VERSION 5.8 ;
BUSBITCHARS "[]" ;
DIVIDERCHAR "/" ;
UNITS
    DATABASE MICRONS 1000 ;
END UNITS

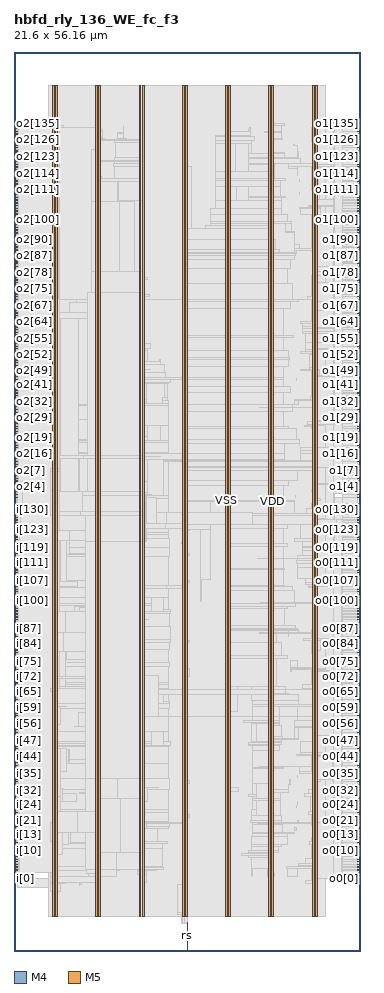
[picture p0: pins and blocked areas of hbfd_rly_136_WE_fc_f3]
MACRO hbfd_rly_136_WE_fc_f3
  FOREIGN hbfd_rly_136_WE_fc_f3 0 0 ;
  CLASS BLOCK ;
  SIZE 21.6 BY 56.16 ;
  PIN clk_in
    DIRECTION INPUT ;
    USE SIGNAL ;
    PORT
      LAYER M4 ;
        RECT  0 16.224 0.192 16.248 ;
    END
  END clk_in
  PIN clk_out0
    DIRECTION OUTPUT ;
    USE SIGNAL ;
    PORT
      LAYER M4 ;
        RECT  21.408 16.224 21.6 16.248 ;
    END
  END clk_out0
  PIN clk_out1
    DIRECTION OUTPUT ;
    USE SIGNAL ;
    PORT
      LAYER M4 ;
        RECT  21.408 39.984 21.6 40.008 ;
    END
  END clk_out1
  PIN clk_out2
    DIRECTION OUTPUT ;
    USE SIGNAL ;
    PORT
      LAYER M4 ;
        RECT  0 39.984 0.192 40.008 ;
    END
  END clk_out2
  PIN i[0]
    DIRECTION INPUT ;
    USE SIGNAL ;
    PORT
      LAYER M4 ;
        RECT  0 4.512 0.192 4.536 ;
    END
  END i[0]
  PIN i[100]
    DIRECTION INPUT ;
    USE SIGNAL ;
    PORT
      LAYER M4 ;
        RECT  0 21.888 0.192 21.912 ;
    END
  END i[100]
  PIN i[101]
    DIRECTION INPUT ;
    USE SIGNAL ;
    PORT
      LAYER M4 ;
        RECT  0 22.032 0.192 22.056 ;
    END
  END i[101]
  PIN i[102]
    DIRECTION INPUT ;
    USE SIGNAL ;
    PORT
      LAYER M4 ;
        RECT  0 22.224 0.192 22.248 ;
    END
  END i[102]
  PIN i[103]
    DIRECTION INPUT ;
    USE SIGNAL ;
    PORT
      LAYER M4 ;
        RECT  0 22.416 0.192 22.44 ;
    END
  END i[103]
  PIN i[104]
    DIRECTION INPUT ;
    USE SIGNAL ;
    PORT
      LAYER M4 ;
        RECT  0 22.56 0.192 22.584 ;
    END
  END i[104]
  PIN i[105]
    DIRECTION INPUT ;
    USE SIGNAL ;
    PORT
      LAYER M4 ;
        RECT  0 22.752 0.192 22.776 ;
    END
  END i[105]
  PIN i[106]
    DIRECTION INPUT ;
    USE SIGNAL ;
    PORT
      LAYER M4 ;
        RECT  0 22.896 0.192 22.92 ;
    END
  END i[106]
  PIN i[107]
    DIRECTION INPUT ;
    USE SIGNAL ;
    PORT
      LAYER M4 ;
        RECT  0 23.088 0.192 23.112 ;
    END
  END i[107]
  PIN i[108]
    DIRECTION INPUT ;
    USE SIGNAL ;
    PORT
      LAYER M4 ;
        RECT  0 23.232 0.192 23.256 ;
    END
  END i[108]
  PIN i[109]
    DIRECTION INPUT ;
    USE SIGNAL ;
    PORT
      LAYER M4 ;
        RECT  0 23.424 0.192 23.448 ;
    END
  END i[109]
  PIN i[10]
    DIRECTION INPUT ;
    USE SIGNAL ;
    PORT
      LAYER M4 ;
        RECT  0 6.24 0.192 6.264 ;
    END
  END i[10]
  PIN i[110]
    DIRECTION INPUT ;
    USE SIGNAL ;
    PORT
      LAYER M4 ;
        RECT  0 23.616 0.192 23.64 ;
    END
  END i[110]
  PIN i[111]
    DIRECTION INPUT ;
    USE SIGNAL ;
    PORT
      LAYER M4 ;
        RECT  0 23.76 0.192 23.784 ;
    END
  END i[111]
  PIN i[112]
    DIRECTION INPUT ;
    USE SIGNAL ;
    PORT
      LAYER M4 ;
        RECT  0 23.952 0.192 23.976 ;
    END
  END i[112]
  PIN i[113]
    DIRECTION INPUT ;
    USE SIGNAL ;
    PORT
      LAYER M4 ;
        RECT  0 24.096 0.192 24.12 ;
    END
  END i[113]
  PIN i[114]
    DIRECTION INPUT ;
    USE SIGNAL ;
    PORT
      LAYER M4 ;
        RECT  0 24.288 0.192 24.312 ;
    END
  END i[114]
  PIN i[115]
    DIRECTION INPUT ;
    USE SIGNAL ;
    PORT
      LAYER M4 ;
        RECT  0 24.48 0.192 24.504 ;
    END
  END i[115]
  PIN i[116]
    DIRECTION INPUT ;
    USE SIGNAL ;
    PORT
      LAYER M4 ;
        RECT  0 24.624 0.192 24.648 ;
    END
  END i[116]
  PIN i[117]
    DIRECTION INPUT ;
    USE SIGNAL ;
    PORT
      LAYER M4 ;
        RECT  0 24.816 0.192 24.84 ;
    END
  END i[117]
  PIN i[118]
    DIRECTION INPUT ;
    USE SIGNAL ;
    PORT
      LAYER M4 ;
        RECT  0 24.96 0.192 24.984 ;
    END
  END i[118]
  PIN i[119]
    DIRECTION INPUT ;
    USE SIGNAL ;
    PORT
      LAYER M4 ;
        RECT  0 25.152 0.192 25.176 ;
    END
  END i[119]
  PIN i[11]
    DIRECTION INPUT ;
    USE SIGNAL ;
    PORT
      LAYER M4 ;
        RECT  0 6.432 0.192 6.456 ;
    END
  END i[11]
  PIN i[120]
    DIRECTION INPUT ;
    USE SIGNAL ;
    PORT
      LAYER M4 ;
        RECT  0 25.296 0.192 25.32 ;
    END
  END i[120]
  PIN i[121]
    DIRECTION INPUT ;
    USE SIGNAL ;
    PORT
      LAYER M4 ;
        RECT  0 25.488 0.192 25.512 ;
    END
  END i[121]
  PIN i[122]
    DIRECTION INPUT ;
    USE SIGNAL ;
    PORT
      LAYER M4 ;
        RECT  0 25.68 0.192 25.704 ;
    END
  END i[122]
  PIN i[123]
    DIRECTION INPUT ;
    USE SIGNAL ;
    PORT
      LAYER M4 ;
        RECT  0 25.824 0.192 25.848 ;
    END
  END i[123]
  PIN i[124]
    DIRECTION INPUT ;
    USE SIGNAL ;
    PORT
      LAYER M4 ;
        RECT  0 26.016 0.192 26.04 ;
    END
  END i[124]
  PIN i[125]
    DIRECTION INPUT ;
    USE SIGNAL ;
    PORT
      LAYER M4 ;
        RECT  0 26.16 0.192 26.184 ;
    END
  END i[125]
  PIN i[126]
    DIRECTION INPUT ;
    USE SIGNAL ;
    PORT
      LAYER M4 ;
        RECT  0 26.352 0.192 26.376 ;
    END
  END i[126]
  PIN i[127]
    DIRECTION INPUT ;
    USE SIGNAL ;
    PORT
      LAYER M4 ;
        RECT  0 26.496 0.192 26.52 ;
    END
  END i[127]
  PIN i[128]
    DIRECTION INPUT ;
    USE SIGNAL ;
    PORT
      LAYER M4 ;
        RECT  0 26.688 0.192 26.712 ;
    END
  END i[128]
  PIN i[129]
    DIRECTION INPUT ;
    USE SIGNAL ;
    PORT
      LAYER M4 ;
        RECT  0 26.88 0.192 26.904 ;
    END
  END i[129]
  PIN i[12]
    DIRECTION INPUT ;
    USE SIGNAL ;
    PORT
      LAYER M4 ;
        RECT  0 6.576 0.192 6.6 ;
    END
  END i[12]
  PIN i[130]
    DIRECTION INPUT ;
    USE SIGNAL ;
    PORT
      LAYER M4 ;
        RECT  0 27.024 0.192 27.048 ;
    END
  END i[130]
  PIN i[131]
    DIRECTION INPUT ;
    USE SIGNAL ;
    PORT
      LAYER M4 ;
        RECT  0 27.216 0.192 27.24 ;
    END
  END i[131]
  PIN i[132]
    DIRECTION INPUT ;
    USE SIGNAL ;
    PORT
      LAYER M4 ;
        RECT  0 27.36 0.192 27.384 ;
    END
  END i[132]
  PIN i[133]
    DIRECTION INPUT ;
    USE SIGNAL ;
    PORT
      LAYER M4 ;
        RECT  0 27.552 0.192 27.576 ;
    END
  END i[133]
  PIN i[134]
    DIRECTION INPUT ;
    USE SIGNAL ;
    PORT
      LAYER M4 ;
        RECT  0 27.744 0.192 27.768 ;
    END
  END i[134]
  PIN i[135]
    DIRECTION INPUT ;
    USE SIGNAL ;
    PORT
      LAYER M4 ;
        RECT  0 27.888 0.192 27.912 ;
    END
  END i[135]
  PIN i[13]
    DIRECTION INPUT ;
    USE SIGNAL ;
    PORT
      LAYER M4 ;
        RECT  0 6.768 0.192 6.792 ;
    END
  END i[13]
  PIN i[14]
    DIRECTION INPUT ;
    USE SIGNAL ;
    PORT
      LAYER M4 ;
        RECT  0 6.96 0.192 6.984 ;
    END
  END i[14]
  PIN i[15]
    DIRECTION INPUT ;
    USE SIGNAL ;
    PORT
      LAYER M4 ;
        RECT  0 7.104 0.192 7.128 ;
    END
  END i[15]
  PIN i[16]
    DIRECTION INPUT ;
    USE SIGNAL ;
    PORT
      LAYER M4 ;
        RECT  0 7.296 0.192 7.32 ;
    END
  END i[16]
  PIN i[17]
    DIRECTION INPUT ;
    USE SIGNAL ;
    PORT
      LAYER M4 ;
        RECT  0 7.44 0.192 7.464 ;
    END
  END i[17]
  PIN i[18]
    DIRECTION INPUT ;
    USE SIGNAL ;
    PORT
      LAYER M4 ;
        RECT  0 7.632 0.192 7.656 ;
    END
  END i[18]
  PIN i[19]
    DIRECTION INPUT ;
    USE SIGNAL ;
    PORT
      LAYER M4 ;
        RECT  0 7.776 0.192 7.8 ;
    END
  END i[19]
  PIN i[1]
    DIRECTION INPUT ;
    USE SIGNAL ;
    PORT
      LAYER M4 ;
        RECT  0 4.704 0.192 4.728 ;
    END
  END i[1]
  PIN i[20]
    DIRECTION INPUT ;
    USE SIGNAL ;
    PORT
      LAYER M4 ;
        RECT  0 7.968 0.192 7.992 ;
    END
  END i[20]
  PIN i[21]
    DIRECTION INPUT ;
    USE SIGNAL ;
    PORT
      LAYER M4 ;
        RECT  0 8.16 0.192 8.184 ;
    END
  END i[21]
  PIN i[22]
    DIRECTION INPUT ;
    USE SIGNAL ;
    PORT
      LAYER M4 ;
        RECT  0 8.304 0.192 8.328 ;
    END
  END i[22]
  PIN i[23]
    DIRECTION INPUT ;
    USE SIGNAL ;
    PORT
      LAYER M4 ;
        RECT  0 8.496 0.192 8.52 ;
    END
  END i[23]
  PIN i[24]
    DIRECTION INPUT ;
    USE SIGNAL ;
    PORT
      LAYER M4 ;
        RECT  0 8.64 0.192 8.664 ;
    END
  END i[24]
  PIN i[25]
    DIRECTION INPUT ;
    USE SIGNAL ;
    PORT
      LAYER M4 ;
        RECT  0 8.832 0.192 8.856 ;
    END
  END i[25]
  PIN i[26]
    DIRECTION INPUT ;
    USE SIGNAL ;
    PORT
      LAYER M4 ;
        RECT  0 8.976 0.192 9 ;
    END
  END i[26]
  PIN i[27]
    DIRECTION INPUT ;
    USE SIGNAL ;
    PORT
      LAYER M4 ;
        RECT  0 9.168 0.192 9.192 ;
    END
  END i[27]
  PIN i[28]
    DIRECTION INPUT ;
    USE SIGNAL ;
    PORT
      LAYER M4 ;
        RECT  0 9.36 0.192 9.384 ;
    END
  END i[28]
  PIN i[29]
    DIRECTION INPUT ;
    USE SIGNAL ;
    PORT
      LAYER M4 ;
        RECT  0 9.504 0.192 9.528 ;
    END
  END i[29]
  PIN i[2]
    DIRECTION INPUT ;
    USE SIGNAL ;
    PORT
      LAYER M4 ;
        RECT  0 4.896 0.192 4.92 ;
    END
  END i[2]
  PIN i[30]
    DIRECTION INPUT ;
    USE SIGNAL ;
    PORT
      LAYER M4 ;
        RECT  0 9.696 0.192 9.72 ;
    END
  END i[30]
  PIN i[31]
    DIRECTION INPUT ;
    USE SIGNAL ;
    PORT
      LAYER M4 ;
        RECT  0 9.84 0.192 9.864 ;
    END
  END i[31]
  PIN i[32]
    DIRECTION INPUT ;
    USE SIGNAL ;
    PORT
      LAYER M4 ;
        RECT  0 10.032 0.192 10.056 ;
    END
  END i[32]
  PIN i[33]
    DIRECTION INPUT ;
    USE SIGNAL ;
    PORT
      LAYER M4 ;
        RECT  0 10.224 0.192 10.248 ;
    END
  END i[33]
  PIN i[34]
    DIRECTION INPUT ;
    USE SIGNAL ;
    PORT
      LAYER M4 ;
        RECT  0 10.368 0.192 10.392 ;
    END
  END i[34]
  PIN i[35]
    DIRECTION INPUT ;
    USE SIGNAL ;
    PORT
      LAYER M4 ;
        RECT  0 10.56 0.192 10.584 ;
    END
  END i[35]
  PIN i[36]
    DIRECTION INPUT ;
    USE SIGNAL ;
    PORT
      LAYER M4 ;
        RECT  0 10.704 0.192 10.728 ;
    END
  END i[36]
  PIN i[37]
    DIRECTION INPUT ;
    USE SIGNAL ;
    PORT
      LAYER M4 ;
        RECT  0 10.896 0.192 10.92 ;
    END
  END i[37]
  PIN i[38]
    DIRECTION INPUT ;
    USE SIGNAL ;
    PORT
      LAYER M4 ;
        RECT  0 11.04 0.192 11.064 ;
    END
  END i[38]
  PIN i[39]
    DIRECTION INPUT ;
    USE SIGNAL ;
    PORT
      LAYER M4 ;
        RECT  0 11.232 0.192 11.256 ;
    END
  END i[39]
  PIN i[3]
    DIRECTION INPUT ;
    USE SIGNAL ;
    PORT
      LAYER M4 ;
        RECT  0 5.04 0.192 5.064 ;
    END
  END i[3]
  PIN i[40]
    DIRECTION INPUT ;
    USE SIGNAL ;
    PORT
      LAYER M4 ;
        RECT  0 11.424 0.192 11.448 ;
    END
  END i[40]
  PIN i[41]
    DIRECTION INPUT ;
    USE SIGNAL ;
    PORT
      LAYER M4 ;
        RECT  0 11.568 0.192 11.592 ;
    END
  END i[41]
  PIN i[42]
    DIRECTION INPUT ;
    USE SIGNAL ;
    PORT
      LAYER M4 ;
        RECT  0 11.76 0.192 11.784 ;
    END
  END i[42]
  PIN i[43]
    DIRECTION INPUT ;
    USE SIGNAL ;
    PORT
      LAYER M4 ;
        RECT  0 11.904 0.192 11.928 ;
    END
  END i[43]
  PIN i[44]
    DIRECTION INPUT ;
    USE SIGNAL ;
    PORT
      LAYER M4 ;
        RECT  0 12.096 0.192 12.12 ;
    END
  END i[44]
  PIN i[45]
    DIRECTION INPUT ;
    USE SIGNAL ;
    PORT
      LAYER M4 ;
        RECT  0 12.24 0.192 12.264 ;
    END
  END i[45]
  PIN i[46]
    DIRECTION INPUT ;
    USE SIGNAL ;
    PORT
      LAYER M4 ;
        RECT  0 12.432 0.192 12.456 ;
    END
  END i[46]
  PIN i[47]
    DIRECTION INPUT ;
    USE SIGNAL ;
    PORT
      LAYER M4 ;
        RECT  0 12.624 0.192 12.648 ;
    END
  END i[47]
  PIN i[48]
    DIRECTION INPUT ;
    USE SIGNAL ;
    PORT
      LAYER M4 ;
        RECT  0 12.768 0.192 12.792 ;
    END
  END i[48]
  PIN i[49]
    DIRECTION INPUT ;
    USE SIGNAL ;
    PORT
      LAYER M4 ;
        RECT  0 12.96 0.192 12.984 ;
    END
  END i[49]
  PIN i[4]
    DIRECTION INPUT ;
    USE SIGNAL ;
    PORT
      LAYER M4 ;
        RECT  0 5.232 0.192 5.256 ;
    END
  END i[4]
  PIN i[50]
    DIRECTION INPUT ;
    USE SIGNAL ;
    PORT
      LAYER M4 ;
        RECT  0 13.104 0.192 13.128 ;
    END
  END i[50]
  PIN i[51]
    DIRECTION INPUT ;
    USE SIGNAL ;
    PORT
      LAYER M4 ;
        RECT  0 13.296 0.192 13.32 ;
    END
  END i[51]
  PIN i[52]
    DIRECTION INPUT ;
    USE SIGNAL ;
    PORT
      LAYER M4 ;
        RECT  0 13.44 0.192 13.464 ;
    END
  END i[52]
  PIN i[53]
    DIRECTION INPUT ;
    USE SIGNAL ;
    PORT
      LAYER M4 ;
        RECT  0 13.632 0.192 13.656 ;
    END
  END i[53]
  PIN i[54]
    DIRECTION INPUT ;
    USE SIGNAL ;
    PORT
      LAYER M4 ;
        RECT  0 13.824 0.192 13.848 ;
    END
  END i[54]
  PIN i[55]
    DIRECTION INPUT ;
    USE SIGNAL ;
    PORT
      LAYER M4 ;
        RECT  0 13.968 0.192 13.992 ;
    END
  END i[55]
  PIN i[56]
    DIRECTION INPUT ;
    USE SIGNAL ;
    PORT
      LAYER M4 ;
        RECT  0 14.16 0.192 14.184 ;
    END
  END i[56]
  PIN i[57]
    DIRECTION INPUT ;
    USE SIGNAL ;
    PORT
      LAYER M4 ;
        RECT  0 14.304 0.192 14.328 ;
    END
  END i[57]
  PIN i[58]
    DIRECTION INPUT ;
    USE SIGNAL ;
    PORT
      LAYER M4 ;
        RECT  0 14.496 0.192 14.52 ;
    END
  END i[58]
  PIN i[59]
    DIRECTION INPUT ;
    USE SIGNAL ;
    PORT
      LAYER M4 ;
        RECT  0 14.688 0.192 14.712 ;
    END
  END i[59]
  PIN i[5]
    DIRECTION INPUT ;
    USE SIGNAL ;
    PORT
      LAYER M4 ;
        RECT  0 5.376 0.192 5.4 ;
    END
  END i[5]
  PIN i[60]
    DIRECTION INPUT ;
    USE SIGNAL ;
    PORT
      LAYER M4 ;
        RECT  0 14.832 0.192 14.856 ;
    END
  END i[60]
  PIN i[61]
    DIRECTION INPUT ;
    USE SIGNAL ;
    PORT
      LAYER M4 ;
        RECT  0 15.024 0.192 15.048 ;
    END
  END i[61]
  PIN i[62]
    DIRECTION INPUT ;
    USE SIGNAL ;
    PORT
      LAYER M4 ;
        RECT  0 15.168 0.192 15.192 ;
    END
  END i[62]
  PIN i[63]
    DIRECTION INPUT ;
    USE SIGNAL ;
    PORT
      LAYER M4 ;
        RECT  0 15.36 0.192 15.384 ;
    END
  END i[63]
  PIN i[64]
    DIRECTION INPUT ;
    USE SIGNAL ;
    PORT
      LAYER M4 ;
        RECT  0 15.504 0.192 15.528 ;
    END
  END i[64]
  PIN i[65]
    DIRECTION INPUT ;
    USE SIGNAL ;
    PORT
      LAYER M4 ;
        RECT  0 15.696 0.192 15.72 ;
    END
  END i[65]
  PIN i[66]
    DIRECTION INPUT ;
    USE SIGNAL ;
    PORT
      LAYER M4 ;
        RECT  0 15.888 0.192 15.912 ;
    END
  END i[66]
  PIN i[67]
    DIRECTION INPUT ;
    USE SIGNAL ;
    PORT
      LAYER M4 ;
        RECT  0 16.032 0.192 16.056 ;
    END
  END i[67]
  PIN i[68]
    DIRECTION INPUT ;
    USE SIGNAL ;
    PORT
      LAYER M4 ;
        RECT  0 16.368 0.192 16.392 ;
    END
  END i[68]
  PIN i[69]
    DIRECTION INPUT ;
    USE SIGNAL ;
    PORT
      LAYER M4 ;
        RECT  0 16.56 0.192 16.584 ;
    END
  END i[69]
  PIN i[6]
    DIRECTION INPUT ;
    USE SIGNAL ;
    PORT
      LAYER M4 ;
        RECT  0 5.568 0.192 5.592 ;
    END
  END i[6]
  PIN i[70]
    DIRECTION INPUT ;
    USE SIGNAL ;
    PORT
      LAYER M4 ;
        RECT  0 16.704 0.192 16.728 ;
    END
  END i[70]
  PIN i[71]
    DIRECTION INPUT ;
    USE SIGNAL ;
    PORT
      LAYER M4 ;
        RECT  0 16.896 0.192 16.92 ;
    END
  END i[71]
  PIN i[72]
    DIRECTION INPUT ;
    USE SIGNAL ;
    PORT
      LAYER M4 ;
        RECT  0 17.088 0.192 17.112 ;
    END
  END i[72]
  PIN i[73]
    DIRECTION INPUT ;
    USE SIGNAL ;
    PORT
      LAYER M4 ;
        RECT  0 17.232 0.192 17.256 ;
    END
  END i[73]
  PIN i[74]
    DIRECTION INPUT ;
    USE SIGNAL ;
    PORT
      LAYER M4 ;
        RECT  0 17.424 0.192 17.448 ;
    END
  END i[74]
  PIN i[75]
    DIRECTION INPUT ;
    USE SIGNAL ;
    PORT
      LAYER M4 ;
        RECT  0 17.568 0.192 17.592 ;
    END
  END i[75]
  PIN i[76]
    DIRECTION INPUT ;
    USE SIGNAL ;
    PORT
      LAYER M4 ;
        RECT  0 17.76 0.192 17.784 ;
    END
  END i[76]
  PIN i[77]
    DIRECTION INPUT ;
    USE SIGNAL ;
    PORT
      LAYER M4 ;
        RECT  0 17.952 0.192 17.976 ;
    END
  END i[77]
  PIN i[78]
    DIRECTION INPUT ;
    USE SIGNAL ;
    PORT
      LAYER M4 ;
        RECT  0 18.096 0.192 18.12 ;
    END
  END i[78]
  PIN i[79]
    DIRECTION INPUT ;
    USE SIGNAL ;
    PORT
      LAYER M4 ;
        RECT  0 18.288 0.192 18.312 ;
    END
  END i[79]
  PIN i[7]
    DIRECTION INPUT ;
    USE SIGNAL ;
    PORT
      LAYER M4 ;
        RECT  0 5.712 0.192 5.736 ;
    END
  END i[7]
  PIN i[80]
    DIRECTION INPUT ;
    USE SIGNAL ;
    PORT
      LAYER M4 ;
        RECT  0 18.432 0.192 18.456 ;
    END
  END i[80]
  PIN i[81]
    DIRECTION INPUT ;
    USE SIGNAL ;
    PORT
      LAYER M4 ;
        RECT  0 18.624 0.192 18.648 ;
    END
  END i[81]
  PIN i[82]
    DIRECTION INPUT ;
    USE SIGNAL ;
    PORT
      LAYER M4 ;
        RECT  0 18.768 0.192 18.792 ;
    END
  END i[82]
  PIN i[83]
    DIRECTION INPUT ;
    USE SIGNAL ;
    PORT
      LAYER M4 ;
        RECT  0 18.96 0.192 18.984 ;
    END
  END i[83]
  PIN i[84]
    DIRECTION INPUT ;
    USE SIGNAL ;
    PORT
      LAYER M4 ;
        RECT  0 19.152 0.192 19.176 ;
    END
  END i[84]
  PIN i[85]
    DIRECTION INPUT ;
    USE SIGNAL ;
    PORT
      LAYER M4 ;
        RECT  0 19.296 0.192 19.32 ;
    END
  END i[85]
  PIN i[86]
    DIRECTION INPUT ;
    USE SIGNAL ;
    PORT
      LAYER M4 ;
        RECT  0 19.488 0.192 19.512 ;
    END
  END i[86]
  PIN i[87]
    DIRECTION INPUT ;
    USE SIGNAL ;
    PORT
      LAYER M4 ;
        RECT  0 19.632 0.192 19.656 ;
    END
  END i[87]
  PIN i[88]
    DIRECTION INPUT ;
    USE SIGNAL ;
    PORT
      LAYER M4 ;
        RECT  0 19.824 0.192 19.848 ;
    END
  END i[88]
  PIN i[89]
    DIRECTION INPUT ;
    USE SIGNAL ;
    PORT
      LAYER M4 ;
        RECT  0 19.968 0.192 19.992 ;
    END
  END i[89]
  PIN i[8]
    DIRECTION INPUT ;
    USE SIGNAL ;
    PORT
      LAYER M4 ;
        RECT  0 5.904 0.192 5.928 ;
    END
  END i[8]
  PIN i[90]
    DIRECTION INPUT ;
    USE SIGNAL ;
    PORT
      LAYER M4 ;
        RECT  0 20.16 0.192 20.184 ;
    END
  END i[90]
  PIN i[91]
    DIRECTION INPUT ;
    USE SIGNAL ;
    PORT
      LAYER M4 ;
        RECT  0 20.352 0.192 20.376 ;
    END
  END i[91]
  PIN i[92]
    DIRECTION INPUT ;
    USE SIGNAL ;
    PORT
      LAYER M4 ;
        RECT  0 20.496 0.192 20.52 ;
    END
  END i[92]
  PIN i[93]
    DIRECTION INPUT ;
    USE SIGNAL ;
    PORT
      LAYER M4 ;
        RECT  0 20.688 0.192 20.712 ;
    END
  END i[93]
  PIN i[94]
    DIRECTION INPUT ;
    USE SIGNAL ;
    PORT
      LAYER M4 ;
        RECT  0 20.832 0.192 20.856 ;
    END
  END i[94]
  PIN i[95]
    DIRECTION INPUT ;
    USE SIGNAL ;
    PORT
      LAYER M4 ;
        RECT  0 21.024 0.192 21.048 ;
    END
  END i[95]
  PIN i[96]
    DIRECTION INPUT ;
    USE SIGNAL ;
    PORT
      LAYER M4 ;
        RECT  0 21.216 0.192 21.24 ;
    END
  END i[96]
  PIN i[97]
    DIRECTION INPUT ;
    USE SIGNAL ;
    PORT
      LAYER M4 ;
        RECT  0 21.36 0.192 21.384 ;
    END
  END i[97]
  PIN i[98]
    DIRECTION INPUT ;
    USE SIGNAL ;
    PORT
      LAYER M4 ;
        RECT  0 21.552 0.192 21.576 ;
    END
  END i[98]
  PIN i[99]
    DIRECTION INPUT ;
    USE SIGNAL ;
    PORT
      LAYER M4 ;
        RECT  0 21.696 0.192 21.72 ;
    END
  END i[99]
  PIN i[9]
    DIRECTION INPUT ;
    USE SIGNAL ;
    PORT
      LAYER M4 ;
        RECT  0 6.096 0.192 6.12 ;
    END
  END i[9]
  PIN o0[0]
    DIRECTION OUTPUT ;
    USE SIGNAL ;
    PORT
      LAYER M4 ;
        RECT  21.408 4.512 21.6 4.536 ;
    END
  END o0[0]
  PIN o0[100]
    DIRECTION OUTPUT ;
    USE SIGNAL ;
    PORT
      LAYER M4 ;
        RECT  21.408 21.888 21.6 21.912 ;
    END
  END o0[100]
  PIN o0[101]
    DIRECTION OUTPUT ;
    USE SIGNAL ;
    PORT
      LAYER M4 ;
        RECT  21.408 22.032 21.6 22.056 ;
    END
  END o0[101]
  PIN o0[102]
    DIRECTION OUTPUT ;
    USE SIGNAL ;
    PORT
      LAYER M4 ;
        RECT  21.408 22.224 21.6 22.248 ;
    END
  END o0[102]
  PIN o0[103]
    DIRECTION OUTPUT ;
    USE SIGNAL ;
    PORT
      LAYER M4 ;
        RECT  21.408 22.416 21.6 22.44 ;
    END
  END o0[103]
  PIN o0[104]
    DIRECTION OUTPUT ;
    USE SIGNAL ;
    PORT
      LAYER M4 ;
        RECT  21.408 22.56 21.6 22.584 ;
    END
  END o0[104]
  PIN o0[105]
    DIRECTION OUTPUT ;
    USE SIGNAL ;
    PORT
      LAYER M4 ;
        RECT  21.408 22.752 21.6 22.776 ;
    END
  END o0[105]
  PIN o0[106]
    DIRECTION OUTPUT ;
    USE SIGNAL ;
    PORT
      LAYER M4 ;
        RECT  21.408 22.896 21.6 22.92 ;
    END
  END o0[106]
  PIN o0[107]
    DIRECTION OUTPUT ;
    USE SIGNAL ;
    PORT
      LAYER M4 ;
        RECT  21.408 23.088 21.6 23.112 ;
    END
  END o0[107]
  PIN o0[108]
    DIRECTION OUTPUT ;
    USE SIGNAL ;
    PORT
      LAYER M4 ;
        RECT  21.408 23.232 21.6 23.256 ;
    END
  END o0[108]
  PIN o0[109]
    DIRECTION OUTPUT ;
    USE SIGNAL ;
    PORT
      LAYER M4 ;
        RECT  21.408 23.424 21.6 23.448 ;
    END
  END o0[109]
  PIN o0[10]
    DIRECTION OUTPUT ;
    USE SIGNAL ;
    PORT
      LAYER M4 ;
        RECT  21.408 6.24 21.6 6.264 ;
    END
  END o0[10]
  PIN o0[110]
    DIRECTION OUTPUT ;
    USE SIGNAL ;
    PORT
      LAYER M4 ;
        RECT  21.408 23.616 21.6 23.64 ;
    END
  END o0[110]
  PIN o0[111]
    DIRECTION OUTPUT ;
    USE SIGNAL ;
    PORT
      LAYER M4 ;
        RECT  21.408 23.76 21.6 23.784 ;
    END
  END o0[111]
  PIN o0[112]
    DIRECTION OUTPUT ;
    USE SIGNAL ;
    PORT
      LAYER M4 ;
        RECT  21.408 23.952 21.6 23.976 ;
    END
  END o0[112]
  PIN o0[113]
    DIRECTION OUTPUT ;
    USE SIGNAL ;
    PORT
      LAYER M4 ;
        RECT  21.408 24.096 21.6 24.12 ;
    END
  END o0[113]
  PIN o0[114]
    DIRECTION OUTPUT ;
    USE SIGNAL ;
    PORT
      LAYER M4 ;
        RECT  21.408 24.288 21.6 24.312 ;
    END
  END o0[114]
  PIN o0[115]
    DIRECTION OUTPUT ;
    USE SIGNAL ;
    PORT
      LAYER M4 ;
        RECT  21.408 24.48 21.6 24.504 ;
    END
  END o0[115]
  PIN o0[116]
    DIRECTION OUTPUT ;
    USE SIGNAL ;
    PORT
      LAYER M4 ;
        RECT  21.408 24.624 21.6 24.648 ;
    END
  END o0[116]
  PIN o0[117]
    DIRECTION OUTPUT ;
    USE SIGNAL ;
    PORT
      LAYER M4 ;
        RECT  21.408 24.816 21.6 24.84 ;
    END
  END o0[117]
  PIN o0[118]
    DIRECTION OUTPUT ;
    USE SIGNAL ;
    PORT
      LAYER M4 ;
        RECT  21.408 24.96 21.6 24.984 ;
    END
  END o0[118]
  PIN o0[119]
    DIRECTION OUTPUT ;
    USE SIGNAL ;
    PORT
      LAYER M4 ;
        RECT  21.408 25.152 21.6 25.176 ;
    END
  END o0[119]
  PIN o0[11]
    DIRECTION OUTPUT ;
    USE SIGNAL ;
    PORT
      LAYER M4 ;
        RECT  21.408 6.432 21.6 6.456 ;
    END
  END o0[11]
  PIN o0[120]
    DIRECTION OUTPUT ;
    USE SIGNAL ;
    PORT
      LAYER M4 ;
        RECT  21.408 25.296 21.6 25.32 ;
    END
  END o0[120]
  PIN o0[121]
    DIRECTION OUTPUT ;
    USE SIGNAL ;
    PORT
      LAYER M4 ;
        RECT  21.408 25.488 21.6 25.512 ;
    END
  END o0[121]
  PIN o0[122]
    DIRECTION OUTPUT ;
    USE SIGNAL ;
    PORT
      LAYER M4 ;
        RECT  21.408 25.68 21.6 25.704 ;
    END
  END o0[122]
  PIN o0[123]
    DIRECTION OUTPUT ;
    USE SIGNAL ;
    PORT
      LAYER M4 ;
        RECT  21.408 25.824 21.6 25.848 ;
    END
  END o0[123]
  PIN o0[124]
    DIRECTION OUTPUT ;
    USE SIGNAL ;
    PORT
      LAYER M4 ;
        RECT  21.408 26.016 21.6 26.04 ;
    END
  END o0[124]
  PIN o0[125]
    DIRECTION OUTPUT ;
    USE SIGNAL ;
    PORT
      LAYER M4 ;
        RECT  21.408 26.16 21.6 26.184 ;
    END
  END o0[125]
  PIN o0[126]
    DIRECTION OUTPUT ;
    USE SIGNAL ;
    PORT
      LAYER M4 ;
        RECT  21.408 26.352 21.6 26.376 ;
    END
  END o0[126]
  PIN o0[127]
    DIRECTION OUTPUT ;
    USE SIGNAL ;
    PORT
      LAYER M4 ;
        RECT  21.408 26.496 21.6 26.52 ;
    END
  END o0[127]
  PIN o0[128]
    DIRECTION OUTPUT ;
    USE SIGNAL ;
    PORT
      LAYER M4 ;
        RECT  21.408 26.688 21.6 26.712 ;
    END
  END o0[128]
  PIN o0[129]
    DIRECTION OUTPUT ;
    USE SIGNAL ;
    PORT
      LAYER M4 ;
        RECT  21.408 26.88 21.6 26.904 ;
    END
  END o0[129]
  PIN o0[12]
    DIRECTION OUTPUT ;
    USE SIGNAL ;
    PORT
      LAYER M4 ;
        RECT  21.408 6.576 21.6 6.6 ;
    END
  END o0[12]
  PIN o0[130]
    DIRECTION OUTPUT ;
    USE SIGNAL ;
    PORT
      LAYER M4 ;
        RECT  21.408 27.024 21.6 27.048 ;
    END
  END o0[130]
  PIN o0[131]
    DIRECTION OUTPUT ;
    USE SIGNAL ;
    PORT
      LAYER M4 ;
        RECT  21.408 27.216 21.6 27.24 ;
    END
  END o0[131]
  PIN o0[132]
    DIRECTION OUTPUT ;
    USE SIGNAL ;
    PORT
      LAYER M4 ;
        RECT  21.408 27.36 21.6 27.384 ;
    END
  END o0[132]
  PIN o0[133]
    DIRECTION OUTPUT ;
    USE SIGNAL ;
    PORT
      LAYER M4 ;
        RECT  21.408 27.552 21.6 27.576 ;
    END
  END o0[133]
  PIN o0[134]
    DIRECTION OUTPUT ;
    USE SIGNAL ;
    PORT
      LAYER M4 ;
        RECT  21.408 27.744 21.6 27.768 ;
    END
  END o0[134]
  PIN o0[135]
    DIRECTION OUTPUT ;
    USE SIGNAL ;
    PORT
      LAYER M4 ;
        RECT  21.408 27.888 21.6 27.912 ;
    END
  END o0[135]
  PIN o0[13]
    DIRECTION OUTPUT ;
    USE SIGNAL ;
    PORT
      LAYER M4 ;
        RECT  21.408 6.768 21.6 6.792 ;
    END
  END o0[13]
  PIN o0[14]
    DIRECTION OUTPUT ;
    USE SIGNAL ;
    PORT
      LAYER M4 ;
        RECT  21.408 6.96 21.6 6.984 ;
    END
  END o0[14]
  PIN o0[15]
    DIRECTION OUTPUT ;
    USE SIGNAL ;
    PORT
      LAYER M4 ;
        RECT  21.408 7.104 21.6 7.128 ;
    END
  END o0[15]
  PIN o0[16]
    DIRECTION OUTPUT ;
    USE SIGNAL ;
    PORT
      LAYER M4 ;
        RECT  21.408 7.296 21.6 7.32 ;
    END
  END o0[16]
  PIN o0[17]
    DIRECTION OUTPUT ;
    USE SIGNAL ;
    PORT
      LAYER M4 ;
        RECT  21.408 7.44 21.6 7.464 ;
    END
  END o0[17]
  PIN o0[18]
    DIRECTION OUTPUT ;
    USE SIGNAL ;
    PORT
      LAYER M4 ;
        RECT  21.408 7.632 21.6 7.656 ;
    END
  END o0[18]
  PIN o0[19]
    DIRECTION OUTPUT ;
    USE SIGNAL ;
    PORT
      LAYER M4 ;
        RECT  21.408 7.776 21.6 7.8 ;
    END
  END o0[19]
  PIN o0[1]
    DIRECTION OUTPUT ;
    USE SIGNAL ;
    PORT
      LAYER M4 ;
        RECT  21.408 4.704 21.6 4.728 ;
    END
  END o0[1]
  PIN o0[20]
    DIRECTION OUTPUT ;
    USE SIGNAL ;
    PORT
      LAYER M4 ;
        RECT  21.408 7.968 21.6 7.992 ;
    END
  END o0[20]
  PIN o0[21]
    DIRECTION OUTPUT ;
    USE SIGNAL ;
    PORT
      LAYER M4 ;
        RECT  21.408 8.16 21.6 8.184 ;
    END
  END o0[21]
  PIN o0[22]
    DIRECTION OUTPUT ;
    USE SIGNAL ;
    PORT
      LAYER M4 ;
        RECT  21.408 8.304 21.6 8.328 ;
    END
  END o0[22]
  PIN o0[23]
    DIRECTION OUTPUT ;
    USE SIGNAL ;
    PORT
      LAYER M4 ;
        RECT  21.408 8.496 21.6 8.52 ;
    END
  END o0[23]
  PIN o0[24]
    DIRECTION OUTPUT ;
    USE SIGNAL ;
    PORT
      LAYER M4 ;
        RECT  21.408 8.64 21.6 8.664 ;
    END
  END o0[24]
  PIN o0[25]
    DIRECTION OUTPUT ;
    USE SIGNAL ;
    PORT
      LAYER M4 ;
        RECT  21.408 8.832 21.6 8.856 ;
    END
  END o0[25]
  PIN o0[26]
    DIRECTION OUTPUT ;
    USE SIGNAL ;
    PORT
      LAYER M4 ;
        RECT  21.408 8.976 21.6 9 ;
    END
  END o0[26]
  PIN o0[27]
    DIRECTION OUTPUT ;
    USE SIGNAL ;
    PORT
      LAYER M4 ;
        RECT  21.408 9.168 21.6 9.192 ;
    END
  END o0[27]
  PIN o0[28]
    DIRECTION OUTPUT ;
    USE SIGNAL ;
    PORT
      LAYER M4 ;
        RECT  21.408 9.36 21.6 9.384 ;
    END
  END o0[28]
  PIN o0[29]
    DIRECTION OUTPUT ;
    USE SIGNAL ;
    PORT
      LAYER M4 ;
        RECT  21.408 9.504 21.6 9.528 ;
    END
  END o0[29]
  PIN o0[2]
    DIRECTION OUTPUT ;
    USE SIGNAL ;
    PORT
      LAYER M4 ;
        RECT  21.408 4.896 21.6 4.92 ;
    END
  END o0[2]
  PIN o0[30]
    DIRECTION OUTPUT ;
    USE SIGNAL ;
    PORT
      LAYER M4 ;
        RECT  21.408 9.696 21.6 9.72 ;
    END
  END o0[30]
  PIN o0[31]
    DIRECTION OUTPUT ;
    USE SIGNAL ;
    PORT
      LAYER M4 ;
        RECT  21.408 9.84 21.6 9.864 ;
    END
  END o0[31]
  PIN o0[32]
    DIRECTION OUTPUT ;
    USE SIGNAL ;
    PORT
      LAYER M4 ;
        RECT  21.408 10.032 21.6 10.056 ;
    END
  END o0[32]
  PIN o0[33]
    DIRECTION OUTPUT ;
    USE SIGNAL ;
    PORT
      LAYER M4 ;
        RECT  21.408 10.224 21.6 10.248 ;
    END
  END o0[33]
  PIN o0[34]
    DIRECTION OUTPUT ;
    USE SIGNAL ;
    PORT
      LAYER M4 ;
        RECT  21.408 10.368 21.6 10.392 ;
    END
  END o0[34]
  PIN o0[35]
    DIRECTION OUTPUT ;
    USE SIGNAL ;
    PORT
      LAYER M4 ;
        RECT  21.408 10.56 21.6 10.584 ;
    END
  END o0[35]
  PIN o0[36]
    DIRECTION OUTPUT ;
    USE SIGNAL ;
    PORT
      LAYER M4 ;
        RECT  21.408 10.704 21.6 10.728 ;
    END
  END o0[36]
  PIN o0[37]
    DIRECTION OUTPUT ;
    USE SIGNAL ;
    PORT
      LAYER M4 ;
        RECT  21.408 10.896 21.6 10.92 ;
    END
  END o0[37]
  PIN o0[38]
    DIRECTION OUTPUT ;
    USE SIGNAL ;
    PORT
      LAYER M4 ;
        RECT  21.408 11.04 21.6 11.064 ;
    END
  END o0[38]
  PIN o0[39]
    DIRECTION OUTPUT ;
    USE SIGNAL ;
    PORT
      LAYER M4 ;
        RECT  21.408 11.232 21.6 11.256 ;
    END
  END o0[39]
  PIN o0[3]
    DIRECTION OUTPUT ;
    USE SIGNAL ;
    PORT
      LAYER M4 ;
        RECT  21.408 5.04 21.6 5.064 ;
    END
  END o0[3]
  PIN o0[40]
    DIRECTION OUTPUT ;
    USE SIGNAL ;
    PORT
      LAYER M4 ;
        RECT  21.408 11.424 21.6 11.448 ;
    END
  END o0[40]
  PIN o0[41]
    DIRECTION OUTPUT ;
    USE SIGNAL ;
    PORT
      LAYER M4 ;
        RECT  21.408 11.568 21.6 11.592 ;
    END
  END o0[41]
  PIN o0[42]
    DIRECTION OUTPUT ;
    USE SIGNAL ;
    PORT
      LAYER M4 ;
        RECT  21.408 11.76 21.6 11.784 ;
    END
  END o0[42]
  PIN o0[43]
    DIRECTION OUTPUT ;
    USE SIGNAL ;
    PORT
      LAYER M4 ;
        RECT  21.408 11.904 21.6 11.928 ;
    END
  END o0[43]
  PIN o0[44]
    DIRECTION OUTPUT ;
    USE SIGNAL ;
    PORT
      LAYER M4 ;
        RECT  21.408 12.096 21.6 12.12 ;
    END
  END o0[44]
  PIN o0[45]
    DIRECTION OUTPUT ;
    USE SIGNAL ;
    PORT
      LAYER M4 ;
        RECT  21.408 12.24 21.6 12.264 ;
    END
  END o0[45]
  PIN o0[46]
    DIRECTION OUTPUT ;
    USE SIGNAL ;
    PORT
      LAYER M4 ;
        RECT  21.408 12.432 21.6 12.456 ;
    END
  END o0[46]
  PIN o0[47]
    DIRECTION OUTPUT ;
    USE SIGNAL ;
    PORT
      LAYER M4 ;
        RECT  21.408 12.624 21.6 12.648 ;
    END
  END o0[47]
  PIN o0[48]
    DIRECTION OUTPUT ;
    USE SIGNAL ;
    PORT
      LAYER M4 ;
        RECT  21.408 12.768 21.6 12.792 ;
    END
  END o0[48]
  PIN o0[49]
    DIRECTION OUTPUT ;
    USE SIGNAL ;
    PORT
      LAYER M4 ;
        RECT  21.408 12.96 21.6 12.984 ;
    END
  END o0[49]
  PIN o0[4]
    DIRECTION OUTPUT ;
    USE SIGNAL ;
    PORT
      LAYER M4 ;
        RECT  21.408 5.232 21.6 5.256 ;
    END
  END o0[4]
  PIN o0[50]
    DIRECTION OUTPUT ;
    USE SIGNAL ;
    PORT
      LAYER M4 ;
        RECT  21.408 13.104 21.6 13.128 ;
    END
  END o0[50]
  PIN o0[51]
    DIRECTION OUTPUT ;
    USE SIGNAL ;
    PORT
      LAYER M4 ;
        RECT  21.408 13.296 21.6 13.32 ;
    END
  END o0[51]
  PIN o0[52]
    DIRECTION OUTPUT ;
    USE SIGNAL ;
    PORT
      LAYER M4 ;
        RECT  21.408 13.44 21.6 13.464 ;
    END
  END o0[52]
  PIN o0[53]
    DIRECTION OUTPUT ;
    USE SIGNAL ;
    PORT
      LAYER M4 ;
        RECT  21.408 13.632 21.6 13.656 ;
    END
  END o0[53]
  PIN o0[54]
    DIRECTION OUTPUT ;
    USE SIGNAL ;
    PORT
      LAYER M4 ;
        RECT  21.408 13.824 21.6 13.848 ;
    END
  END o0[54]
  PIN o0[55]
    DIRECTION OUTPUT ;
    USE SIGNAL ;
    PORT
      LAYER M4 ;
        RECT  21.408 13.968 21.6 13.992 ;
    END
  END o0[55]
  PIN o0[56]
    DIRECTION OUTPUT ;
    USE SIGNAL ;
    PORT
      LAYER M4 ;
        RECT  21.408 14.16 21.6 14.184 ;
    END
  END o0[56]
  PIN o0[57]
    DIRECTION OUTPUT ;
    USE SIGNAL ;
    PORT
      LAYER M4 ;
        RECT  21.408 14.304 21.6 14.328 ;
    END
  END o0[57]
  PIN o0[58]
    DIRECTION OUTPUT ;
    USE SIGNAL ;
    PORT
      LAYER M4 ;
        RECT  21.408 14.496 21.6 14.52 ;
    END
  END o0[58]
  PIN o0[59]
    DIRECTION OUTPUT ;
    USE SIGNAL ;
    PORT
      LAYER M4 ;
        RECT  21.408 14.688 21.6 14.712 ;
    END
  END o0[59]
  PIN o0[5]
    DIRECTION OUTPUT ;
    USE SIGNAL ;
    PORT
      LAYER M4 ;
        RECT  21.408 5.376 21.6 5.4 ;
    END
  END o0[5]
  PIN o0[60]
    DIRECTION OUTPUT ;
    USE SIGNAL ;
    PORT
      LAYER M4 ;
        RECT  21.408 14.832 21.6 14.856 ;
    END
  END o0[60]
  PIN o0[61]
    DIRECTION OUTPUT ;
    USE SIGNAL ;
    PORT
      LAYER M4 ;
        RECT  21.408 15.024 21.6 15.048 ;
    END
  END o0[61]
  PIN o0[62]
    DIRECTION OUTPUT ;
    USE SIGNAL ;
    PORT
      LAYER M4 ;
        RECT  21.408 15.168 21.6 15.192 ;
    END
  END o0[62]
  PIN o0[63]
    DIRECTION OUTPUT ;
    USE SIGNAL ;
    PORT
      LAYER M4 ;
        RECT  21.408 15.36 21.6 15.384 ;
    END
  END o0[63]
  PIN o0[64]
    DIRECTION OUTPUT ;
    USE SIGNAL ;
    PORT
      LAYER M4 ;
        RECT  21.408 15.504 21.6 15.528 ;
    END
  END o0[64]
  PIN o0[65]
    DIRECTION OUTPUT ;
    USE SIGNAL ;
    PORT
      LAYER M4 ;
        RECT  21.408 15.696 21.6 15.72 ;
    END
  END o0[65]
  PIN o0[66]
    DIRECTION OUTPUT ;
    USE SIGNAL ;
    PORT
      LAYER M4 ;
        RECT  21.408 15.888 21.6 15.912 ;
    END
  END o0[66]
  PIN o0[67]
    DIRECTION OUTPUT ;
    USE SIGNAL ;
    PORT
      LAYER M4 ;
        RECT  21.408 16.032 21.6 16.056 ;
    END
  END o0[67]
  PIN o0[68]
    DIRECTION OUTPUT ;
    USE SIGNAL ;
    PORT
      LAYER M4 ;
        RECT  21.408 16.368 21.6 16.392 ;
    END
  END o0[68]
  PIN o0[69]
    DIRECTION OUTPUT ;
    USE SIGNAL ;
    PORT
      LAYER M4 ;
        RECT  21.408 16.56 21.6 16.584 ;
    END
  END o0[69]
  PIN o0[6]
    DIRECTION OUTPUT ;
    USE SIGNAL ;
    PORT
      LAYER M4 ;
        RECT  21.408 5.568 21.6 5.592 ;
    END
  END o0[6]
  PIN o0[70]
    DIRECTION OUTPUT ;
    USE SIGNAL ;
    PORT
      LAYER M4 ;
        RECT  21.408 16.704 21.6 16.728 ;
    END
  END o0[70]
  PIN o0[71]
    DIRECTION OUTPUT ;
    USE SIGNAL ;
    PORT
      LAYER M4 ;
        RECT  21.408 16.896 21.6 16.92 ;
    END
  END o0[71]
  PIN o0[72]
    DIRECTION OUTPUT ;
    USE SIGNAL ;
    PORT
      LAYER M4 ;
        RECT  21.408 17.088 21.6 17.112 ;
    END
  END o0[72]
  PIN o0[73]
    DIRECTION OUTPUT ;
    USE SIGNAL ;
    PORT
      LAYER M4 ;
        RECT  21.408 17.232 21.6 17.256 ;
    END
  END o0[73]
  PIN o0[74]
    DIRECTION OUTPUT ;
    USE SIGNAL ;
    PORT
      LAYER M4 ;
        RECT  21.408 17.424 21.6 17.448 ;
    END
  END o0[74]
  PIN o0[75]
    DIRECTION OUTPUT ;
    USE SIGNAL ;
    PORT
      LAYER M4 ;
        RECT  21.408 17.568 21.6 17.592 ;
    END
  END o0[75]
  PIN o0[76]
    DIRECTION OUTPUT ;
    USE SIGNAL ;
    PORT
      LAYER M4 ;
        RECT  21.408 17.76 21.6 17.784 ;
    END
  END o0[76]
  PIN o0[77]
    DIRECTION OUTPUT ;
    USE SIGNAL ;
    PORT
      LAYER M4 ;
        RECT  21.408 17.952 21.6 17.976 ;
    END
  END o0[77]
  PIN o0[78]
    DIRECTION OUTPUT ;
    USE SIGNAL ;
    PORT
      LAYER M4 ;
        RECT  21.408 18.096 21.6 18.12 ;
    END
  END o0[78]
  PIN o0[79]
    DIRECTION OUTPUT ;
    USE SIGNAL ;
    PORT
      LAYER M4 ;
        RECT  21.408 18.288 21.6 18.312 ;
    END
  END o0[79]
  PIN o0[7]
    DIRECTION OUTPUT ;
    USE SIGNAL ;
    PORT
      LAYER M4 ;
        RECT  21.408 5.712 21.6 5.736 ;
    END
  END o0[7]
  PIN o0[80]
    DIRECTION OUTPUT ;
    USE SIGNAL ;
    PORT
      LAYER M4 ;
        RECT  21.408 18.432 21.6 18.456 ;
    END
  END o0[80]
  PIN o0[81]
    DIRECTION OUTPUT ;
    USE SIGNAL ;
    PORT
      LAYER M4 ;
        RECT  21.408 18.624 21.6 18.648 ;
    END
  END o0[81]
  PIN o0[82]
    DIRECTION OUTPUT ;
    USE SIGNAL ;
    PORT
      LAYER M4 ;
        RECT  21.408 18.768 21.6 18.792 ;
    END
  END o0[82]
  PIN o0[83]
    DIRECTION OUTPUT ;
    USE SIGNAL ;
    PORT
      LAYER M4 ;
        RECT  21.408 18.96 21.6 18.984 ;
    END
  END o0[83]
  PIN o0[84]
    DIRECTION OUTPUT ;
    USE SIGNAL ;
    PORT
      LAYER M4 ;
        RECT  21.408 19.152 21.6 19.176 ;
    END
  END o0[84]
  PIN o0[85]
    DIRECTION OUTPUT ;
    USE SIGNAL ;
    PORT
      LAYER M4 ;
        RECT  21.408 19.296 21.6 19.32 ;
    END
  END o0[85]
  PIN o0[86]
    DIRECTION OUTPUT ;
    USE SIGNAL ;
    PORT
      LAYER M4 ;
        RECT  21.408 19.488 21.6 19.512 ;
    END
  END o0[86]
  PIN o0[87]
    DIRECTION OUTPUT ;
    USE SIGNAL ;
    PORT
      LAYER M4 ;
        RECT  21.408 19.632 21.6 19.656 ;
    END
  END o0[87]
  PIN o0[88]
    DIRECTION OUTPUT ;
    USE SIGNAL ;
    PORT
      LAYER M4 ;
        RECT  21.408 19.824 21.6 19.848 ;
    END
  END o0[88]
  PIN o0[89]
    DIRECTION OUTPUT ;
    USE SIGNAL ;
    PORT
      LAYER M4 ;
        RECT  21.408 19.968 21.6 19.992 ;
    END
  END o0[89]
  PIN o0[8]
    DIRECTION OUTPUT ;
    USE SIGNAL ;
    PORT
      LAYER M4 ;
        RECT  21.408 5.904 21.6 5.928 ;
    END
  END o0[8]
  PIN o0[90]
    DIRECTION OUTPUT ;
    USE SIGNAL ;
    PORT
      LAYER M4 ;
        RECT  21.408 20.16 21.6 20.184 ;
    END
  END o0[90]
  PIN o0[91]
    DIRECTION OUTPUT ;
    USE SIGNAL ;
    PORT
      LAYER M4 ;
        RECT  21.408 20.352 21.6 20.376 ;
    END
  END o0[91]
  PIN o0[92]
    DIRECTION OUTPUT ;
    USE SIGNAL ;
    PORT
      LAYER M4 ;
        RECT  21.408 20.496 21.6 20.52 ;
    END
  END o0[92]
  PIN o0[93]
    DIRECTION OUTPUT ;
    USE SIGNAL ;
    PORT
      LAYER M4 ;
        RECT  21.408 20.688 21.6 20.712 ;
    END
  END o0[93]
  PIN o0[94]
    DIRECTION OUTPUT ;
    USE SIGNAL ;
    PORT
      LAYER M4 ;
        RECT  21.408 20.832 21.6 20.856 ;
    END
  END o0[94]
  PIN o0[95]
    DIRECTION OUTPUT ;
    USE SIGNAL ;
    PORT
      LAYER M4 ;
        RECT  21.408 21.024 21.6 21.048 ;
    END
  END o0[95]
  PIN o0[96]
    DIRECTION OUTPUT ;
    USE SIGNAL ;
    PORT
      LAYER M4 ;
        RECT  21.408 21.216 21.6 21.24 ;
    END
  END o0[96]
  PIN o0[97]
    DIRECTION OUTPUT ;
    USE SIGNAL ;
    PORT
      LAYER M4 ;
        RECT  21.408 21.36 21.6 21.384 ;
    END
  END o0[97]
  PIN o0[98]
    DIRECTION OUTPUT ;
    USE SIGNAL ;
    PORT
      LAYER M4 ;
        RECT  21.408 21.552 21.6 21.576 ;
    END
  END o0[98]
  PIN o0[99]
    DIRECTION OUTPUT ;
    USE SIGNAL ;
    PORT
      LAYER M4 ;
        RECT  21.408 21.696 21.6 21.72 ;
    END
  END o0[99]
  PIN o0[9]
    DIRECTION OUTPUT ;
    USE SIGNAL ;
    PORT
      LAYER M4 ;
        RECT  21.408 6.096 21.6 6.12 ;
    END
  END o0[9]
  PIN o1[0]
    DIRECTION OUTPUT ;
    USE SIGNAL ;
    PORT
      LAYER M4 ;
        RECT  21.408 28.272 21.6 28.296 ;
    END
  END o1[0]
  PIN o1[100]
    DIRECTION OUTPUT ;
    USE SIGNAL ;
    PORT
      LAYER M4 ;
        RECT  21.408 45.648 21.6 45.672 ;
    END
  END o1[100]
  PIN o1[101]
    DIRECTION OUTPUT ;
    USE SIGNAL ;
    PORT
      LAYER M4 ;
        RECT  21.408 45.792 21.6 45.816 ;
    END
  END o1[101]
  PIN o1[102]
    DIRECTION OUTPUT ;
    USE SIGNAL ;
    PORT
      LAYER M4 ;
        RECT  21.408 45.984 21.6 46.008 ;
    END
  END o1[102]
  PIN o1[103]
    DIRECTION OUTPUT ;
    USE SIGNAL ;
    PORT
      LAYER M4 ;
        RECT  21.408 46.176 21.6 46.2 ;
    END
  END o1[103]
  PIN o1[104]
    DIRECTION OUTPUT ;
    USE SIGNAL ;
    PORT
      LAYER M4 ;
        RECT  21.408 46.32 21.6 46.344 ;
    END
  END o1[104]
  PIN o1[105]
    DIRECTION OUTPUT ;
    USE SIGNAL ;
    PORT
      LAYER M4 ;
        RECT  21.408 46.512 21.6 46.536 ;
    END
  END o1[105]
  PIN o1[106]
    DIRECTION OUTPUT ;
    USE SIGNAL ;
    PORT
      LAYER M4 ;
        RECT  21.408 46.656 21.6 46.68 ;
    END
  END o1[106]
  PIN o1[107]
    DIRECTION OUTPUT ;
    USE SIGNAL ;
    PORT
      LAYER M4 ;
        RECT  21.408 46.848 21.6 46.872 ;
    END
  END o1[107]
  PIN o1[108]
    DIRECTION OUTPUT ;
    USE SIGNAL ;
    PORT
      LAYER M4 ;
        RECT  21.408 46.992 21.6 47.016 ;
    END
  END o1[108]
  PIN o1[109]
    DIRECTION OUTPUT ;
    USE SIGNAL ;
    PORT
      LAYER M4 ;
        RECT  21.408 47.184 21.6 47.208 ;
    END
  END o1[109]
  PIN o1[10]
    DIRECTION OUTPUT ;
    USE SIGNAL ;
    PORT
      LAYER M4 ;
        RECT  21.408 30 21.6 30.024 ;
    END
  END o1[10]
  PIN o1[110]
    DIRECTION OUTPUT ;
    USE SIGNAL ;
    PORT
      LAYER M4 ;
        RECT  21.408 47.376 21.6 47.4 ;
    END
  END o1[110]
  PIN o1[111]
    DIRECTION OUTPUT ;
    USE SIGNAL ;
    PORT
      LAYER M4 ;
        RECT  21.408 47.52 21.6 47.544 ;
    END
  END o1[111]
  PIN o1[112]
    DIRECTION OUTPUT ;
    USE SIGNAL ;
    PORT
      LAYER M4 ;
        RECT  21.408 47.712 21.6 47.736 ;
    END
  END o1[112]
  PIN o1[113]
    DIRECTION OUTPUT ;
    USE SIGNAL ;
    PORT
      LAYER M4 ;
        RECT  21.408 47.856 21.6 47.88 ;
    END
  END o1[113]
  PIN o1[114]
    DIRECTION OUTPUT ;
    USE SIGNAL ;
    PORT
      LAYER M4 ;
        RECT  21.408 48.048 21.6 48.072 ;
    END
  END o1[114]
  PIN o1[115]
    DIRECTION OUTPUT ;
    USE SIGNAL ;
    PORT
      LAYER M4 ;
        RECT  21.408 48.24 21.6 48.264 ;
    END
  END o1[115]
  PIN o1[116]
    DIRECTION OUTPUT ;
    USE SIGNAL ;
    PORT
      LAYER M4 ;
        RECT  21.408 48.384 21.6 48.408 ;
    END
  END o1[116]
  PIN o1[117]
    DIRECTION OUTPUT ;
    USE SIGNAL ;
    PORT
      LAYER M4 ;
        RECT  21.408 48.576 21.6 48.6 ;
    END
  END o1[117]
  PIN o1[118]
    DIRECTION OUTPUT ;
    USE SIGNAL ;
    PORT
      LAYER M4 ;
        RECT  21.408 48.72 21.6 48.744 ;
    END
  END o1[118]
  PIN o1[119]
    DIRECTION OUTPUT ;
    USE SIGNAL ;
    PORT
      LAYER M4 ;
        RECT  21.408 48.912 21.6 48.936 ;
    END
  END o1[119]
  PIN o1[11]
    DIRECTION OUTPUT ;
    USE SIGNAL ;
    PORT
      LAYER M4 ;
        RECT  21.408 30.192 21.6 30.216 ;
    END
  END o1[11]
  PIN o1[120]
    DIRECTION OUTPUT ;
    USE SIGNAL ;
    PORT
      LAYER M4 ;
        RECT  21.408 49.056 21.6 49.08 ;
    END
  END o1[120]
  PIN o1[121]
    DIRECTION OUTPUT ;
    USE SIGNAL ;
    PORT
      LAYER M4 ;
        RECT  21.408 49.248 21.6 49.272 ;
    END
  END o1[121]
  PIN o1[122]
    DIRECTION OUTPUT ;
    USE SIGNAL ;
    PORT
      LAYER M4 ;
        RECT  21.408 49.44 21.6 49.464 ;
    END
  END o1[122]
  PIN o1[123]
    DIRECTION OUTPUT ;
    USE SIGNAL ;
    PORT
      LAYER M4 ;
        RECT  21.408 49.584 21.6 49.608 ;
    END
  END o1[123]
  PIN o1[124]
    DIRECTION OUTPUT ;
    USE SIGNAL ;
    PORT
      LAYER M4 ;
        RECT  21.408 49.776 21.6 49.8 ;
    END
  END o1[124]
  PIN o1[125]
    DIRECTION OUTPUT ;
    USE SIGNAL ;
    PORT
      LAYER M4 ;
        RECT  21.408 49.92 21.6 49.944 ;
    END
  END o1[125]
  PIN o1[126]
    DIRECTION OUTPUT ;
    USE SIGNAL ;
    PORT
      LAYER M4 ;
        RECT  21.408 50.112 21.6 50.136 ;
    END
  END o1[126]
  PIN o1[127]
    DIRECTION OUTPUT ;
    USE SIGNAL ;
    PORT
      LAYER M4 ;
        RECT  21.408 50.256 21.6 50.28 ;
    END
  END o1[127]
  PIN o1[128]
    DIRECTION OUTPUT ;
    USE SIGNAL ;
    PORT
      LAYER M4 ;
        RECT  21.408 50.448 21.6 50.472 ;
    END
  END o1[128]
  PIN o1[129]
    DIRECTION OUTPUT ;
    USE SIGNAL ;
    PORT
      LAYER M4 ;
        RECT  21.408 50.64 21.6 50.664 ;
    END
  END o1[129]
  PIN o1[12]
    DIRECTION OUTPUT ;
    USE SIGNAL ;
    PORT
      LAYER M4 ;
        RECT  21.408 30.336 21.6 30.36 ;
    END
  END o1[12]
  PIN o1[130]
    DIRECTION OUTPUT ;
    USE SIGNAL ;
    PORT
      LAYER M4 ;
        RECT  21.408 50.784 21.6 50.808 ;
    END
  END o1[130]
  PIN o1[131]
    DIRECTION OUTPUT ;
    USE SIGNAL ;
    PORT
      LAYER M4 ;
        RECT  21.408 50.976 21.6 51 ;
    END
  END o1[131]
  PIN o1[132]
    DIRECTION OUTPUT ;
    USE SIGNAL ;
    PORT
      LAYER M4 ;
        RECT  21.408 51.12 21.6 51.144 ;
    END
  END o1[132]
  PIN o1[133]
    DIRECTION OUTPUT ;
    USE SIGNAL ;
    PORT
      LAYER M4 ;
        RECT  21.408 51.312 21.6 51.336 ;
    END
  END o1[133]
  PIN o1[134]
    DIRECTION OUTPUT ;
    USE SIGNAL ;
    PORT
      LAYER M4 ;
        RECT  21.408 51.504 21.6 51.528 ;
    END
  END o1[134]
  PIN o1[135]
    DIRECTION OUTPUT ;
    USE SIGNAL ;
    PORT
      LAYER M4 ;
        RECT  21.408 51.648 21.6 51.672 ;
    END
  END o1[135]
  PIN o1[13]
    DIRECTION OUTPUT ;
    USE SIGNAL ;
    PORT
      LAYER M4 ;
        RECT  21.408 30.528 21.6 30.552 ;
    END
  END o1[13]
  PIN o1[14]
    DIRECTION OUTPUT ;
    USE SIGNAL ;
    PORT
      LAYER M4 ;
        RECT  21.408 30.72 21.6 30.744 ;
    END
  END o1[14]
  PIN o1[15]
    DIRECTION OUTPUT ;
    USE SIGNAL ;
    PORT
      LAYER M4 ;
        RECT  21.408 30.864 21.6 30.888 ;
    END
  END o1[15]
  PIN o1[16]
    DIRECTION OUTPUT ;
    USE SIGNAL ;
    PORT
      LAYER M4 ;
        RECT  21.408 31.056 21.6 31.08 ;
    END
  END o1[16]
  PIN o1[17]
    DIRECTION OUTPUT ;
    USE SIGNAL ;
    PORT
      LAYER M4 ;
        RECT  21.408 31.2 21.6 31.224 ;
    END
  END o1[17]
  PIN o1[18]
    DIRECTION OUTPUT ;
    USE SIGNAL ;
    PORT
      LAYER M4 ;
        RECT  21.408 31.392 21.6 31.416 ;
    END
  END o1[18]
  PIN o1[19]
    DIRECTION OUTPUT ;
    USE SIGNAL ;
    PORT
      LAYER M4 ;
        RECT  21.408 31.536 21.6 31.56 ;
    END
  END o1[19]
  PIN o1[1]
    DIRECTION OUTPUT ;
    USE SIGNAL ;
    PORT
      LAYER M4 ;
        RECT  21.408 28.464 21.6 28.488 ;
    END
  END o1[1]
  PIN o1[20]
    DIRECTION OUTPUT ;
    USE SIGNAL ;
    PORT
      LAYER M4 ;
        RECT  21.408 31.728 21.6 31.752 ;
    END
  END o1[20]
  PIN o1[21]
    DIRECTION OUTPUT ;
    USE SIGNAL ;
    PORT
      LAYER M4 ;
        RECT  21.408 31.92 21.6 31.944 ;
    END
  END o1[21]
  PIN o1[22]
    DIRECTION OUTPUT ;
    USE SIGNAL ;
    PORT
      LAYER M4 ;
        RECT  21.408 32.064 21.6 32.088 ;
    END
  END o1[22]
  PIN o1[23]
    DIRECTION OUTPUT ;
    USE SIGNAL ;
    PORT
      LAYER M4 ;
        RECT  21.408 32.256 21.6 32.28 ;
    END
  END o1[23]
  PIN o1[24]
    DIRECTION OUTPUT ;
    USE SIGNAL ;
    PORT
      LAYER M4 ;
        RECT  21.408 32.4 21.6 32.424 ;
    END
  END o1[24]
  PIN o1[25]
    DIRECTION OUTPUT ;
    USE SIGNAL ;
    PORT
      LAYER M4 ;
        RECT  21.408 32.592 21.6 32.616 ;
    END
  END o1[25]
  PIN o1[26]
    DIRECTION OUTPUT ;
    USE SIGNAL ;
    PORT
      LAYER M4 ;
        RECT  21.408 32.736 21.6 32.76 ;
    END
  END o1[26]
  PIN o1[27]
    DIRECTION OUTPUT ;
    USE SIGNAL ;
    PORT
      LAYER M4 ;
        RECT  21.408 32.928 21.6 32.952 ;
    END
  END o1[27]
  PIN o1[28]
    DIRECTION OUTPUT ;
    USE SIGNAL ;
    PORT
      LAYER M4 ;
        RECT  21.408 33.12 21.6 33.144 ;
    END
  END o1[28]
  PIN o1[29]
    DIRECTION OUTPUT ;
    USE SIGNAL ;
    PORT
      LAYER M4 ;
        RECT  21.408 33.264 21.6 33.288 ;
    END
  END o1[29]
  PIN o1[2]
    DIRECTION OUTPUT ;
    USE SIGNAL ;
    PORT
      LAYER M4 ;
        RECT  21.408 28.656 21.6 28.68 ;
    END
  END o1[2]
  PIN o1[30]
    DIRECTION OUTPUT ;
    USE SIGNAL ;
    PORT
      LAYER M4 ;
        RECT  21.408 33.456 21.6 33.48 ;
    END
  END o1[30]
  PIN o1[31]
    DIRECTION OUTPUT ;
    USE SIGNAL ;
    PORT
      LAYER M4 ;
        RECT  21.408 33.6 21.6 33.624 ;
    END
  END o1[31]
  PIN o1[32]
    DIRECTION OUTPUT ;
    USE SIGNAL ;
    PORT
      LAYER M4 ;
        RECT  21.408 33.792 21.6 33.816 ;
    END
  END o1[32]
  PIN o1[33]
    DIRECTION OUTPUT ;
    USE SIGNAL ;
    PORT
      LAYER M4 ;
        RECT  21.408 33.984 21.6 34.008 ;
    END
  END o1[33]
  PIN o1[34]
    DIRECTION OUTPUT ;
    USE SIGNAL ;
    PORT
      LAYER M4 ;
        RECT  21.408 34.128 21.6 34.152 ;
    END
  END o1[34]
  PIN o1[35]
    DIRECTION OUTPUT ;
    USE SIGNAL ;
    PORT
      LAYER M4 ;
        RECT  21.408 34.32 21.6 34.344 ;
    END
  END o1[35]
  PIN o1[36]
    DIRECTION OUTPUT ;
    USE SIGNAL ;
    PORT
      LAYER M4 ;
        RECT  21.408 34.464 21.6 34.488 ;
    END
  END o1[36]
  PIN o1[37]
    DIRECTION OUTPUT ;
    USE SIGNAL ;
    PORT
      LAYER M4 ;
        RECT  21.408 34.656 21.6 34.68 ;
    END
  END o1[37]
  PIN o1[38]
    DIRECTION OUTPUT ;
    USE SIGNAL ;
    PORT
      LAYER M4 ;
        RECT  21.408 34.8 21.6 34.824 ;
    END
  END o1[38]
  PIN o1[39]
    DIRECTION OUTPUT ;
    USE SIGNAL ;
    PORT
      LAYER M4 ;
        RECT  21.408 34.992 21.6 35.016 ;
    END
  END o1[39]
  PIN o1[3]
    DIRECTION OUTPUT ;
    USE SIGNAL ;
    PORT
      LAYER M4 ;
        RECT  21.408 28.8 21.6 28.824 ;
    END
  END o1[3]
  PIN o1[40]
    DIRECTION OUTPUT ;
    USE SIGNAL ;
    PORT
      LAYER M4 ;
        RECT  21.408 35.184 21.6 35.208 ;
    END
  END o1[40]
  PIN o1[41]
    DIRECTION OUTPUT ;
    USE SIGNAL ;
    PORT
      LAYER M4 ;
        RECT  21.408 35.328 21.6 35.352 ;
    END
  END o1[41]
  PIN o1[42]
    DIRECTION OUTPUT ;
    USE SIGNAL ;
    PORT
      LAYER M4 ;
        RECT  21.408 35.52 21.6 35.544 ;
    END
  END o1[42]
  PIN o1[43]
    DIRECTION OUTPUT ;
    USE SIGNAL ;
    PORT
      LAYER M4 ;
        RECT  21.408 35.664 21.6 35.688 ;
    END
  END o1[43]
  PIN o1[44]
    DIRECTION OUTPUT ;
    USE SIGNAL ;
    PORT
      LAYER M4 ;
        RECT  21.408 35.856 21.6 35.88 ;
    END
  END o1[44]
  PIN o1[45]
    DIRECTION OUTPUT ;
    USE SIGNAL ;
    PORT
      LAYER M4 ;
        RECT  21.408 36 21.6 36.024 ;
    END
  END o1[45]
  PIN o1[46]
    DIRECTION OUTPUT ;
    USE SIGNAL ;
    PORT
      LAYER M4 ;
        RECT  21.408 36.192 21.6 36.216 ;
    END
  END o1[46]
  PIN o1[47]
    DIRECTION OUTPUT ;
    USE SIGNAL ;
    PORT
      LAYER M4 ;
        RECT  21.408 36.384 21.6 36.408 ;
    END
  END o1[47]
  PIN o1[48]
    DIRECTION OUTPUT ;
    USE SIGNAL ;
    PORT
      LAYER M4 ;
        RECT  21.408 36.528 21.6 36.552 ;
    END
  END o1[48]
  PIN o1[49]
    DIRECTION OUTPUT ;
    USE SIGNAL ;
    PORT
      LAYER M4 ;
        RECT  21.408 36.72 21.6 36.744 ;
    END
  END o1[49]
  PIN o1[4]
    DIRECTION OUTPUT ;
    USE SIGNAL ;
    PORT
      LAYER M4 ;
        RECT  21.408 28.992 21.6 29.016 ;
    END
  END o1[4]
  PIN o1[50]
    DIRECTION OUTPUT ;
    USE SIGNAL ;
    PORT
      LAYER M4 ;
        RECT  21.408 36.864 21.6 36.888 ;
    END
  END o1[50]
  PIN o1[51]
    DIRECTION OUTPUT ;
    USE SIGNAL ;
    PORT
      LAYER M4 ;
        RECT  21.408 37.056 21.6 37.08 ;
    END
  END o1[51]
  PIN o1[52]
    DIRECTION OUTPUT ;
    USE SIGNAL ;
    PORT
      LAYER M4 ;
        RECT  21.408 37.2 21.6 37.224 ;
    END
  END o1[52]
  PIN o1[53]
    DIRECTION OUTPUT ;
    USE SIGNAL ;
    PORT
      LAYER M4 ;
        RECT  21.408 37.392 21.6 37.416 ;
    END
  END o1[53]
  PIN o1[54]
    DIRECTION OUTPUT ;
    USE SIGNAL ;
    PORT
      LAYER M4 ;
        RECT  21.408 37.584 21.6 37.608 ;
    END
  END o1[54]
  PIN o1[55]
    DIRECTION OUTPUT ;
    USE SIGNAL ;
    PORT
      LAYER M4 ;
        RECT  21.408 37.728 21.6 37.752 ;
    END
  END o1[55]
  PIN o1[56]
    DIRECTION OUTPUT ;
    USE SIGNAL ;
    PORT
      LAYER M4 ;
        RECT  21.408 37.92 21.6 37.944 ;
    END
  END o1[56]
  PIN o1[57]
    DIRECTION OUTPUT ;
    USE SIGNAL ;
    PORT
      LAYER M4 ;
        RECT  21.408 38.064 21.6 38.088 ;
    END
  END o1[57]
  PIN o1[58]
    DIRECTION OUTPUT ;
    USE SIGNAL ;
    PORT
      LAYER M4 ;
        RECT  21.408 38.256 21.6 38.28 ;
    END
  END o1[58]
  PIN o1[59]
    DIRECTION OUTPUT ;
    USE SIGNAL ;
    PORT
      LAYER M4 ;
        RECT  21.408 38.448 21.6 38.472 ;
    END
  END o1[59]
  PIN o1[5]
    DIRECTION OUTPUT ;
    USE SIGNAL ;
    PORT
      LAYER M4 ;
        RECT  21.408 29.136 21.6 29.16 ;
    END
  END o1[5]
  PIN o1[60]
    DIRECTION OUTPUT ;
    USE SIGNAL ;
    PORT
      LAYER M4 ;
        RECT  21.408 38.592 21.6 38.616 ;
    END
  END o1[60]
  PIN o1[61]
    DIRECTION OUTPUT ;
    USE SIGNAL ;
    PORT
      LAYER M4 ;
        RECT  21.408 38.784 21.6 38.808 ;
    END
  END o1[61]
  PIN o1[62]
    DIRECTION OUTPUT ;
    USE SIGNAL ;
    PORT
      LAYER M4 ;
        RECT  21.408 38.928 21.6 38.952 ;
    END
  END o1[62]
  PIN o1[63]
    DIRECTION OUTPUT ;
    USE SIGNAL ;
    PORT
      LAYER M4 ;
        RECT  21.408 39.12 21.6 39.144 ;
    END
  END o1[63]
  PIN o1[64]
    DIRECTION OUTPUT ;
    USE SIGNAL ;
    PORT
      LAYER M4 ;
        RECT  21.408 39.264 21.6 39.288 ;
    END
  END o1[64]
  PIN o1[65]
    DIRECTION OUTPUT ;
    USE SIGNAL ;
    PORT
      LAYER M4 ;
        RECT  21.408 39.456 21.6 39.48 ;
    END
  END o1[65]
  PIN o1[66]
    DIRECTION OUTPUT ;
    USE SIGNAL ;
    PORT
      LAYER M4 ;
        RECT  21.408 39.648 21.6 39.672 ;
    END
  END o1[66]
  PIN o1[67]
    DIRECTION OUTPUT ;
    USE SIGNAL ;
    PORT
      LAYER M4 ;
        RECT  21.408 39.792 21.6 39.816 ;
    END
  END o1[67]
  PIN o1[68]
    DIRECTION OUTPUT ;
    USE SIGNAL ;
    PORT
      LAYER M4 ;
        RECT  21.408 40.128 21.6 40.152 ;
    END
  END o1[68]
  PIN o1[69]
    DIRECTION OUTPUT ;
    USE SIGNAL ;
    PORT
      LAYER M4 ;
        RECT  21.408 40.32 21.6 40.344 ;
    END
  END o1[69]
  PIN o1[6]
    DIRECTION OUTPUT ;
    USE SIGNAL ;
    PORT
      LAYER M4 ;
        RECT  21.408 29.328 21.6 29.352 ;
    END
  END o1[6]
  PIN o1[70]
    DIRECTION OUTPUT ;
    USE SIGNAL ;
    PORT
      LAYER M4 ;
        RECT  21.408 40.464 21.6 40.488 ;
    END
  END o1[70]
  PIN o1[71]
    DIRECTION OUTPUT ;
    USE SIGNAL ;
    PORT
      LAYER M4 ;
        RECT  21.408 40.656 21.6 40.68 ;
    END
  END o1[71]
  PIN o1[72]
    DIRECTION OUTPUT ;
    USE SIGNAL ;
    PORT
      LAYER M4 ;
        RECT  21.408 40.848 21.6 40.872 ;
    END
  END o1[72]
  PIN o1[73]
    DIRECTION OUTPUT ;
    USE SIGNAL ;
    PORT
      LAYER M4 ;
        RECT  21.408 40.992 21.6 41.016 ;
    END
  END o1[73]
  PIN o1[74]
    DIRECTION OUTPUT ;
    USE SIGNAL ;
    PORT
      LAYER M4 ;
        RECT  21.408 41.184 21.6 41.208 ;
    END
  END o1[74]
  PIN o1[75]
    DIRECTION OUTPUT ;
    USE SIGNAL ;
    PORT
      LAYER M4 ;
        RECT  21.408 41.328 21.6 41.352 ;
    END
  END o1[75]
  PIN o1[76]
    DIRECTION OUTPUT ;
    USE SIGNAL ;
    PORT
      LAYER M4 ;
        RECT  21.408 41.52 21.6 41.544 ;
    END
  END o1[76]
  PIN o1[77]
    DIRECTION OUTPUT ;
    USE SIGNAL ;
    PORT
      LAYER M4 ;
        RECT  21.408 41.712 21.6 41.736 ;
    END
  END o1[77]
  PIN o1[78]
    DIRECTION OUTPUT ;
    USE SIGNAL ;
    PORT
      LAYER M4 ;
        RECT  21.408 41.856 21.6 41.88 ;
    END
  END o1[78]
  PIN o1[79]
    DIRECTION OUTPUT ;
    USE SIGNAL ;
    PORT
      LAYER M4 ;
        RECT  21.408 42.048 21.6 42.072 ;
    END
  END o1[79]
  PIN o1[7]
    DIRECTION OUTPUT ;
    USE SIGNAL ;
    PORT
      LAYER M4 ;
        RECT  21.408 29.472 21.6 29.496 ;
    END
  END o1[7]
  PIN o1[80]
    DIRECTION OUTPUT ;
    USE SIGNAL ;
    PORT
      LAYER M4 ;
        RECT  21.408 42.192 21.6 42.216 ;
    END
  END o1[80]
  PIN o1[81]
    DIRECTION OUTPUT ;
    USE SIGNAL ;
    PORT
      LAYER M4 ;
        RECT  21.408 42.384 21.6 42.408 ;
    END
  END o1[81]
  PIN o1[82]
    DIRECTION OUTPUT ;
    USE SIGNAL ;
    PORT
      LAYER M4 ;
        RECT  21.408 42.528 21.6 42.552 ;
    END
  END o1[82]
  PIN o1[83]
    DIRECTION OUTPUT ;
    USE SIGNAL ;
    PORT
      LAYER M4 ;
        RECT  21.408 42.72 21.6 42.744 ;
    END
  END o1[83]
  PIN o1[84]
    DIRECTION OUTPUT ;
    USE SIGNAL ;
    PORT
      LAYER M4 ;
        RECT  21.408 42.912 21.6 42.936 ;
    END
  END o1[84]
  PIN o1[85]
    DIRECTION OUTPUT ;
    USE SIGNAL ;
    PORT
      LAYER M4 ;
        RECT  21.408 43.056 21.6 43.08 ;
    END
  END o1[85]
  PIN o1[86]
    DIRECTION OUTPUT ;
    USE SIGNAL ;
    PORT
      LAYER M4 ;
        RECT  21.408 43.248 21.6 43.272 ;
    END
  END o1[86]
  PIN o1[87]
    DIRECTION OUTPUT ;
    USE SIGNAL ;
    PORT
      LAYER M4 ;
        RECT  21.408 43.392 21.6 43.416 ;
    END
  END o1[87]
  PIN o1[88]
    DIRECTION OUTPUT ;
    USE SIGNAL ;
    PORT
      LAYER M4 ;
        RECT  21.408 43.584 21.6 43.608 ;
    END
  END o1[88]
  PIN o1[89]
    DIRECTION OUTPUT ;
    USE SIGNAL ;
    PORT
      LAYER M4 ;
        RECT  21.408 43.728 21.6 43.752 ;
    END
  END o1[89]
  PIN o1[8]
    DIRECTION OUTPUT ;
    USE SIGNAL ;
    PORT
      LAYER M4 ;
        RECT  21.408 29.664 21.6 29.688 ;
    END
  END o1[8]
  PIN o1[90]
    DIRECTION OUTPUT ;
    USE SIGNAL ;
    PORT
      LAYER M4 ;
        RECT  21.408 43.92 21.6 43.944 ;
    END
  END o1[90]
  PIN o1[91]
    DIRECTION OUTPUT ;
    USE SIGNAL ;
    PORT
      LAYER M4 ;
        RECT  21.408 44.112 21.6 44.136 ;
    END
  END o1[91]
  PIN o1[92]
    DIRECTION OUTPUT ;
    USE SIGNAL ;
    PORT
      LAYER M4 ;
        RECT  21.408 44.256 21.6 44.28 ;
    END
  END o1[92]
  PIN o1[93]
    DIRECTION OUTPUT ;
    USE SIGNAL ;
    PORT
      LAYER M4 ;
        RECT  21.408 44.448 21.6 44.472 ;
    END
  END o1[93]
  PIN o1[94]
    DIRECTION OUTPUT ;
    USE SIGNAL ;
    PORT
      LAYER M4 ;
        RECT  21.408 44.592 21.6 44.616 ;
    END
  END o1[94]
  PIN o1[95]
    DIRECTION OUTPUT ;
    USE SIGNAL ;
    PORT
      LAYER M4 ;
        RECT  21.408 44.784 21.6 44.808 ;
    END
  END o1[95]
  PIN o1[96]
    DIRECTION OUTPUT ;
    USE SIGNAL ;
    PORT
      LAYER M4 ;
        RECT  21.408 44.976 21.6 45 ;
    END
  END o1[96]
  PIN o1[97]
    DIRECTION OUTPUT ;
    USE SIGNAL ;
    PORT
      LAYER M4 ;
        RECT  21.408 45.12 21.6 45.144 ;
    END
  END o1[97]
  PIN o1[98]
    DIRECTION OUTPUT ;
    USE SIGNAL ;
    PORT
      LAYER M4 ;
        RECT  21.408 45.312 21.6 45.336 ;
    END
  END o1[98]
  PIN o1[99]
    DIRECTION OUTPUT ;
    USE SIGNAL ;
    PORT
      LAYER M4 ;
        RECT  21.408 45.456 21.6 45.48 ;
    END
  END o1[99]
  PIN o1[9]
    DIRECTION OUTPUT ;
    USE SIGNAL ;
    PORT
      LAYER M4 ;
        RECT  21.408 29.856 21.6 29.88 ;
    END
  END o1[9]
  PIN o2[0]
    DIRECTION OUTPUT ;
    USE SIGNAL ;
    PORT
      LAYER M4 ;
        RECT  0 28.272 0.192 28.296 ;
    END
  END o2[0]
  PIN o2[100]
    DIRECTION OUTPUT ;
    USE SIGNAL ;
    PORT
      LAYER M4 ;
        RECT  0 45.648 0.192 45.672 ;
    END
  END o2[100]
  PIN o2[101]
    DIRECTION OUTPUT ;
    USE SIGNAL ;
    PORT
      LAYER M4 ;
        RECT  0 45.792 0.192 45.816 ;
    END
  END o2[101]
  PIN o2[102]
    DIRECTION OUTPUT ;
    USE SIGNAL ;
    PORT
      LAYER M4 ;
        RECT  0 45.984 0.192 46.008 ;
    END
  END o2[102]
  PIN o2[103]
    DIRECTION OUTPUT ;
    USE SIGNAL ;
    PORT
      LAYER M4 ;
        RECT  0 46.176 0.192 46.2 ;
    END
  END o2[103]
  PIN o2[104]
    DIRECTION OUTPUT ;
    USE SIGNAL ;
    PORT
      LAYER M4 ;
        RECT  0 46.32 0.192 46.344 ;
    END
  END o2[104]
  PIN o2[105]
    DIRECTION OUTPUT ;
    USE SIGNAL ;
    PORT
      LAYER M4 ;
        RECT  0 46.512 0.192 46.536 ;
    END
  END o2[105]
  PIN o2[106]
    DIRECTION OUTPUT ;
    USE SIGNAL ;
    PORT
      LAYER M4 ;
        RECT  0 46.656 0.192 46.68 ;
    END
  END o2[106]
  PIN o2[107]
    DIRECTION OUTPUT ;
    USE SIGNAL ;
    PORT
      LAYER M4 ;
        RECT  0 46.848 0.192 46.872 ;
    END
  END o2[107]
  PIN o2[108]
    DIRECTION OUTPUT ;
    USE SIGNAL ;
    PORT
      LAYER M4 ;
        RECT  0 46.992 0.192 47.016 ;
    END
  END o2[108]
  PIN o2[109]
    DIRECTION OUTPUT ;
    USE SIGNAL ;
    PORT
      LAYER M4 ;
        RECT  0 47.184 0.192 47.208 ;
    END
  END o2[109]
  PIN o2[10]
    DIRECTION OUTPUT ;
    USE SIGNAL ;
    PORT
      LAYER M4 ;
        RECT  0 30 0.192 30.024 ;
    END
  END o2[10]
  PIN o2[110]
    DIRECTION OUTPUT ;
    USE SIGNAL ;
    PORT
      LAYER M4 ;
        RECT  0 47.376 0.192 47.4 ;
    END
  END o2[110]
  PIN o2[111]
    DIRECTION OUTPUT ;
    USE SIGNAL ;
    PORT
      LAYER M4 ;
        RECT  0 47.52 0.192 47.544 ;
    END
  END o2[111]
  PIN o2[112]
    DIRECTION OUTPUT ;
    USE SIGNAL ;
    PORT
      LAYER M4 ;
        RECT  0 47.712 0.192 47.736 ;
    END
  END o2[112]
  PIN o2[113]
    DIRECTION OUTPUT ;
    USE SIGNAL ;
    PORT
      LAYER M4 ;
        RECT  0 47.856 0.192 47.88 ;
    END
  END o2[113]
  PIN o2[114]
    DIRECTION OUTPUT ;
    USE SIGNAL ;
    PORT
      LAYER M4 ;
        RECT  0 48.048 0.192 48.072 ;
    END
  END o2[114]
  PIN o2[115]
    DIRECTION OUTPUT ;
    USE SIGNAL ;
    PORT
      LAYER M4 ;
        RECT  0 48.24 0.192 48.264 ;
    END
  END o2[115]
  PIN o2[116]
    DIRECTION OUTPUT ;
    USE SIGNAL ;
    PORT
      LAYER M4 ;
        RECT  0 48.384 0.192 48.408 ;
    END
  END o2[116]
  PIN o2[117]
    DIRECTION OUTPUT ;
    USE SIGNAL ;
    PORT
      LAYER M4 ;
        RECT  0 48.576 0.192 48.6 ;
    END
  END o2[117]
  PIN o2[118]
    DIRECTION OUTPUT ;
    USE SIGNAL ;
    PORT
      LAYER M4 ;
        RECT  0 48.72 0.192 48.744 ;
    END
  END o2[118]
  PIN o2[119]
    DIRECTION OUTPUT ;
    USE SIGNAL ;
    PORT
      LAYER M4 ;
        RECT  0 48.912 0.192 48.936 ;
    END
  END o2[119]
  PIN o2[11]
    DIRECTION OUTPUT ;
    USE SIGNAL ;
    PORT
      LAYER M4 ;
        RECT  0 30.192 0.192 30.216 ;
    END
  END o2[11]
  PIN o2[120]
    DIRECTION OUTPUT ;
    USE SIGNAL ;
    PORT
      LAYER M4 ;
        RECT  0 49.056 0.192 49.08 ;
    END
  END o2[120]
  PIN o2[121]
    DIRECTION OUTPUT ;
    USE SIGNAL ;
    PORT
      LAYER M4 ;
        RECT  0 49.248 0.192 49.272 ;
    END
  END o2[121]
  PIN o2[122]
    DIRECTION OUTPUT ;
    USE SIGNAL ;
    PORT
      LAYER M4 ;
        RECT  0 49.44 0.192 49.464 ;
    END
  END o2[122]
  PIN o2[123]
    DIRECTION OUTPUT ;
    USE SIGNAL ;
    PORT
      LAYER M4 ;
        RECT  0 49.584 0.192 49.608 ;
    END
  END o2[123]
  PIN o2[124]
    DIRECTION OUTPUT ;
    USE SIGNAL ;
    PORT
      LAYER M4 ;
        RECT  0 49.776 0.192 49.8 ;
    END
  END o2[124]
  PIN o2[125]
    DIRECTION OUTPUT ;
    USE SIGNAL ;
    PORT
      LAYER M4 ;
        RECT  0 49.92 0.192 49.944 ;
    END
  END o2[125]
  PIN o2[126]
    DIRECTION OUTPUT ;
    USE SIGNAL ;
    PORT
      LAYER M4 ;
        RECT  0 50.112 0.192 50.136 ;
    END
  END o2[126]
  PIN o2[127]
    DIRECTION OUTPUT ;
    USE SIGNAL ;
    PORT
      LAYER M4 ;
        RECT  0 50.256 0.192 50.28 ;
    END
  END o2[127]
  PIN o2[128]
    DIRECTION OUTPUT ;
    USE SIGNAL ;
    PORT
      LAYER M4 ;
        RECT  0 50.448 0.192 50.472 ;
    END
  END o2[128]
  PIN o2[129]
    DIRECTION OUTPUT ;
    USE SIGNAL ;
    PORT
      LAYER M4 ;
        RECT  0 50.64 0.192 50.664 ;
    END
  END o2[129]
  PIN o2[12]
    DIRECTION OUTPUT ;
    USE SIGNAL ;
    PORT
      LAYER M4 ;
        RECT  0 30.336 0.192 30.36 ;
    END
  END o2[12]
  PIN o2[130]
    DIRECTION OUTPUT ;
    USE SIGNAL ;
    PORT
      LAYER M4 ;
        RECT  0 50.784 0.192 50.808 ;
    END
  END o2[130]
  PIN o2[131]
    DIRECTION OUTPUT ;
    USE SIGNAL ;
    PORT
      LAYER M4 ;
        RECT  0 50.976 0.192 51 ;
    END
  END o2[131]
  PIN o2[132]
    DIRECTION OUTPUT ;
    USE SIGNAL ;
    PORT
      LAYER M4 ;
        RECT  0 51.12 0.192 51.144 ;
    END
  END o2[132]
  PIN o2[133]
    DIRECTION OUTPUT ;
    USE SIGNAL ;
    PORT
      LAYER M4 ;
        RECT  0 51.312 0.192 51.336 ;
    END
  END o2[133]
  PIN o2[134]
    DIRECTION OUTPUT ;
    USE SIGNAL ;
    PORT
      LAYER M4 ;
        RECT  0 51.504 0.192 51.528 ;
    END
  END o2[134]
  PIN o2[135]
    DIRECTION OUTPUT ;
    USE SIGNAL ;
    PORT
      LAYER M4 ;
        RECT  0 51.648 0.192 51.672 ;
    END
  END o2[135]
  PIN o2[13]
    DIRECTION OUTPUT ;
    USE SIGNAL ;
    PORT
      LAYER M4 ;
        RECT  0 30.528 0.192 30.552 ;
    END
  END o2[13]
  PIN o2[14]
    DIRECTION OUTPUT ;
    USE SIGNAL ;
    PORT
      LAYER M4 ;
        RECT  0 30.72 0.192 30.744 ;
    END
  END o2[14]
  PIN o2[15]
    DIRECTION OUTPUT ;
    USE SIGNAL ;
    PORT
      LAYER M4 ;
        RECT  0 30.864 0.192 30.888 ;
    END
  END o2[15]
  PIN o2[16]
    DIRECTION OUTPUT ;
    USE SIGNAL ;
    PORT
      LAYER M4 ;
        RECT  0 31.056 0.192 31.08 ;
    END
  END o2[16]
  PIN o2[17]
    DIRECTION OUTPUT ;
    USE SIGNAL ;
    PORT
      LAYER M4 ;
        RECT  0 31.2 0.192 31.224 ;
    END
  END o2[17]
  PIN o2[18]
    DIRECTION OUTPUT ;
    USE SIGNAL ;
    PORT
      LAYER M4 ;
        RECT  0 31.392 0.192 31.416 ;
    END
  END o2[18]
  PIN o2[19]
    DIRECTION OUTPUT ;
    USE SIGNAL ;
    PORT
      LAYER M4 ;
        RECT  0 31.536 0.192 31.56 ;
    END
  END o2[19]
  PIN o2[1]
    DIRECTION OUTPUT ;
    USE SIGNAL ;
    PORT
      LAYER M4 ;
        RECT  0 28.464 0.192 28.488 ;
    END
  END o2[1]
  PIN o2[20]
    DIRECTION OUTPUT ;
    USE SIGNAL ;
    PORT
      LAYER M4 ;
        RECT  0 31.728 0.192 31.752 ;
    END
  END o2[20]
  PIN o2[21]
    DIRECTION OUTPUT ;
    USE SIGNAL ;
    PORT
      LAYER M4 ;
        RECT  0 31.92 0.192 31.944 ;
    END
  END o2[21]
  PIN o2[22]
    DIRECTION OUTPUT ;
    USE SIGNAL ;
    PORT
      LAYER M4 ;
        RECT  0 32.064 0.192 32.088 ;
    END
  END o2[22]
  PIN o2[23]
    DIRECTION OUTPUT ;
    USE SIGNAL ;
    PORT
      LAYER M4 ;
        RECT  0 32.256 0.192 32.28 ;
    END
  END o2[23]
  PIN o2[24]
    DIRECTION OUTPUT ;
    USE SIGNAL ;
    PORT
      LAYER M4 ;
        RECT  0 32.4 0.192 32.424 ;
    END
  END o2[24]
  PIN o2[25]
    DIRECTION OUTPUT ;
    USE SIGNAL ;
    PORT
      LAYER M4 ;
        RECT  0 32.592 0.192 32.616 ;
    END
  END o2[25]
  PIN o2[26]
    DIRECTION OUTPUT ;
    USE SIGNAL ;
    PORT
      LAYER M4 ;
        RECT  0 32.736 0.192 32.76 ;
    END
  END o2[26]
  PIN o2[27]
    DIRECTION OUTPUT ;
    USE SIGNAL ;
    PORT
      LAYER M4 ;
        RECT  0 32.928 0.192 32.952 ;
    END
  END o2[27]
  PIN o2[28]
    DIRECTION OUTPUT ;
    USE SIGNAL ;
    PORT
      LAYER M4 ;
        RECT  0 33.12 0.192 33.144 ;
    END
  END o2[28]
  PIN o2[29]
    DIRECTION OUTPUT ;
    USE SIGNAL ;
    PORT
      LAYER M4 ;
        RECT  0 33.264 0.192 33.288 ;
    END
  END o2[29]
  PIN o2[2]
    DIRECTION OUTPUT ;
    USE SIGNAL ;
    PORT
      LAYER M4 ;
        RECT  0 28.656 0.192 28.68 ;
    END
  END o2[2]
  PIN o2[30]
    DIRECTION OUTPUT ;
    USE SIGNAL ;
    PORT
      LAYER M4 ;
        RECT  0 33.456 0.192 33.48 ;
    END
  END o2[30]
  PIN o2[31]
    DIRECTION OUTPUT ;
    USE SIGNAL ;
    PORT
      LAYER M4 ;
        RECT  0 33.6 0.192 33.624 ;
    END
  END o2[31]
  PIN o2[32]
    DIRECTION OUTPUT ;
    USE SIGNAL ;
    PORT
      LAYER M4 ;
        RECT  0 33.792 0.192 33.816 ;
    END
  END o2[32]
  PIN o2[33]
    DIRECTION OUTPUT ;
    USE SIGNAL ;
    PORT
      LAYER M4 ;
        RECT  0 33.984 0.192 34.008 ;
    END
  END o2[33]
  PIN o2[34]
    DIRECTION OUTPUT ;
    USE SIGNAL ;
    PORT
      LAYER M4 ;
        RECT  0 34.128 0.192 34.152 ;
    END
  END o2[34]
  PIN o2[35]
    DIRECTION OUTPUT ;
    USE SIGNAL ;
    PORT
      LAYER M4 ;
        RECT  0 34.32 0.192 34.344 ;
    END
  END o2[35]
  PIN o2[36]
    DIRECTION OUTPUT ;
    USE SIGNAL ;
    PORT
      LAYER M4 ;
        RECT  0 34.464 0.192 34.488 ;
    END
  END o2[36]
  PIN o2[37]
    DIRECTION OUTPUT ;
    USE SIGNAL ;
    PORT
      LAYER M4 ;
        RECT  0 34.656 0.192 34.68 ;
    END
  END o2[37]
  PIN o2[38]
    DIRECTION OUTPUT ;
    USE SIGNAL ;
    PORT
      LAYER M4 ;
        RECT  0 34.8 0.192 34.824 ;
    END
  END o2[38]
  PIN o2[39]
    DIRECTION OUTPUT ;
    USE SIGNAL ;
    PORT
      LAYER M4 ;
        RECT  0 34.992 0.192 35.016 ;
    END
  END o2[39]
  PIN o2[3]
    DIRECTION OUTPUT ;
    USE SIGNAL ;
    PORT
      LAYER M4 ;
        RECT  0 28.8 0.192 28.824 ;
    END
  END o2[3]
  PIN o2[40]
    DIRECTION OUTPUT ;
    USE SIGNAL ;
    PORT
      LAYER M4 ;
        RECT  0 35.184 0.192 35.208 ;
    END
  END o2[40]
  PIN o2[41]
    DIRECTION OUTPUT ;
    USE SIGNAL ;
    PORT
      LAYER M4 ;
        RECT  0 35.328 0.192 35.352 ;
    END
  END o2[41]
  PIN o2[42]
    DIRECTION OUTPUT ;
    USE SIGNAL ;
    PORT
      LAYER M4 ;
        RECT  0 35.52 0.192 35.544 ;
    END
  END o2[42]
  PIN o2[43]
    DIRECTION OUTPUT ;
    USE SIGNAL ;
    PORT
      LAYER M4 ;
        RECT  0 35.664 0.192 35.688 ;
    END
  END o2[43]
  PIN o2[44]
    DIRECTION OUTPUT ;
    USE SIGNAL ;
    PORT
      LAYER M4 ;
        RECT  0 35.856 0.192 35.88 ;
    END
  END o2[44]
  PIN o2[45]
    DIRECTION OUTPUT ;
    USE SIGNAL ;
    PORT
      LAYER M4 ;
        RECT  0 36 0.192 36.024 ;
    END
  END o2[45]
  PIN o2[46]
    DIRECTION OUTPUT ;
    USE SIGNAL ;
    PORT
      LAYER M4 ;
        RECT  0 36.192 0.192 36.216 ;
    END
  END o2[46]
  PIN o2[47]
    DIRECTION OUTPUT ;
    USE SIGNAL ;
    PORT
      LAYER M4 ;
        RECT  0 36.384 0.192 36.408 ;
    END
  END o2[47]
  PIN o2[48]
    DIRECTION OUTPUT ;
    USE SIGNAL ;
    PORT
      LAYER M4 ;
        RECT  0 36.528 0.192 36.552 ;
    END
  END o2[48]
  PIN o2[49]
    DIRECTION OUTPUT ;
    USE SIGNAL ;
    PORT
      LAYER M4 ;
        RECT  0 36.72 0.192 36.744 ;
    END
  END o2[49]
  PIN o2[4]
    DIRECTION OUTPUT ;
    USE SIGNAL ;
    PORT
      LAYER M4 ;
        RECT  0 28.992 0.192 29.016 ;
    END
  END o2[4]
  PIN o2[50]
    DIRECTION OUTPUT ;
    USE SIGNAL ;
    PORT
      LAYER M4 ;
        RECT  0 36.864 0.192 36.888 ;
    END
  END o2[50]
  PIN o2[51]
    DIRECTION OUTPUT ;
    USE SIGNAL ;
    PORT
      LAYER M4 ;
        RECT  0 37.056 0.192 37.08 ;
    END
  END o2[51]
  PIN o2[52]
    DIRECTION OUTPUT ;
    USE SIGNAL ;
    PORT
      LAYER M4 ;
        RECT  0 37.2 0.192 37.224 ;
    END
  END o2[52]
  PIN o2[53]
    DIRECTION OUTPUT ;
    USE SIGNAL ;
    PORT
      LAYER M4 ;
        RECT  0 37.392 0.192 37.416 ;
    END
  END o2[53]
  PIN o2[54]
    DIRECTION OUTPUT ;
    USE SIGNAL ;
    PORT
      LAYER M4 ;
        RECT  0 37.584 0.192 37.608 ;
    END
  END o2[54]
  PIN o2[55]
    DIRECTION OUTPUT ;
    USE SIGNAL ;
    PORT
      LAYER M4 ;
        RECT  0 37.728 0.192 37.752 ;
    END
  END o2[55]
  PIN o2[56]
    DIRECTION OUTPUT ;
    USE SIGNAL ;
    PORT
      LAYER M4 ;
        RECT  0 37.92 0.192 37.944 ;
    END
  END o2[56]
  PIN o2[57]
    DIRECTION OUTPUT ;
    USE SIGNAL ;
    PORT
      LAYER M4 ;
        RECT  0 38.064 0.192 38.088 ;
    END
  END o2[57]
  PIN o2[58]
    DIRECTION OUTPUT ;
    USE SIGNAL ;
    PORT
      LAYER M4 ;
        RECT  0 38.256 0.192 38.28 ;
    END
  END o2[58]
  PIN o2[59]
    DIRECTION OUTPUT ;
    USE SIGNAL ;
    PORT
      LAYER M4 ;
        RECT  0 38.448 0.192 38.472 ;
    END
  END o2[59]
  PIN o2[5]
    DIRECTION OUTPUT ;
    USE SIGNAL ;
    PORT
      LAYER M4 ;
        RECT  0 29.136 0.192 29.16 ;
    END
  END o2[5]
  PIN o2[60]
    DIRECTION OUTPUT ;
    USE SIGNAL ;
    PORT
      LAYER M4 ;
        RECT  0 38.592 0.192 38.616 ;
    END
  END o2[60]
  PIN o2[61]
    DIRECTION OUTPUT ;
    USE SIGNAL ;
    PORT
      LAYER M4 ;
        RECT  0 38.784 0.192 38.808 ;
    END
  END o2[61]
  PIN o2[62]
    DIRECTION OUTPUT ;
    USE SIGNAL ;
    PORT
      LAYER M4 ;
        RECT  0 38.928 0.192 38.952 ;
    END
  END o2[62]
  PIN o2[63]
    DIRECTION OUTPUT ;
    USE SIGNAL ;
    PORT
      LAYER M4 ;
        RECT  0 39.12 0.192 39.144 ;
    END
  END o2[63]
  PIN o2[64]
    DIRECTION OUTPUT ;
    USE SIGNAL ;
    PORT
      LAYER M4 ;
        RECT  0 39.264 0.192 39.288 ;
    END
  END o2[64]
  PIN o2[65]
    DIRECTION OUTPUT ;
    USE SIGNAL ;
    PORT
      LAYER M4 ;
        RECT  0 39.456 0.192 39.48 ;
    END
  END o2[65]
  PIN o2[66]
    DIRECTION OUTPUT ;
    USE SIGNAL ;
    PORT
      LAYER M4 ;
        RECT  0 39.648 0.192 39.672 ;
    END
  END o2[66]
  PIN o2[67]
    DIRECTION OUTPUT ;
    USE SIGNAL ;
    PORT
      LAYER M4 ;
        RECT  0 39.792 0.192 39.816 ;
    END
  END o2[67]
  PIN o2[68]
    DIRECTION OUTPUT ;
    USE SIGNAL ;
    PORT
      LAYER M4 ;
        RECT  0 40.128 0.192 40.152 ;
    END
  END o2[68]
  PIN o2[69]
    DIRECTION OUTPUT ;
    USE SIGNAL ;
    PORT
      LAYER M4 ;
        RECT  0 40.32 0.192 40.344 ;
    END
  END o2[69]
  PIN o2[6]
    DIRECTION OUTPUT ;
    USE SIGNAL ;
    PORT
      LAYER M4 ;
        RECT  0 29.328 0.192 29.352 ;
    END
  END o2[6]
  PIN o2[70]
    DIRECTION OUTPUT ;
    USE SIGNAL ;
    PORT
      LAYER M4 ;
        RECT  0 40.464 0.192 40.488 ;
    END
  END o2[70]
  PIN o2[71]
    DIRECTION OUTPUT ;
    USE SIGNAL ;
    PORT
      LAYER M4 ;
        RECT  0 40.656 0.192 40.68 ;
    END
  END o2[71]
  PIN o2[72]
    DIRECTION OUTPUT ;
    USE SIGNAL ;
    PORT
      LAYER M4 ;
        RECT  0 40.848 0.192 40.872 ;
    END
  END o2[72]
  PIN o2[73]
    DIRECTION OUTPUT ;
    USE SIGNAL ;
    PORT
      LAYER M4 ;
        RECT  0 40.992 0.192 41.016 ;
    END
  END o2[73]
  PIN o2[74]
    DIRECTION OUTPUT ;
    USE SIGNAL ;
    PORT
      LAYER M4 ;
        RECT  0 41.184 0.192 41.208 ;
    END
  END o2[74]
  PIN o2[75]
    DIRECTION OUTPUT ;
    USE SIGNAL ;
    PORT
      LAYER M4 ;
        RECT  0 41.328 0.192 41.352 ;
    END
  END o2[75]
  PIN o2[76]
    DIRECTION OUTPUT ;
    USE SIGNAL ;
    PORT
      LAYER M4 ;
        RECT  0 41.52 0.192 41.544 ;
    END
  END o2[76]
  PIN o2[77]
    DIRECTION OUTPUT ;
    USE SIGNAL ;
    PORT
      LAYER M4 ;
        RECT  0 41.712 0.192 41.736 ;
    END
  END o2[77]
  PIN o2[78]
    DIRECTION OUTPUT ;
    USE SIGNAL ;
    PORT
      LAYER M4 ;
        RECT  0 41.856 0.192 41.88 ;
    END
  END o2[78]
  PIN o2[79]
    DIRECTION OUTPUT ;
    USE SIGNAL ;
    PORT
      LAYER M4 ;
        RECT  0 42.048 0.192 42.072 ;
    END
  END o2[79]
  PIN o2[7]
    DIRECTION OUTPUT ;
    USE SIGNAL ;
    PORT
      LAYER M4 ;
        RECT  0 29.472 0.192 29.496 ;
    END
  END o2[7]
  PIN o2[80]
    DIRECTION OUTPUT ;
    USE SIGNAL ;
    PORT
      LAYER M4 ;
        RECT  0 42.192 0.192 42.216 ;
    END
  END o2[80]
  PIN o2[81]
    DIRECTION OUTPUT ;
    USE SIGNAL ;
    PORT
      LAYER M4 ;
        RECT  0 42.384 0.192 42.408 ;
    END
  END o2[81]
  PIN o2[82]
    DIRECTION OUTPUT ;
    USE SIGNAL ;
    PORT
      LAYER M4 ;
        RECT  0 42.528 0.192 42.552 ;
    END
  END o2[82]
  PIN o2[83]
    DIRECTION OUTPUT ;
    USE SIGNAL ;
    PORT
      LAYER M4 ;
        RECT  0 42.72 0.192 42.744 ;
    END
  END o2[83]
  PIN o2[84]
    DIRECTION OUTPUT ;
    USE SIGNAL ;
    PORT
      LAYER M4 ;
        RECT  0 42.912 0.192 42.936 ;
    END
  END o2[84]
  PIN o2[85]
    DIRECTION OUTPUT ;
    USE SIGNAL ;
    PORT
      LAYER M4 ;
        RECT  0 43.056 0.192 43.08 ;
    END
  END o2[85]
  PIN o2[86]
    DIRECTION OUTPUT ;
    USE SIGNAL ;
    PORT
      LAYER M4 ;
        RECT  0 43.248 0.192 43.272 ;
    END
  END o2[86]
  PIN o2[87]
    DIRECTION OUTPUT ;
    USE SIGNAL ;
    PORT
      LAYER M4 ;
        RECT  0 43.392 0.192 43.416 ;
    END
  END o2[87]
  PIN o2[88]
    DIRECTION OUTPUT ;
    USE SIGNAL ;
    PORT
      LAYER M4 ;
        RECT  0 43.584 0.192 43.608 ;
    END
  END o2[88]
  PIN o2[89]
    DIRECTION OUTPUT ;
    USE SIGNAL ;
    PORT
      LAYER M4 ;
        RECT  0 43.728 0.192 43.752 ;
    END
  END o2[89]
  PIN o2[8]
    DIRECTION OUTPUT ;
    USE SIGNAL ;
    PORT
      LAYER M4 ;
        RECT  0 29.664 0.192 29.688 ;
    END
  END o2[8]
  PIN o2[90]
    DIRECTION OUTPUT ;
    USE SIGNAL ;
    PORT
      LAYER M4 ;
        RECT  0 43.92 0.192 43.944 ;
    END
  END o2[90]
  PIN o2[91]
    DIRECTION OUTPUT ;
    USE SIGNAL ;
    PORT
      LAYER M4 ;
        RECT  0 44.112 0.192 44.136 ;
    END
  END o2[91]
  PIN o2[92]
    DIRECTION OUTPUT ;
    USE SIGNAL ;
    PORT
      LAYER M4 ;
        RECT  0 44.256 0.192 44.28 ;
    END
  END o2[92]
  PIN o2[93]
    DIRECTION OUTPUT ;
    USE SIGNAL ;
    PORT
      LAYER M4 ;
        RECT  0 44.448 0.192 44.472 ;
    END
  END o2[93]
  PIN o2[94]
    DIRECTION OUTPUT ;
    USE SIGNAL ;
    PORT
      LAYER M4 ;
        RECT  0 44.592 0.192 44.616 ;
    END
  END o2[94]
  PIN o2[95]
    DIRECTION OUTPUT ;
    USE SIGNAL ;
    PORT
      LAYER M4 ;
        RECT  0 44.784 0.192 44.808 ;
    END
  END o2[95]
  PIN o2[96]
    DIRECTION OUTPUT ;
    USE SIGNAL ;
    PORT
      LAYER M4 ;
        RECT  0 44.976 0.192 45 ;
    END
  END o2[96]
  PIN o2[97]
    DIRECTION OUTPUT ;
    USE SIGNAL ;
    PORT
      LAYER M4 ;
        RECT  0 45.12 0.192 45.144 ;
    END
  END o2[97]
  PIN o2[98]
    DIRECTION OUTPUT ;
    USE SIGNAL ;
    PORT
      LAYER M4 ;
        RECT  0 45.312 0.192 45.336 ;
    END
  END o2[98]
  PIN o2[99]
    DIRECTION OUTPUT ;
    USE SIGNAL ;
    PORT
      LAYER M4 ;
        RECT  0 45.456 0.192 45.48 ;
    END
  END o2[99]
  PIN o2[9]
    DIRECTION OUTPUT ;
    USE SIGNAL ;
    PORT
      LAYER M4 ;
        RECT  0 29.856 0.192 29.88 ;
    END
  END o2[9]
  PIN rs
    DIRECTION INPUT ;
    USE SIGNAL ;
    PORT
      LAYER M5 ;
        RECT  10.8 0 10.824 0.192 ;
    END
    PORT
      LAYER M5 ;
        RECT  10.8 0.144 10.824 1.763 ;
    END
  END rs
  PIN VDD
    DIRECTION INOUT ;
    USE POWER ;
    PORT
      LAYER M5 ;
        RECT  18.792 2.151 18.912 54.009 ;
        RECT  16.092 2.151 16.212 54.009 ;
        RECT  13.392 2.151 13.512 54.009 ;
        RECT  10.692 2.151 10.812 54.009 ;
        RECT  7.992 2.151 8.112 54.009 ;
        RECT  5.292 2.151 5.412 54.009 ;
        RECT  2.592 2.151 2.712 54.009 ;
    END
  END VDD
  PIN VSS
    DIRECTION INOUT ;
    USE GROUND ;
    PORT
      LAYER M5 ;
        RECT  18.6 2.137 18.72 54.023 ;
        RECT  15.9 2.137 16.02 54.023 ;
        RECT  13.2 2.137 13.32 54.023 ;
        RECT  10.5 2.137 10.62 54.023 ;
        RECT  7.8 2.137 7.92 54.023 ;
        RECT  5.1 2.137 5.22 54.023 ;
        RECT  2.4 2.137 2.52 54.023 ;
    END
  END VSS
  # OT_OBS_CLOSED layer=M5 d_um=1.536 added=66
  OBS
    LAYER RVTN ;
     RECT  2.16 2.16 19.44 2.295 ;
     RECT  2.16 2.565 19.44 2.835 ;
     RECT  2.16 3.105 19.44 3.375 ;
     RECT  2.16 3.645 19.44 3.915 ;
     RECT  2.16 4.185 19.44 4.455 ;
     RECT  2.16 4.725 19.44 4.995 ;
     RECT  2.16 5.265 19.44 5.535 ;
     RECT  2.16 5.805 19.44 6.075 ;
     RECT  2.16 6.345 19.44 6.615 ;
     RECT  2.16 6.885 19.44 7.155 ;
     RECT  2.16 7.425 19.44 7.695 ;
     RECT  2.16 7.965 19.44 8.235 ;
     RECT  2.16 8.505 19.44 8.775 ;
     RECT  2.16 9.045 19.44 9.315 ;
     RECT  2.16 9.585 19.44 9.855 ;
     RECT  2.16 10.125 19.44 10.395 ;
     RECT  2.16 10.665 19.44 10.935 ;
     RECT  2.16 11.205 19.44 11.475 ;
     RECT  2.16 11.745 19.44 12.015 ;
     RECT  2.16 12.285 19.44 12.555 ;
     RECT  2.16 12.825 19.44 13.095 ;
     RECT  2.16 13.365 19.44 13.635 ;
     RECT  2.16 13.905 19.44 14.175 ;
     RECT  2.16 14.445 19.44 14.715 ;
     RECT  2.16 14.985 19.44 15.255 ;
     RECT  2.16 15.525 19.44 15.795 ;
     RECT  2.16 16.065 19.44 16.335 ;
     RECT  2.16 16.605 19.44 16.875 ;
     RECT  2.16 17.145 19.44 17.415 ;
     RECT  2.16 17.685 19.44 17.955 ;
     RECT  2.16 18.225 19.44 18.495 ;
     RECT  2.16 18.765 19.44 19.035 ;
     RECT  2.16 19.305 19.44 19.575 ;
     RECT  2.16 19.845 19.44 20.115 ;
     RECT  2.16 20.385 19.44 20.655 ;
     RECT  2.16 20.925 19.44 21.195 ;
     RECT  2.16 21.465 19.44 21.735 ;
     RECT  2.16 22.005 19.44 22.275 ;
     RECT  2.16 22.545 19.44 22.815 ;
     RECT  2.16 23.085 19.44 23.355 ;
     RECT  2.16 23.625 19.44 23.895 ;
     RECT  2.16 24.165 19.44 24.435 ;
     RECT  2.16 24.705 19.44 24.975 ;
     RECT  2.16 25.245 19.44 25.515 ;
     RECT  2.16 25.785 19.44 26.055 ;
     RECT  2.16 26.325 19.44 26.595 ;
     RECT  2.16 26.865 19.44 27.135 ;
     RECT  2.16 27.405 19.44 27.675 ;
     RECT  2.16 27.945 19.44 28.215 ;
     RECT  2.16 28.485 19.44 28.755 ;
     RECT  2.16 29.025 19.44 29.295 ;
     RECT  2.16 29.565 19.44 29.835 ;
     RECT  2.16 30.105 19.44 30.375 ;
     RECT  2.16 30.645 19.44 30.915 ;
     RECT  2.16 31.185 19.44 31.455 ;
     RECT  2.16 31.725 19.44 31.995 ;
     RECT  2.16 32.265 19.44 32.535 ;
     RECT  2.16 32.805 19.44 33.075 ;
     RECT  2.16 33.345 19.44 33.615 ;
     RECT  2.16 33.885 19.44 34.155 ;
     RECT  2.16 34.425 19.44 34.695 ;
     RECT  2.16 34.965 19.44 35.235 ;
     RECT  2.16 35.505 19.44 35.775 ;
     RECT  2.16 36.045 19.44 36.315 ;
     RECT  2.16 36.585 19.44 36.855 ;
     RECT  2.16 37.125 19.44 37.395 ;
     RECT  2.16 37.665 19.44 37.935 ;
     RECT  2.16 38.205 19.44 38.475 ;
     RECT  2.16 38.745 19.44 39.015 ;
     RECT  2.16 39.285 19.44 39.555 ;
     RECT  2.16 39.825 19.44 40.095 ;
     RECT  2.16 40.365 19.44 40.635 ;
     RECT  2.16 40.905 19.44 41.175 ;
     RECT  2.16 41.445 19.44 41.715 ;
     RECT  2.16 41.985 19.44 42.255 ;
     RECT  2.16 42.525 19.44 42.795 ;
     RECT  2.16 43.065 19.44 43.335 ;
     RECT  2.16 43.605 19.44 43.875 ;
     RECT  2.16 44.145 19.44 44.415 ;
     RECT  2.16 44.685 19.44 44.955 ;
     RECT  2.16 45.225 19.44 45.495 ;
     RECT  2.16 45.765 19.44 46.035 ;
     RECT  2.16 46.305 19.44 46.575 ;
     RECT  2.16 46.845 19.44 47.115 ;
     RECT  2.16 47.385 19.44 47.655 ;
     RECT  2.16 47.925 19.44 48.195 ;
     RECT  2.16 48.465 19.44 48.735 ;
     RECT  2.16 49.005 19.44 49.275 ;
     RECT  2.16 49.545 19.44 49.815 ;
     RECT  2.16 50.085 19.44 50.355 ;
     RECT  2.16 50.625 19.44 50.895 ;
     RECT  2.16 51.165 19.44 51.435 ;
     RECT  2.16 51.705 19.44 51.975 ;
     RECT  2.16 52.245 19.44 52.515 ;
     RECT  2.16 52.785 19.44 53.055 ;
     RECT  2.16 53.325 19.44 53.595 ;
     RECT  2.16 53.865 19.44 54 ;
    LAYER RVTP ;
     RECT  2.16 2.295 19.44 2.565 ;
     RECT  2.16 2.835 19.44 3.105 ;
     RECT  2.16 3.375 19.44 3.645 ;
     RECT  2.16 3.915 19.44 4.185 ;
     RECT  2.16 4.455 19.44 4.725 ;
     RECT  2.16 4.995 19.44 5.265 ;
     RECT  2.16 5.535 19.44 5.805 ;
     RECT  2.16 6.075 19.44 6.345 ;
     RECT  2.16 6.615 19.44 6.885 ;
     RECT  2.16 7.155 19.44 7.425 ;
     RECT  2.16 7.695 19.44 7.965 ;
     RECT  2.16 8.235 19.44 8.505 ;
     RECT  2.16 8.775 19.44 9.045 ;
     RECT  2.16 9.315 19.44 9.585 ;
     RECT  2.16 9.855 19.44 10.125 ;
     RECT  2.16 10.395 19.44 10.665 ;
     RECT  2.16 10.935 19.44 11.205 ;
     RECT  2.16 11.475 19.44 11.745 ;
     RECT  2.16 12.015 19.44 12.285 ;
     RECT  2.16 12.555 19.44 12.825 ;
     RECT  2.16 13.095 19.44 13.365 ;
     RECT  2.16 13.635 19.44 13.905 ;
     RECT  2.16 14.175 19.44 14.445 ;
     RECT  2.16 14.715 19.44 14.985 ;
     RECT  2.16 15.255 19.44 15.525 ;
     RECT  2.16 15.795 19.44 16.065 ;
     RECT  2.16 16.335 19.44 16.605 ;
     RECT  2.16 16.875 19.44 17.145 ;
     RECT  2.16 17.415 19.44 17.685 ;
     RECT  2.16 17.955 19.44 18.225 ;
     RECT  2.16 18.495 19.44 18.765 ;
     RECT  2.16 19.035 19.44 19.305 ;
     RECT  2.16 19.575 19.44 19.845 ;
     RECT  2.16 20.115 19.44 20.385 ;
     RECT  2.16 20.655 19.44 20.925 ;
     RECT  2.16 21.195 19.44 21.465 ;
     RECT  2.16 21.735 19.44 22.005 ;
     RECT  2.16 22.275 19.44 22.545 ;
     RECT  2.16 22.815 19.44 23.085 ;
     RECT  2.16 23.355 19.44 23.625 ;
     RECT  2.16 23.895 19.44 24.165 ;
     RECT  2.16 24.435 19.44 24.705 ;
     RECT  2.16 24.975 19.44 25.245 ;
     RECT  2.16 25.515 19.44 25.785 ;
     RECT  2.16 26.055 19.44 26.325 ;
     RECT  2.16 26.595 19.44 26.865 ;
     RECT  2.16 27.135 19.44 27.405 ;
     RECT  2.16 27.675 19.44 27.945 ;
     RECT  2.16 28.215 19.44 28.485 ;
     RECT  2.16 28.755 19.44 29.025 ;
     RECT  2.16 29.295 19.44 29.565 ;
     RECT  2.16 29.835 19.44 30.105 ;
     RECT  2.16 30.375 19.44 30.645 ;
     RECT  2.16 30.915 19.44 31.185 ;
     RECT  2.16 31.455 19.44 31.725 ;
     RECT  2.16 31.995 19.44 32.265 ;
     RECT  2.16 32.535 19.44 32.805 ;
     RECT  2.16 33.075 19.44 33.345 ;
     RECT  2.16 33.615 19.44 33.885 ;
     RECT  2.16 34.155 19.44 34.425 ;
     RECT  2.16 34.695 19.44 34.965 ;
     RECT  2.16 35.235 19.44 35.505 ;
     RECT  2.16 35.775 19.44 36.045 ;
     RECT  2.16 36.315 19.44 36.585 ;
     RECT  2.16 36.855 19.44 37.125 ;
     RECT  2.16 37.395 19.44 37.665 ;
     RECT  2.16 37.935 19.44 38.205 ;
     RECT  2.16 38.475 19.44 38.745 ;
     RECT  2.16 39.015 19.44 39.285 ;
     RECT  2.16 39.555 19.44 39.825 ;
     RECT  2.16 40.095 19.44 40.365 ;
     RECT  2.16 40.635 19.44 40.905 ;
     RECT  2.16 41.175 19.44 41.445 ;
     RECT  2.16 41.715 19.44 41.985 ;
     RECT  2.16 42.255 19.44 42.525 ;
     RECT  2.16 42.795 19.44 43.065 ;
     RECT  2.16 43.335 19.44 43.605 ;
     RECT  2.16 43.875 19.44 44.145 ;
     RECT  2.16 44.415 19.44 44.685 ;
     RECT  2.16 44.955 19.44 45.225 ;
     RECT  2.16 45.495 19.44 45.765 ;
     RECT  2.16 46.035 19.44 46.305 ;
     RECT  2.16 46.575 19.44 46.845 ;
     RECT  2.16 47.115 19.44 47.385 ;
     RECT  2.16 47.655 19.44 47.925 ;
     RECT  2.16 48.195 19.44 48.465 ;
     RECT  2.16 48.735 19.44 49.005 ;
     RECT  2.16 49.275 19.44 49.545 ;
     RECT  2.16 49.815 19.44 50.085 ;
     RECT  2.16 50.355 19.44 50.625 ;
     RECT  2.16 50.895 19.44 51.165 ;
     RECT  2.16 51.435 19.44 51.705 ;
     RECT  2.16 51.975 19.44 52.245 ;
     RECT  2.16 52.515 19.44 52.785 ;
     RECT  2.16 53.055 19.44 53.325 ;
     RECT  2.16 53.595 19.44 53.865 ;
    LAYER M1 ;
     RECT  2.16 2.151 19.44 54.009 ;
    LAYER M2 ;
     RECT  0.211 3.96 0.247 3.978 ;
     RECT  0.247 40.986 0.463 41.004 ;
     RECT  0.211 32.976 0.499 32.994 ;
     RECT  0.211 33.966 0.499 33.984 ;
     RECT  0.211 30.348 0.535 31.014 ;
     RECT  0.499 31.896 0.535 31.914 ;
     RECT  0.499 32.976 0.535 34.344 ;
     RECT  0.499 37.566 0.535 37.584 ;
     RECT  0.463 40.266 0.535 41.004 ;
     RECT  0.499 43.848 0.535 43.866 ;
     RECT  0.247 44.856 0.535 44.874 ;
     RECT  0.499 45.774 0.535 45.792 ;
     RECT  0.499 47.286 0.535 47.304 ;
     RECT  0.499 48.366 0.535 48.384 ;
     RECT  0.499 49.986 0.535 50.004 ;
     RECT  0.247 3.96 2.16 4.518 ;
     RECT  0.247 5.58 2.16 5.598 ;
     RECT  0.211 7.398 2.16 7.416 ;
     RECT  0.211 13.41 2.16 13.428 ;
     RECT  0.211 16.38 2.16 16.398 ;
     RECT  0.535 18.702 2.16 18.72 ;
     RECT  0.247 20.97 2.16 20.988 ;
     RECT  0.535 22.05 2.16 22.806 ;
     RECT  0.535 29.736 2.16 31.914 ;
     RECT  0.535 32.976 2.16 34.614 ;
     RECT  0.535 36.216 2.16 36.234 ;
     RECT  0.535 37.296 2.16 41.004 ;
     RECT  0.535 42.066 2.16 46.134 ;
     RECT  0.535 47.088 2.16 48.384 ;
     RECT  0.535 49.554 2.16 51.264 ;
     RECT  2.16 2.151 19.44 54.009 ;
     RECT  19.44 4.896 19.967 15.174 ;
     RECT  19.44 15.966 19.967 51.624 ;
     RECT  19.967 24.876 20.003 30.096 ;
     RECT  19.967 34.704 20.003 38.664 ;
     RECT  19.967 39.564 20.003 39.582 ;
     RECT  19.967 4.896 20.507 8.064 ;
     RECT  19.967 8.856 20.507 11.772 ;
     RECT  19.967 12.528 20.507 15.174 ;
     RECT  19.967 15.966 20.507 15.984 ;
     RECT  19.967 17.046 20.507 18.144 ;
     RECT  19.967 19.116 20.507 22.374 ;
     RECT  19.967 23.166 20.507 24.084 ;
     RECT  20.003 34.866 20.507 36.648 ;
     RECT  20.507 5.31 20.543 8.064 ;
     RECT  20.507 8.856 20.543 10.764 ;
     RECT  20.507 11.754 20.543 11.772 ;
     RECT  20.507 12.528 20.543 14.544 ;
     RECT  20.507 17.046 20.543 18.054 ;
     RECT  20.507 19.116 20.543 19.332 ;
     RECT  20.507 20.088 20.543 20.682 ;
     RECT  20.507 21.546 20.543 22.374 ;
     RECT  20.507 23.166 20.543 23.814 ;
     RECT  20.003 25.29 20.543 28.314 ;
     RECT  20.003 29.106 20.543 30.096 ;
     RECT  19.967 31.266 20.543 33.714 ;
     RECT  20.507 35.136 20.543 36.648 ;
     RECT  20.003 37.98 20.543 38.664 ;
     RECT  19.967 40.878 20.543 46.134 ;
     RECT  19.967 47.124 20.543 49.77 ;
     RECT  19.967 50.796 20.543 51.426 ;
     RECT  20.543 9.054 20.579 9.072 ;
     RECT  20.543 19.314 20.579 19.332 ;
     RECT  20.543 26.226 20.579 26.244 ;
     RECT  20.543 27.216 20.579 28.242 ;
     RECT  20.543 29.466 20.579 29.484 ;
     RECT  20.543 31.662 20.579 33.066 ;
     RECT  20.543 36.216 20.579 36.234 ;
     RECT  20.543 38.646 20.579 38.664 ;
     RECT  20.543 41.886 20.579 41.904 ;
     RECT  20.543 42.966 20.579 42.984 ;
     RECT  20.543 43.776 20.579 44.208 ;
     RECT  20.543 48.204 20.579 48.564 ;
     RECT  20.543 25.326 20.615 25.344 ;
     RECT  20.579 28.224 20.615 28.242 ;
     RECT  20.579 31.662 20.615 31.68 ;
     RECT  20.579 32.436 20.615 32.454 ;
     RECT  20.579 48.204 20.615 48.222 ;
    LAYER M3 ;
     RECT  10.44 1.723 10.458 2.143 ;
     RECT  10.44 2.143 10.605 2.263 ;
     RECT  2.415 2.143 2.505 2.413 ;
     RECT  5.115 2.143 5.205 2.413 ;
     RECT  7.815 2.143 7.905 2.413 ;
     RECT  10.224 2.263 10.605 2.413 ;
     RECT  13.215 2.143 13.305 2.413 ;
     RECT  15.915 2.143 16.005 2.413 ;
     RECT  18.615 2.143 18.705 2.413 ;
     RECT  2.415 2.413 2.697 3.685 ;
     RECT  2.304 3.685 2.697 3.721 ;
     RECT  10.224 2.413 10.797 4.145 ;
     RECT  4.068 4.117 4.086 4.153 ;
     RECT  2.304 3.721 2.898 4.189 ;
     RECT  0.216 3.955 0.234 4.225 ;
     RECT  18.615 2.413 18.897 4.225 ;
     RECT  2.304 4.189 3.222 4.261 ;
     RECT  4.068 4.153 4.194 4.261 ;
     RECT  5.115 2.413 5.397 4.261 ;
     RECT  7.815 2.413 8.097 4.261 ;
     RECT  18.216 4.225 18.897 4.379 ;
     RECT  18.54 4.379 18.897 4.415 ;
     RECT  0.216 4.225 0.306 4.423 ;
     RECT  18.576 4.415 18.897 4.507 ;
     RECT  0.216 4.423 0.342 4.541 ;
     RECT  18.576 4.507 19.422 4.559 ;
     RECT  15.915 2.413 16.197 4.621 ;
     RECT  2.304 4.261 5.397 4.657 ;
     RECT  6.372 4.651 6.39 4.657 ;
     RECT  14.868 4.657 14.886 4.729 ;
     RECT  15.804 4.621 16.197 4.729 ;
     RECT  0.252 4.541 0.342 4.733 ;
     RECT  7.815 4.261 8.298 4.801 ;
     RECT  15.804 4.729 16.254 4.829 ;
     RECT  7.704 4.801 8.298 4.999 ;
     RECT  2.304 4.657 6.39 5.035 ;
     RECT  7.704 4.999 8.586 5.035 ;
     RECT  20.484 4.891 20.502 5.035 ;
     RECT  7.704 5.035 8.874 5.071 ;
     RECT  14.832 4.729 14.886 5.161 ;
     RECT  15.804 4.829 16.197 5.161 ;
     RECT  17.064 4.621 17.694 5.161 ;
     RECT  18.576 4.559 19.098 5.161 ;
     RECT  20.484 5.035 20.538 5.161 ;
     RECT  7.344 5.071 9.342 5.189 ;
     RECT  17.028 5.161 19.098 5.261 ;
     RECT  2.304 5.035 6.606 5.269 ;
     RECT  7.344 5.189 9.27 5.269 ;
     RECT  17.748 5.261 19.098 5.341 ;
     RECT  19.944 5.161 20.538 5.341 ;
     RECT  0.288 4.733 0.342 5.405 ;
     RECT  17.748 5.341 20.538 5.459 ;
     RECT  13.215 2.413 13.497 5.701 ;
     RECT  18.216 5.459 20.538 5.801 ;
     RECT  14.832 5.161 16.197 5.845 ;
     RECT  0.252 5.575 0.27 5.899 ;
     RECT  14.652 5.845 16.197 5.971 ;
     RECT  0.216 5.899 0.27 6.029 ;
     RECT  14.22 5.971 16.197 6.071 ;
     RECT  0.252 6.029 0.27 6.125 ;
     RECT  14.652 6.071 16.197 6.151 ;
     RECT  14.652 6.151 16.506 6.269 ;
     RECT  2.304 5.269 9.27 6.412 ;
     RECT  14.832 6.269 16.506 6.511 ;
     RECT  18.576 5.801 20.538 6.611 ;
     RECT  14.832 6.511 16.722 6.619 ;
     RECT  18.576 6.611 19.062 6.655 ;
     RECT  2.268 6.412 9.27 6.691 ;
     RECT  2.268 6.691 9.558 6.809 ;
     RECT  18.468 6.655 19.062 6.809 ;
     RECT  2.268 6.809 8.946 6.845 ;
     RECT  18.576 6.809 19.062 7.079 ;
     RECT  14.832 6.619 17.046 7.115 ;
     RECT  19.944 6.611 20.538 7.133 ;
     RECT  10.515 4.145 10.797 7.231 ;
     RECT  14.868 7.115 17.046 7.321 ;
     RECT  18.615 7.079 19.062 7.349 ;
     RECT  14.868 7.321 17.478 7.421 ;
     RECT  18.615 7.349 18.99 7.421 ;
     RECT  2.304 6.845 8.946 7.627 ;
     RECT  17.496 7.501 17.622 7.727 ;
     RECT  2.304 7.627 9.63 7.771 ;
     RECT  18.615 7.421 18.897 7.861 ;
     RECT  14.868 7.421 16.758 7.889 ;
     RECT  2.304 7.771 9.702 7.933 ;
     RECT  0.216 7.393 0.234 7.997 ;
     RECT  2.304 7.933 9.774 7.997 ;
     RECT  14.868 7.889 16.722 8.005 ;
     RECT  2.304 7.997 9.666 8.069 ;
     RECT  19.98 7.133 20.538 8.155 ;
     RECT  14.76 8.005 16.722 8.159 ;
     RECT  17.712 8.041 17.73 8.159 ;
     RECT  10.515 7.231 10.854 8.311 ;
     RECT  14.832 8.159 16.722 8.429 ;
     RECT  10.515 8.311 10.926 8.501 ;
     RECT  19.944 8.155 20.538 8.525 ;
     RECT  18.576 7.861 18.897 8.545 ;
     RECT  2.304 8.069 9.63 8.635 ;
     RECT  18.396 8.545 18.897 8.699 ;
     RECT  2.232 8.635 9.63 8.807 ;
     RECT  14.832 8.429 15.138 8.807 ;
     RECT  20.448 8.525 20.538 8.827 ;
     RECT  17.604 8.941 17.622 9.077 ;
     RECT  20.448 8.827 20.574 9.077 ;
     RECT  17.676 9.121 17.694 9.347 ;
     RECT  14.868 8.807 15.138 9.391 ;
     RECT  15.876 8.429 16.65 9.391 ;
     RECT  14.868 9.391 16.65 9.509 ;
     RECT  20.448 9.077 20.538 9.589 ;
     RECT  14.868 9.509 15.138 9.625 ;
     RECT  18.504 8.699 18.897 9.625 ;
     RECT  19.944 9.589 20.538 9.725 ;
     RECT  14.652 9.625 15.138 9.779 ;
     RECT  18.108 9.625 18.897 9.851 ;
     RECT  15.876 9.509 16.65 9.895 ;
     RECT  13.176 5.701 13.497 9.931 ;
     RECT  15.876 9.895 17.154 10.049 ;
     RECT  18.396 9.851 18.897 10.049 ;
     RECT  2.304 8.807 9.63 10.093 ;
     RECT  0.216 10.027 0.234 10.157 ;
     RECT  13.176 9.931 14.022 10.229 ;
     RECT  17.136 10.049 17.154 10.391 ;
     RECT  10.515 8.501 10.797 10.471 ;
     RECT  14.868 9.779 15.138 10.471 ;
     RECT  15.876 10.049 16.197 10.471 ;
     RECT  20.484 9.725 20.538 10.555 ;
     RECT  18.615 10.049 18.897 10.561 ;
     RECT  10.515 10.471 10.926 10.661 ;
     RECT  17.208 10.399 17.226 10.697 ;
     RECT  18.615 10.561 19.098 10.699 ;
     RECT  19.908 10.555 20.538 10.699 ;
     RECT  2.304 10.093 9.702 10.769 ;
     RECT  18.615 10.699 20.538 10.925 ;
     RECT  17.676 10.831 17.694 10.931 ;
     RECT  18.615 10.925 20.502 11.101 ;
     RECT  0.216 11.035 0.234 11.165 ;
     RECT  17.82 11.101 20.502 11.201 ;
     RECT  14.868 10.471 16.197 11.371 ;
     RECT  10.515 10.661 10.854 11.399 ;
     RECT  18.576 11.201 20.502 11.399 ;
     RECT  17.82 11.201 17.838 11.435 ;
     RECT  14.868 11.371 16.83 11.471 ;
     RECT  2.304 10.769 9.63 11.677 ;
     RECT  0.252 11.707 0.27 12.091 ;
     RECT  18.576 11.399 19.422 12.181 ;
     RECT  20.52 11.749 20.538 12.181 ;
     RECT  0.252 12.091 0.414 12.235 ;
     RECT  0.216 12.235 0.414 12.269 ;
     RECT  17.604 12.181 20.538 12.281 ;
     RECT  0.216 12.269 0.234 12.365 ;
     RECT  17.892 12.281 20.538 12.389 ;
     RECT  14.868 11.471 16.197 12.523 ;
     RECT  2.304 11.677 9.666 12.757 ;
     RECT  2.304 12.757 9.702 12.821 ;
     RECT  9.324 12.821 9.702 12.829 ;
     RECT  14.868 12.523 16.542 12.829 ;
     RECT  19.944 12.389 20.538 12.857 ;
     RECT  14.652 12.829 16.542 12.865 ;
     RECT  2.304 12.821 8.586 12.955 ;
     RECT  14.652 12.865 16.722 13.019 ;
     RECT  2.268 12.955 8.586 13.055 ;
     RECT  9.324 12.829 9.738 13.091 ;
     RECT  14.832 13.019 16.722 13.091 ;
     RECT  17.892 12.389 18.897 13.091 ;
     RECT  15.876 13.091 16.722 13.171 ;
     RECT  15.876 13.171 17.73 13.289 ;
     RECT  15.876 13.289 16.758 13.361 ;
     RECT  18.615 13.091 18.897 13.435 ;
     RECT  2.304 13.055 8.586 13.711 ;
     RECT  9.324 13.091 9.666 13.711 ;
     RECT  10.515 11.399 10.797 13.801 ;
     RECT  0.216 13.405 0.234 13.853 ;
     RECT  17.532 13.289 17.73 13.945 ;
     RECT  18.615 13.435 19.422 13.945 ;
     RECT  17.532 13.945 19.422 14.009 ;
     RECT  15.876 13.361 16.722 14.099 ;
     RECT  0.252 13.963 0.27 14.141 ;
     RECT  14.832 13.091 15.138 14.179 ;
     RECT  15.876 14.099 16.578 14.179 ;
     RECT  14.832 14.179 16.578 14.251 ;
     RECT  14.328 14.251 16.578 14.369 ;
     RECT  17.532 14.009 19.062 14.369 ;
     RECT  17.676 14.369 19.062 14.639 ;
     RECT  20.484 12.857 20.538 14.717 ;
     RECT  20.484 14.717 20.502 14.827 ;
     RECT  19.944 14.827 20.502 14.909 ;
     RECT  13.176 10.229 13.497 14.917 ;
     RECT  10.515 13.801 10.854 15.089 ;
     RECT  2.304 13.711 9.666 15.151 ;
     RECT  14.868 14.369 16.578 15.259 ;
     RECT  17.676 14.639 18.99 15.259 ;
     RECT  14.868 15.259 18.99 15.359 ;
     RECT  0.216 15.259 0.234 15.389 ;
     RECT  2.304 15.151 9.702 15.449 ;
     RECT  9.324 15.449 9.702 15.593 ;
     RECT  14.868 15.359 17.73 15.601 ;
     RECT  10.515 15.089 10.818 15.629 ;
     RECT  18.615 15.359 18.99 15.691 ;
     RECT  14.832 15.601 17.73 15.989 ;
     RECT  20.484 14.909 20.502 15.989 ;
     RECT  14.832 15.989 17.154 16.061 ;
     RECT  18.615 15.691 19.422 16.303 ;
     RECT  2.304 15.449 8.586 16.411 ;
     RECT  9.324 15.593 9.666 16.411 ;
     RECT  18 16.303 19.422 16.411 ;
     RECT  13.176 14.917 13.95 16.501 ;
     RECT  14.832 16.061 16.938 16.501 ;
     RECT  13.176 16.501 16.938 16.529 ;
     RECT  0.216 16.375 0.234 16.589 ;
     RECT  18 16.411 19.962 16.601 ;
     RECT  2.304 16.411 9.666 16.645 ;
     RECT  2.268 16.645 9.666 16.733 ;
     RECT  18.54 16.601 19.962 17.041 ;
     RECT  10.515 15.629 10.797 17.149 ;
     RECT  18.54 17.041 20.538 17.519 ;
     RECT  17.28 17.455 17.298 17.581 ;
     RECT  18.54 17.519 19.422 17.581 ;
     RECT  0.252 17.467 0.27 17.597 ;
     RECT  10.515 17.149 10.926 17.609 ;
     RECT  17.28 17.581 19.422 17.609 ;
     RECT  17.28 17.609 18.897 17.681 ;
     RECT  2.304 16.733 9.666 17.761 ;
     RECT  2.304 17.761 9.702 17.987 ;
     RECT  17.28 17.681 17.694 18.149 ;
     RECT  13.176 16.529 16.362 18.265 ;
     RECT  20.484 17.519 20.538 18.283 ;
     RECT  13.176 18.265 17.082 18.419 ;
     RECT  18.615 17.681 18.897 18.535 ;
     RECT  10.515 17.609 10.797 18.571 ;
     RECT  18.576 18.535 18.897 18.733 ;
     RECT  19.944 18.283 20.538 18.761 ;
     RECT  2.304 17.987 9.666 18.841 ;
     RECT  20.484 18.761 20.538 18.955 ;
     RECT  13.176 18.419 16.722 19.229 ;
     RECT  2.304 18.841 9.702 19.237 ;
     RECT  10.515 18.571 10.854 19.273 ;
     RECT  20.484 18.955 20.574 19.337 ;
     RECT  18.576 18.733 19.134 19.345 ;
     RECT  10.515 19.273 10.926 19.373 ;
     RECT  2.304 19.237 9.774 19.409 ;
     RECT  18.036 19.345 19.134 19.483 ;
     RECT  18.036 19.483 19.422 19.499 ;
     RECT  0.54 18.697 0.558 19.517 ;
     RECT  18.54 19.499 19.422 19.679 ;
     RECT  17.136 19.615 17.154 19.885 ;
     RECT  13.176 19.229 16.362 20.011 ;
     RECT  17.136 19.885 17.766 20.011 ;
     RECT  13.176 20.011 17.766 20.039 ;
     RECT  18.54 19.679 19.098 20.039 ;
     RECT  13.176 20.039 17.694 20.111 ;
     RECT  10.515 19.373 10.854 20.147 ;
     RECT  2.304 19.409 9.738 20.219 ;
     RECT  13.176 20.111 17.586 20.309 ;
     RECT  18.615 20.039 19.098 20.827 ;
     RECT  18.615 20.827 19.422 20.957 ;
     RECT  0.216 20.923 0.234 20.965 ;
     RECT  20.484 19.337 20.538 21.019 ;
     RECT  0.216 20.965 0.27 21.053 ;
     RECT  2.304 20.219 9.702 21.091 ;
     RECT  2.304 21.091 9.774 21.191 ;
     RECT  9.324 21.191 9.774 21.299 ;
     RECT  13.176 20.309 16.866 21.361 ;
     RECT  0.252 21.053 0.27 21.389 ;
     RECT  13.176 21.361 17.082 21.469 ;
     RECT  13.176 21.469 17.406 21.505 ;
     RECT  2.304 21.191 8.586 21.547 ;
     RECT  19.944 21.019 20.538 21.581 ;
     RECT  13.176 21.505 17.586 21.659 ;
     RECT  2.268 21.547 8.586 21.695 ;
     RECT  18.615 20.957 18.897 21.901 ;
     RECT  2.304 21.695 8.586 22.045 ;
     RECT  9.324 21.299 9.666 22.045 ;
     RECT  18.615 21.901 18.954 22.411 ;
     RECT  13.176 21.659 17.514 22.469 ;
     RECT  20.484 21.581 20.538 22.555 ;
     RECT  18.615 22.411 18.99 22.585 ;
     RECT  2.304 22.045 9.666 22.699 ;
     RECT  18.615 22.585 19.062 22.711 ;
     RECT  2.304 22.699 9.702 22.739 ;
     RECT  18.36 22.711 19.062 22.739 ;
     RECT  13.176 22.469 17.406 22.775 ;
     RECT  13.176 22.775 16.866 22.811 ;
     RECT  18.36 22.739 18.954 22.855 ;
     RECT  18.18 22.855 18.954 23.009 ;
     RECT  10.515 20.147 10.797 23.017 ;
     RECT  10.515 23.017 10.926 23.117 ;
     RECT  11.664 21.811 11.682 23.161 ;
     RECT  18.18 23.009 18.897 23.251 ;
     RECT  0.54 22.045 0.558 23.261 ;
     RECT  13.176 22.811 16.794 23.791 ;
     RECT  19.944 22.555 20.538 23.819 ;
     RECT  0.216 23.755 0.234 23.885 ;
     RECT  13.176 23.791 16.866 23.891 ;
     RECT  17.676 23.251 18.897 23.947 ;
     RECT  19.944 23.819 20.502 24.125 ;
     RECT  17.676 23.947 18.954 24.197 ;
     RECT  17.676 24.197 18.897 24.205 ;
     RECT  17.64 24.205 18.897 24.359 ;
     RECT  2.304 22.739 9.666 24.637 ;
     RECT  10.515 23.117 10.854 24.673 ;
     RECT  17.676 24.359 18.897 24.701 ;
     RECT  10.515 24.673 10.926 24.773 ;
     RECT  19.944 24.125 19.962 24.845 ;
     RECT  19.98 24.871 19.998 24.989 ;
     RECT  18 24.701 18.897 25.015 ;
     RECT  18 25.015 19.134 25.169 ;
     RECT  2.304 24.637 9.702 25.205 ;
     RECT  13.176 23.891 16.794 25.213 ;
     RECT  18 25.169 18.99 25.241 ;
     RECT  20.484 25.147 20.538 25.321 ;
     RECT  10.515 24.773 10.797 25.411 ;
     RECT  13.176 25.213 17.046 25.439 ;
     RECT  10.476 25.411 10.797 25.469 ;
     RECT  20.484 25.321 20.61 25.517 ;
     RECT  18 25.241 18.897 25.555 ;
     RECT  2.376 25.205 9.702 25.709 ;
     RECT  17.532 25.555 18.897 25.709 ;
     RECT  2.376 25.709 9.666 26.011 ;
     RECT  2.34 26.011 9.666 26.095 ;
     RECT  20.484 25.517 20.574 26.249 ;
     RECT  10.515 25.469 10.797 26.257 ;
     RECT  10.515 26.257 10.926 26.329 ;
     RECT  11.664 23.161 12.258 26.329 ;
     RECT  20.484 26.249 20.538 26.347 ;
     RECT  13.176 25.439 16.794 26.365 ;
     RECT  13.176 26.365 17.046 26.635 ;
     RECT  17.892 25.709 18.897 26.635 ;
     RECT  20.124 26.347 20.538 26.671 ;
     RECT  19.944 26.671 20.538 26.717 ;
     RECT  13.176 26.635 19.026 26.875 ;
     RECT  13.176 26.875 19.422 26.969 ;
     RECT  20.52 26.717 20.538 27.211 ;
     RECT  13.176 26.969 18.897 27.329 ;
     RECT  20.52 27.211 20.574 27.547 ;
     RECT  18.252 27.329 18.897 27.599 ;
     RECT  20.484 27.547 20.574 27.599 ;
     RECT  18.324 27.599 18.897 27.635 ;
     RECT  18.54 27.635 18.897 27.905 ;
     RECT  10.515 26.329 12.258 28.021 ;
     RECT  13.176 27.329 17.478 28.021 ;
     RECT  18.615 27.905 18.897 28.111 ;
     RECT  10.515 28.021 17.478 28.139 ;
     RECT  18.615 28.111 19.098 28.211 ;
     RECT  20.52 27.599 20.574 28.219 ;
     RECT  2.304 26.095 9.666 28.255 ;
     RECT  17.568 28.291 17.586 28.409 ;
     RECT  2.268 28.255 9.666 28.445 ;
     RECT  2.268 28.445 8.586 28.481 ;
     RECT  20.52 28.219 20.61 28.561 ;
     RECT  2.268 28.481 8.334 28.589 ;
     RECT  18.615 28.211 18.897 28.651 ;
     RECT  19.944 28.561 20.61 28.685 ;
     RECT  18.576 28.651 18.897 28.751 ;
     RECT  10.515 28.139 16.794 29.029 ;
     RECT  18.615 28.751 18.897 29.131 ;
     RECT  2.304 28.589 8.334 29.291 ;
     RECT  10.515 29.029 17.118 29.371 ;
     RECT  2.304 29.291 2.97 29.399 ;
     RECT  18.615 29.131 18.954 29.399 ;
     RECT  19.944 28.685 20.538 29.399 ;
     RECT  20.484 29.399 20.538 29.461 ;
     RECT  0.252 28.651 0.27 29.659 ;
     RECT  20.484 29.461 20.574 29.693 ;
     RECT  0.216 29.659 0.27 29.731 ;
     RECT  20.484 29.693 20.538 29.885 ;
     RECT  10.515 29.371 17.694 30.001 ;
     RECT  18.615 29.399 18.897 30.001 ;
     RECT  2.304 29.399 2.862 30.028 ;
     RECT  10.515 30.001 18.897 30.181 ;
     RECT  2.268 30.028 2.862 30.221 ;
     RECT  10.515 30.181 19.422 30.221 ;
     RECT  20.52 29.885 20.538 30.365 ;
     RECT  9.324 28.445 9.666 30.541 ;
     RECT  10.515 30.221 18.99 30.541 ;
     RECT  9.324 30.541 18.99 30.605 ;
     RECT  3.744 29.291 8.334 30.649 ;
     RECT  9.324 30.605 16.866 30.649 ;
     RECT  2.304 30.221 2.862 30.749 ;
     RECT  3.744 30.649 16.866 31.019 ;
     RECT  17.892 30.605 18.99 31.051 ;
     RECT  19.944 30.649 19.962 31.051 ;
     RECT  2.415 30.749 2.862 31.081 ;
     RECT  3.744 31.019 9.666 31.081 ;
     RECT  0.216 29.731 0.558 31.085 ;
     RECT  17.892 31.051 19.962 31.229 ;
     RECT  17.892 31.229 19.422 31.415 ;
     RECT  18.615 31.415 19.422 31.421 ;
     RECT  10.515 31.019 16.866 31.657 ;
     RECT  17.784 31.531 17.802 31.657 ;
     RECT  20.52 31.261 20.538 31.657 ;
     RECT  2.415 31.081 9.666 31.757 ;
     RECT  3.42 31.757 9.666 31.829 ;
     RECT  0.54 31.085 0.558 31.891 ;
     RECT  10.515 31.657 17.802 31.919 ;
     RECT  0.504 31.891 0.558 32.093 ;
     RECT  3.42 31.829 8.334 32.099 ;
     RECT  0.504 32.093 0.522 32.285 ;
     RECT  2.415 31.757 2.697 32.395 ;
     RECT  10.515 31.919 17.622 32.603 ;
     RECT  18.615 31.421 18.897 32.611 ;
     RECT  18.54 32.611 18.897 32.701 ;
     RECT  10.515 32.603 17.154 32.729 ;
     RECT  20.52 31.657 20.61 32.765 ;
     RECT  3.744 32.099 8.334 32.773 ;
     RECT  9.144 31.829 9.666 32.773 ;
     RECT  18.108 32.701 18.897 32.801 ;
     RECT  18.324 32.801 18.897 32.809 ;
     RECT  2.304 32.395 2.697 32.845 ;
     RECT  18.324 32.809 19.422 32.881 ;
     RECT  20.52 32.765 20.574 32.881 ;
     RECT  2.304 32.845 2.862 32.957 ;
     RECT  18.324 32.881 20.574 33.035 ;
     RECT  0.216 32.971 0.234 33.043 ;
     RECT  2.415 32.957 2.862 33.071 ;
     RECT  18.615 33.035 20.574 33.149 ;
     RECT  19.944 33.149 20.574 33.485 ;
     RECT  10.515 32.729 16.794 33.691 ;
     RECT  0.216 33.043 0.558 34.013 ;
     RECT  3.744 32.773 9.666 34.051 ;
     RECT  10.515 33.691 17.37 34.087 ;
     RECT  10.515 34.087 17.766 34.115 ;
     RECT  3.708 34.051 9.666 34.151 ;
     RECT  19.944 33.485 20.538 34.157 ;
     RECT  18.615 33.149 18.99 34.159 ;
     RECT  19.944 34.157 20.502 34.159 ;
     RECT  3.708 34.151 8.298 34.231 ;
     RECT  17.532 34.115 17.766 34.321 ;
     RECT  18.615 34.159 20.502 34.321 ;
     RECT  9.288 34.151 9.666 34.349 ;
     RECT  17.532 34.321 20.502 34.349 ;
     RECT  3.6 34.231 8.298 34.385 ;
     RECT  17.532 34.349 18.954 34.385 ;
     RECT  18 34.385 18.954 34.421 ;
     RECT  2.415 33.071 2.697 34.459 ;
     RECT  2.304 34.459 2.697 34.529 ;
     RECT  9.288 34.349 9.594 34.529 ;
     RECT  18.504 34.421 18.954 34.619 ;
     RECT  0.504 34.013 0.558 34.829 ;
     RECT  10.515 34.115 16.794 34.861 ;
     RECT  0.504 34.829 0.522 35.021 ;
     RECT  2.415 34.529 2.697 35.041 ;
     RECT  19.944 34.349 20.502 35.131 ;
     RECT  10.515 34.861 17.262 35.195 ;
     RECT  2.415 35.041 2.826 35.213 ;
     RECT  18.576 34.619 18.954 35.275 ;
     RECT  19.944 35.131 20.538 35.275 ;
     RECT  3.744 34.385 8.298 35.401 ;
     RECT  9.36 34.529 9.594 35.401 ;
     RECT  3.744 35.401 9.666 35.473 ;
     RECT  2.415 35.213 2.697 35.581 ;
     RECT  3.744 35.473 9.738 35.671 ;
     RECT  10.515 35.195 16.83 35.671 ;
     RECT  2.304 35.581 2.697 35.693 ;
     RECT  17.604 35.581 17.622 35.735 ;
     RECT  3.744 35.671 16.83 35.771 ;
     RECT  18.576 35.275 20.538 35.885 ;
     RECT  3.744 35.771 9.45 36.077 ;
     RECT  0.216 35.323 0.234 36.211 ;
     RECT  18.576 35.885 19.062 36.211 ;
     RECT  19.944 35.885 20.538 36.211 ;
     RECT  0.216 36.211 0.558 36.221 ;
     RECT  17.892 36.211 19.062 36.275 ;
     RECT  17.892 36.275 18.954 36.311 ;
     RECT  18.468 36.311 18.954 36.419 ;
     RECT  10.515 35.771 16.83 36.481 ;
     RECT  0.54 36.221 0.558 36.557 ;
     RECT  3.744 36.077 9.378 36.581 ;
     RECT  2.415 35.693 2.697 36.715 ;
     RECT  19.944 36.211 20.574 36.749 ;
     RECT  3.744 36.581 9.126 36.815 ;
     RECT  9.108 36.815 9.126 36.887 ;
     RECT  10.515 36.481 17.154 36.931 ;
     RECT  10.515 36.931 17.19 37.049 ;
     RECT  19.944 36.749 20.538 37.085 ;
     RECT  2.304 36.715 2.697 37.201 ;
     RECT  18.468 36.419 18.897 37.201 ;
     RECT  2.304 37.201 2.862 37.229 ;
     RECT  18.468 37.201 18.954 37.291 ;
     RECT  2.415 37.229 2.862 37.355 ;
     RECT  17.892 37.291 18.954 37.391 ;
     RECT  10.515 37.049 17.118 37.463 ;
     RECT  3.744 36.815 8.334 37.471 ;
     RECT  0.54 37.291 0.558 37.561 ;
     RECT  18.216 37.391 18.954 37.561 ;
     RECT  19.944 37.085 19.998 37.561 ;
     RECT  3.42 37.471 8.334 37.597 ;
     RECT  3.42 37.597 8.514 37.625 ;
     RECT  3.744 37.625 8.514 37.895 ;
     RECT  0.504 37.561 0.558 37.949 ;
     RECT  18.216 37.561 19.998 37.975 ;
     RECT  2.415 37.355 2.697 38.101 ;
     RECT  10.515 37.463 16.794 38.281 ;
     RECT  10.515 38.281 17.442 38.399 ;
     RECT  2.415 38.101 2.862 38.479 ;
     RECT  18.216 37.975 20.538 38.551 ;
     RECT  18 38.551 20.538 38.641 ;
     RECT  18 38.641 20.574 38.813 ;
     RECT  2.415 38.479 2.934 38.821 ;
     RECT  18 38.813 19.962 38.957 ;
     RECT  2.415 38.821 2.97 39.019 ;
     RECT  3.744 37.895 8.097 39.019 ;
     RECT  2.415 39.019 8.097 39.091 ;
     RECT  18 38.957 19.062 39.181 ;
     RECT  17.892 39.181 19.062 39.281 ;
     RECT  19.944 38.957 19.962 39.559 ;
     RECT  2.304 39.091 8.097 39.821 ;
     RECT  19.944 39.559 19.998 39.821 ;
     RECT  18.54 39.281 19.062 39.865 ;
     RECT  2.304 39.821 2.754 39.979 ;
     RECT  10.515 38.399 16.794 40.099 ;
     RECT  18.54 39.865 19.098 40.171 ;
     RECT  19.944 39.821 19.962 40.171 ;
     RECT  2.196 39.979 2.754 40.199 ;
     RECT  0.54 37.949 0.558 40.261 ;
     RECT  0.468 40.261 0.558 40.349 ;
     RECT  3.492 39.821 8.097 40.469 ;
     RECT  0.468 40.349 0.522 40.493 ;
     RECT  10.515 40.099 17.262 40.531 ;
     RECT  10.515 40.531 17.73 40.631 ;
     RECT  18.54 40.171 19.962 40.651 ;
     RECT  0.468 40.493 0.486 40.685 ;
     RECT  2.415 40.199 2.754 40.711 ;
     RECT  18.288 40.651 19.962 40.829 ;
     RECT  3.888 40.469 8.097 40.837 ;
     RECT  2.415 40.711 2.826 40.865 ;
     RECT  18.54 40.829 19.962 40.873 ;
     RECT  3.888 40.837 8.478 40.937 ;
     RECT  0.252 40.981 0.27 41.357 ;
     RECT  2.415 40.865 2.697 41.512 ;
     RECT  18.54 40.873 20.538 41.555 ;
     RECT  3.888 40.937 8.154 41.611 ;
     RECT  10.515 40.631 17.37 41.675 ;
     RECT  2.304 41.512 2.697 41.719 ;
     RECT  3.492 41.611 8.154 41.719 ;
     RECT  2.304 41.719 8.154 41.881 ;
     RECT  20.52 41.555 20.538 41.881 ;
     RECT  2.304 41.881 8.334 42.017 ;
     RECT  0.288 41.755 0.306 42.061 ;
     RECT  18.54 41.555 19.422 42.179 ;
     RECT  20.52 41.881 20.574 42.221 ;
     RECT  0.288 42.061 0.558 42.283 ;
     RECT  0.216 42.283 0.558 42.413 ;
     RECT  18.615 42.179 19.422 42.421 ;
     RECT  20.52 42.221 20.538 42.421 ;
     RECT  10.515 41.675 17.082 42.601 ;
     RECT  18.615 42.421 20.538 42.941 ;
     RECT  20.52 42.941 20.538 42.961 ;
     RECT  10.515 42.601 17.226 43.141 ;
     RECT  10.515 43.141 17.514 43.375 ;
     RECT  10.515 43.375 17.586 43.501 ;
     RECT  10.515 43.501 17.622 43.565 ;
     RECT  18.615 42.941 19.458 43.645 ;
     RECT  17.496 43.565 17.622 43.681 ;
     RECT  18.576 43.645 19.458 43.681 ;
     RECT  10.515 43.565 16.542 43.799 ;
     RECT  17.496 43.681 19.458 43.835 ;
     RECT  0.54 42.413 0.558 43.843 ;
     RECT  17.496 43.835 17.802 44.069 ;
     RECT  18.576 43.835 19.458 44.221 ;
     RECT  20.52 42.961 20.574 44.221 ;
     RECT  2.304 42.017 8.097 44.375 ;
     RECT  10.515 43.799 16.326 44.375 ;
     RECT  18.576 44.221 20.574 44.621 ;
     RECT  2.304 44.375 2.862 44.645 ;
     RECT  2.304 44.645 2.79 44.813 ;
     RECT  0.504 43.843 0.558 44.851 ;
     RECT  3.6 44.375 8.097 44.851 ;
     RECT  17.496 44.069 17.514 44.851 ;
     RECT  16.92 44.851 17.514 44.915 ;
     RECT  3.6 44.851 8.118 44.951 ;
     RECT  18.576 44.621 20.538 45.031 ;
     RECT  10.515 44.375 16.197 45.059 ;
     RECT  18.54 45.031 20.538 45.185 ;
     RECT  0.252 44.851 0.558 45.211 ;
     RECT  11.952 45.059 16.197 45.257 ;
     RECT  0.216 45.211 0.558 45.341 ;
     RECT  18.576 45.185 20.538 45.341 ;
     RECT  12.24 45.257 16.197 45.391 ;
     RECT  16.92 44.915 17.298 45.391 ;
     RECT  0.252 45.341 0.558 45.485 ;
     RECT  12.24 45.391 17.298 45.491 ;
     RECT  2.415 44.813 2.79 45.571 ;
     RECT  3.6 44.951 8.097 45.571 ;
     RECT  2.415 45.571 8.097 45.797 ;
     RECT  3.636 45.797 8.097 45.869 ;
     RECT  18.576 45.341 19.098 45.931 ;
     RECT  12.24 45.491 17.046 45.959 ;
     RECT  0.504 45.485 0.558 46.205 ;
     RECT  19.944 45.341 20.538 46.205 ;
     RECT  17.892 45.931 19.098 46.309 ;
     RECT  12.24 45.959 16.722 46.337 ;
     RECT  0.504 46.205 0.522 46.349 ;
     RECT  17.82 46.309 19.098 46.409 ;
     RECT  18.36 46.409 19.098 46.471 ;
     RECT  19.944 46.205 19.962 46.471 ;
     RECT  18.36 46.471 19.962 46.499 ;
     RECT  4.14 45.869 8.097 46.651 ;
     RECT  0.288 46.555 0.306 46.685 ;
     RECT  12.564 46.337 16.722 46.805 ;
     RECT  2.415 45.797 2.697 46.84 ;
     RECT  3.42 46.651 8.097 46.84 ;
     RECT  18.615 46.499 19.962 46.883 ;
     RECT  2.415 46.84 8.097 46.987 ;
     RECT  14.616 46.805 16.722 47.011 ;
     RECT  2.304 46.987 8.097 47.039 ;
     RECT  14.616 47.011 16.938 47.111 ;
     RECT  19.944 46.883 19.962 47.119 ;
     RECT  17.82 47.191 17.838 47.309 ;
     RECT  18.615 46.883 19.062 47.309 ;
     RECT  18.615 47.309 18.99 47.461 ;
     RECT  0.504 47.083 0.558 47.549 ;
     RECT  12.564 46.805 13.878 47.731 ;
     RECT  14.616 47.111 16.65 47.731 ;
     RECT  19.944 47.119 20.538 47.741 ;
     RECT  2.415 47.039 8.097 47.759 ;
     RECT  19.98 47.741 20.538 47.885 ;
     RECT  12.564 47.731 16.65 48.091 ;
     RECT  17.784 48.001 17.802 48.119 ;
     RECT  4.284 47.759 8.097 48.191 ;
     RECT  12.564 48.091 16.938 48.191 ;
     RECT  20.52 47.885 20.538 48.199 ;
     RECT  2.415 47.759 3.51 48.235 ;
     RECT  2.412 48.235 3.51 48.299 ;
     RECT  4.284 48.191 5.49 48.299 ;
     RECT  0.54 47.549 0.558 48.361 ;
     RECT  2.415 48.299 3.51 48.413 ;
     RECT  20.52 48.199 20.61 48.413 ;
     RECT  3.42 48.413 3.51 48.569 ;
     RECT  0.504 48.361 0.558 48.571 ;
     RECT  20.52 48.413 20.574 48.631 ;
     RECT  12.564 48.191 16.254 48.659 ;
     RECT  0.252 48.571 0.558 48.701 ;
     RECT  0.288 48.701 0.558 48.749 ;
     RECT  4.284 48.299 5.397 48.811 ;
     RECT  17.676 48.361 17.694 48.811 ;
     RECT  18.576 47.461 18.99 48.901 ;
     RECT  19.944 48.631 20.574 48.901 ;
     RECT  10.515 45.059 11.106 48.929 ;
     RECT  18.576 48.901 20.574 48.941 ;
     RECT  6.3 48.191 8.097 48.973 ;
     RECT  17.136 48.811 17.694 48.973 ;
     RECT  18.576 48.941 20.538 48.973 ;
     RECT  14.616 48.659 16.254 49.081 ;
     RECT  3.96 48.811 5.397 49.085 ;
     RECT  6.228 48.973 8.097 49.109 ;
     RECT  17.136 48.973 20.538 49.109 ;
     RECT  2.415 48.413 2.697 49.171 ;
     RECT  14.616 49.081 16.29 49.171 ;
     RECT  17.136 49.109 17.874 49.171 ;
     RECT  0.288 48.749 0.522 49.469 ;
     RECT  14.616 49.171 17.874 49.469 ;
     RECT  6.3 49.109 8.097 49.505 ;
     RECT  14.616 49.469 17.766 49.505 ;
     RECT  17.676 49.505 17.766 49.541 ;
     RECT  0.504 49.469 0.522 49.549 ;
     RECT  2.415 49.171 3.006 49.577 ;
     RECT  14.616 49.505 16.866 49.739 ;
     RECT  3.456 49.621 3.474 49.775 ;
     RECT  15.915 49.739 16.866 49.811 ;
     RECT  4.248 49.085 5.397 49.891 ;
     RECT  17.676 49.541 17.73 49.919 ;
     RECT  3.708 49.891 5.397 50.009 ;
     RECT  3.708 50.009 4.302 50.045 ;
     RECT  18.615 49.109 20.538 50.141 ;
     RECT  10.515 48.929 10.797 50.161 ;
     RECT  17.676 49.919 17.694 50.251 ;
     RECT  10.515 50.161 10.818 50.279 ;
     RECT  17.46 50.251 17.694 50.279 ;
     RECT  18.615 50.141 19.062 50.315 ;
     RECT  17.46 50.279 17.478 50.351 ;
     RECT  2.415 49.577 2.697 50.359 ;
     RECT  12.564 48.659 13.806 50.395 ;
     RECT  14.616 49.739 14.85 50.395 ;
     RECT  6.336 49.505 8.097 50.431 ;
     RECT  0.504 49.549 0.558 50.477 ;
     RECT  18.615 50.315 18.954 50.521 ;
     RECT  4.284 50.045 4.302 50.549 ;
     RECT  5.076 50.009 5.397 50.557 ;
     RECT  6.3 50.431 8.097 50.557 ;
     RECT  12.564 50.395 14.85 50.593 ;
     RECT  18.54 50.521 18.954 50.621 ;
     RECT  15.915 49.811 16.197 50.629 ;
     RECT  5.076 50.557 8.097 50.657 ;
     RECT  5.076 50.657 5.67 50.669 ;
     RECT  6.444 50.657 7.038 50.693 ;
     RECT  2.415 50.359 2.862 50.701 ;
     RECT  5.076 50.669 5.598 50.729 ;
     RECT  15.915 50.629 16.758 50.729 ;
     RECT  2.415 50.701 3.546 50.791 ;
     RECT  5.076 50.729 5.526 50.791 ;
     RECT  19.872 50.141 20.538 50.813 ;
     RECT  2.415 50.791 3.618 50.827 ;
     RECT  12.564 50.593 15.03 50.855 ;
     RECT  12.564 50.855 14.778 50.891 ;
     RECT  2.412 50.827 3.618 50.899 ;
     RECT  2.304 50.899 3.618 50.963 ;
     RECT  6.444 50.693 6.858 50.999 ;
     RECT  2.304 50.963 3.438 51.005 ;
     RECT  15.915 50.729 16.686 51.061 ;
     RECT  6.48 50.999 6.858 51.089 ;
     RECT  2.415 51.005 3.438 51.125 ;
     RECT  13.215 50.891 14.778 51.125 ;
     RECT  18.576 50.621 18.954 51.125 ;
     RECT  4.536 50.791 5.526 51.149 ;
     RECT  15.66 51.061 16.686 51.161 ;
     RECT  0.54 50.477 0.558 51.211 ;
     RECT  14.616 51.125 14.778 51.233 ;
     RECT  4.68 51.149 5.526 51.269 ;
     RECT  0.216 51.211 0.558 51.341 ;
     RECT  14.688 51.233 14.778 51.359 ;
     RECT  4.788 51.269 5.397 51.389 ;
     RECT  14.76 51.359 14.778 51.395 ;
     RECT  18.576 51.125 18.897 51.395 ;
     RECT  6.84 51.089 6.858 51.431 ;
     RECT  2.415 51.125 3.078 51.503 ;
     RECT  15.915 51.161 16.686 51.511 ;
     RECT  0.54 51.341 0.558 51.533 ;
     RECT  19.944 50.813 20.538 51.533 ;
     RECT  15.915 51.511 16.866 51.629 ;
     RECT  2.415 51.503 2.79 51.677 ;
     RECT  19.944 51.533 19.962 51.677 ;
     RECT  2.415 51.677 2.697 53.747 ;
     RECT  5.115 51.389 5.397 53.747 ;
     RECT  7.815 50.657 8.097 53.747 ;
     RECT  10.515 50.279 10.797 53.747 ;
     RECT  13.215 51.125 13.497 53.747 ;
     RECT  15.915 51.629 16.197 53.747 ;
     RECT  18.615 51.395 18.897 53.747 ;
     RECT  2.415 53.747 2.505 54.017 ;
     RECT  5.115 53.747 5.205 54.017 ;
     RECT  7.815 53.747 7.905 54.017 ;
     RECT  10.515 53.747 10.605 54.017 ;
     RECT  13.215 53.747 13.305 54.017 ;
     RECT  15.915 53.747 16.005 54.017 ;
     RECT  18.615 53.747 18.705 54.017 ;
    LAYER M4 ;
     RECT  0.192 4.512 0.245 4.536 ;
     RECT  0.156 4.536 0.245 4.704 ;
     RECT  0.192 4.704 0.245 4.728 ;
     RECT  0.156 4.728 0.245 4.896 ;
     RECT  0.192 4.896 0.245 4.92 ;
     RECT  0.156 4.92 0.245 5.04 ;
     RECT  0.192 5.04 0.245 5.064 ;
     RECT  0.156 5.064 0.245 5.232 ;
     RECT  0.192 5.232 0.245 5.256 ;
     RECT  0.156 5.256 0.245 5.376 ;
     RECT  0.192 5.376 0.245 5.4 ;
     RECT  0.156 5.4 0.245 5.568 ;
     RECT  0.192 5.568 0.245 5.592 ;
     RECT  0.156 5.592 0.245 5.712 ;
     RECT  0.192 5.712 0.245 5.736 ;
     RECT  0.156 5.736 0.245 5.904 ;
     RECT  0.192 5.904 0.245 5.928 ;
     RECT  0.156 5.928 0.245 6.096 ;
     RECT  0.192 6.096 0.245 6.12 ;
     RECT  0.156 6.12 0.245 6.24 ;
     RECT  0.192 6.24 0.245 6.264 ;
     RECT  0.156 6.264 0.245 6.432 ;
     RECT  0.192 6.432 0.245 6.456 ;
     RECT  0.156 6.456 0.245 6.576 ;
     RECT  0.192 6.576 0.245 6.6 ;
     RECT  0.156 6.6 0.245 6.768 ;
     RECT  0.192 6.768 0.245 6.792 ;
     RECT  0.156 6.792 0.245 6.96 ;
     RECT  0.192 6.96 0.245 6.984 ;
     RECT  0.156 6.984 0.245 7.104 ;
     RECT  0.192 7.104 0.245 7.128 ;
     RECT  0.156 7.128 0.245 7.296 ;
     RECT  0.192 7.296 0.245 7.32 ;
     RECT  0.156 7.32 0.245 7.44 ;
     RECT  0.192 7.44 0.245 7.464 ;
     RECT  0.156 7.464 0.245 7.632 ;
     RECT  0.192 7.632 0.245 7.656 ;
     RECT  0.156 7.656 0.245 7.776 ;
     RECT  0.192 7.776 0.245 7.8 ;
     RECT  0.156 7.8 0.245 7.968 ;
     RECT  0.192 7.968 0.245 7.992 ;
     RECT  0.156 7.992 0.245 8.16 ;
     RECT  0.192 8.16 0.245 8.184 ;
     RECT  0.156 8.184 0.245 8.304 ;
     RECT  0.192 8.304 0.245 8.328 ;
     RECT  0.156 8.328 0.245 8.496 ;
     RECT  0.192 8.496 0.245 8.52 ;
     RECT  0.156 8.52 0.245 8.64 ;
     RECT  0.192 8.64 0.245 8.664 ;
     RECT  0.156 8.664 0.245 8.832 ;
     RECT  0.192 8.832 0.245 8.856 ;
     RECT  0.156 8.856 0.245 8.976 ;
     RECT  0.192 8.976 0.245 9 ;
     RECT  0.156 9 0.245 9.168 ;
     RECT  0.192 9.168 0.245 9.192 ;
     RECT  0.156 9.192 0.245 9.36 ;
     RECT  0.192 9.36 0.245 9.384 ;
     RECT  0.156 9.384 0.245 9.504 ;
     RECT  0.192 9.504 0.245 9.528 ;
     RECT  0.156 9.528 0.245 9.696 ;
     RECT  0.192 9.696 0.245 9.72 ;
     RECT  0.156 9.72 0.245 9.84 ;
     RECT  0.192 9.84 0.245 9.864 ;
     RECT  0.156 9.864 0.245 10.032 ;
     RECT  0.192 10.032 0.245 10.056 ;
     RECT  0.156 10.056 0.245 10.224 ;
     RECT  0.192 10.224 0.245 10.248 ;
     RECT  0.156 10.248 0.245 10.368 ;
     RECT  0.192 10.368 0.245 10.392 ;
     RECT  0.156 10.392 0.245 10.56 ;
     RECT  0.192 10.56 0.245 10.584 ;
     RECT  0.156 10.584 0.245 10.704 ;
     RECT  0.192 10.704 0.245 10.728 ;
     RECT  0.156 10.728 0.245 10.896 ;
     RECT  0.192 10.896 0.245 10.92 ;
     RECT  0.156 10.92 0.245 11.04 ;
     RECT  0.192 11.04 0.245 11.064 ;
     RECT  0.156 11.064 0.245 11.232 ;
     RECT  0.192 11.232 0.245 11.256 ;
     RECT  0.156 11.256 0.245 11.424 ;
     RECT  0.192 11.424 0.245 11.448 ;
     RECT  0.156 11.448 0.245 11.568 ;
     RECT  0.192 11.568 0.245 11.592 ;
     RECT  0.156 11.592 0.245 11.76 ;
     RECT  0.192 11.76 0.245 11.784 ;
     RECT  0.156 11.784 0.245 11.904 ;
     RECT  0.192 11.904 0.245 11.928 ;
     RECT  0.156 11.928 0.245 12.096 ;
     RECT  0.192 12.096 0.245 12.12 ;
     RECT  0.156 12.12 0.245 12.24 ;
     RECT  0.192 12.24 0.245 12.264 ;
     RECT  0.156 12.264 0.245 12.432 ;
     RECT  0.192 12.432 0.245 12.456 ;
     RECT  0.156 12.456 0.245 12.624 ;
     RECT  0.192 12.624 0.245 12.648 ;
     RECT  0.156 12.648 0.245 12.768 ;
     RECT  0.192 12.768 0.245 12.792 ;
     RECT  0.156 12.792 0.245 12.96 ;
     RECT  0.192 12.96 0.245 12.984 ;
     RECT  0.156 12.984 0.245 13.104 ;
     RECT  0.192 13.104 0.245 13.128 ;
     RECT  0.156 13.128 0.245 13.296 ;
     RECT  0.192 13.296 0.245 13.32 ;
     RECT  0.156 13.32 0.245 13.44 ;
     RECT  0.192 13.44 0.245 13.464 ;
     RECT  0.156 13.464 0.245 13.632 ;
     RECT  0.192 13.632 0.245 13.656 ;
     RECT  0.156 13.656 0.245 13.824 ;
     RECT  0.192 13.824 0.245 13.848 ;
     RECT  0.156 13.848 0.245 13.968 ;
     RECT  0.192 13.968 0.245 13.992 ;
     RECT  0.156 13.992 0.245 14.16 ;
     RECT  0.192 14.16 0.245 14.184 ;
     RECT  0.156 14.184 0.245 14.304 ;
     RECT  0.192 14.304 0.245 14.328 ;
     RECT  0.156 14.328 0.245 14.496 ;
     RECT  0.192 14.496 0.245 14.52 ;
     RECT  0.156 14.52 0.245 14.688 ;
     RECT  0.192 14.688 0.245 14.712 ;
     RECT  0.156 14.712 0.245 14.832 ;
     RECT  0.192 14.832 0.245 14.856 ;
     RECT  0.156 14.856 0.245 15.024 ;
     RECT  0.192 15.024 0.245 15.048 ;
     RECT  0.156 15.048 0.245 15.168 ;
     RECT  0.192 15.168 0.245 15.192 ;
     RECT  0.156 15.192 0.245 15.36 ;
     RECT  0.192 15.36 0.245 15.384 ;
     RECT  0.156 15.384 0.245 15.504 ;
     RECT  0.192 15.504 0.245 15.528 ;
     RECT  0.156 15.528 0.245 15.696 ;
     RECT  0.192 15.696 0.245 15.72 ;
     RECT  0.156 15.72 0.245 15.888 ;
     RECT  0.192 15.888 0.245 15.912 ;
     RECT  0.156 15.912 0.245 16.032 ;
     RECT  0.192 16.032 0.245 16.056 ;
     RECT  0.156 16.056 0.245 16.224 ;
     RECT  0.192 16.224 0.245 16.248 ;
     RECT  0.156 16.248 0.245 16.368 ;
     RECT  0.192 16.368 0.245 16.392 ;
     RECT  0.156 16.392 0.245 16.56 ;
     RECT  0.192 16.56 0.245 16.584 ;
     RECT  0.156 16.584 0.245 16.704 ;
     RECT  0.192 16.704 0.245 16.728 ;
     RECT  0.156 16.728 0.245 16.896 ;
     RECT  0.192 16.896 0.245 16.92 ;
     RECT  0.156 16.92 0.245 17.088 ;
     RECT  0.192 17.088 0.245 17.112 ;
     RECT  0.156 17.112 0.245 17.232 ;
     RECT  0.192 17.232 0.245 17.256 ;
     RECT  0.156 17.256 0.245 17.424 ;
     RECT  0.192 17.424 0.245 17.448 ;
     RECT  0.156 17.448 0.245 17.568 ;
     RECT  0.192 17.568 0.245 17.592 ;
     RECT  0.156 17.592 0.245 17.76 ;
     RECT  0.192 17.76 0.245 17.784 ;
     RECT  0.156 17.784 0.245 17.952 ;
     RECT  0.192 17.952 0.245 17.976 ;
     RECT  0.156 17.976 0.245 18.096 ;
     RECT  0.192 18.096 0.245 18.12 ;
     RECT  0.156 18.12 0.245 18.288 ;
     RECT  0.192 18.288 0.245 18.312 ;
     RECT  0.156 18.312 0.245 18.432 ;
     RECT  0.192 18.432 0.245 18.456 ;
     RECT  0.156 18.456 0.245 18.624 ;
     RECT  0.192 18.624 0.245 18.648 ;
     RECT  0.156 18.648 0.245 18.768 ;
     RECT  0.192 18.768 0.245 18.792 ;
     RECT  0.156 18.792 0.245 18.96 ;
     RECT  0.192 18.96 0.245 18.984 ;
     RECT  0.156 18.984 0.245 19.152 ;
     RECT  0.192 19.152 0.245 19.176 ;
     RECT  0.156 19.176 0.245 19.296 ;
     RECT  0.192 19.296 0.245 19.32 ;
     RECT  0.156 19.32 0.245 19.488 ;
     RECT  0.192 19.488 0.245 19.512 ;
     RECT  0.156 19.512 0.245 19.632 ;
     RECT  0.192 19.632 0.245 19.656 ;
     RECT  0.156 19.656 0.245 19.824 ;
     RECT  0.192 19.824 0.245 19.848 ;
     RECT  0.156 19.848 0.245 19.968 ;
     RECT  0.192 19.968 0.245 19.992 ;
     RECT  0.156 19.992 0.245 20.16 ;
     RECT  0.192 20.16 0.245 20.184 ;
     RECT  0.156 20.184 0.245 20.352 ;
     RECT  0.192 20.352 0.245 20.376 ;
     RECT  0.156 20.376 0.245 20.496 ;
     RECT  0.192 20.496 0.245 20.52 ;
     RECT  0.156 20.52 0.245 20.688 ;
     RECT  0.192 20.688 0.245 20.712 ;
     RECT  0.156 20.712 0.245 20.832 ;
     RECT  0.192 20.832 0.245 20.856 ;
     RECT  0.156 20.856 0.245 21.024 ;
     RECT  0.192 21.024 0.245 21.048 ;
     RECT  0.156 21.048 0.245 21.216 ;
     RECT  0.192 21.216 0.245 21.24 ;
     RECT  0.156 21.24 0.245 21.36 ;
     RECT  0.192 21.36 0.245 21.384 ;
     RECT  0.156 21.384 0.245 21.552 ;
     RECT  0.192 21.552 0.245 21.576 ;
     RECT  0.156 21.576 0.245 21.696 ;
     RECT  0.192 21.696 0.245 21.72 ;
     RECT  0.156 21.72 0.245 21.888 ;
     RECT  0.192 21.888 0.245 21.912 ;
     RECT  0.156 21.912 0.245 22.032 ;
     RECT  0.192 22.032 0.245 22.056 ;
     RECT  0.156 22.056 0.245 22.224 ;
     RECT  0.192 22.224 0.245 22.248 ;
     RECT  0.156 22.248 0.245 22.416 ;
     RECT  0.192 22.416 0.245 22.44 ;
     RECT  0.156 22.44 0.245 22.56 ;
     RECT  0.192 22.56 0.245 22.584 ;
     RECT  0.156 22.584 0.245 22.752 ;
     RECT  0.192 22.752 0.245 22.776 ;
     RECT  0.156 22.776 0.245 22.896 ;
     RECT  0.192 22.896 0.245 22.92 ;
     RECT  0.156 22.92 0.245 23.088 ;
     RECT  0.192 23.088 0.245 23.112 ;
     RECT  0.156 23.112 0.245 23.232 ;
     RECT  0.192 23.232 0.245 23.256 ;
     RECT  0.156 23.256 0.245 23.424 ;
     RECT  0.192 23.424 0.245 23.448 ;
     RECT  0.156 23.448 0.245 23.616 ;
     RECT  0.192 23.616 0.245 23.64 ;
     RECT  0.156 23.64 0.245 23.76 ;
     RECT  0.192 23.76 0.245 23.784 ;
     RECT  0.156 23.784 0.245 23.952 ;
     RECT  0.192 23.952 0.245 23.976 ;
     RECT  0.156 23.976 0.245 24.096 ;
     RECT  0.192 24.096 0.245 24.12 ;
     RECT  0.156 24.12 0.245 24.288 ;
     RECT  0.192 24.288 0.245 24.312 ;
     RECT  0.156 24.312 0.245 24.48 ;
     RECT  0.192 24.48 0.245 24.504 ;
     RECT  0.156 24.504 0.245 24.624 ;
     RECT  0.192 24.624 0.245 24.648 ;
     RECT  0.156 24.648 0.245 24.816 ;
     RECT  0.192 24.816 0.245 24.84 ;
     RECT  0.156 24.84 0.245 24.96 ;
     RECT  0.192 24.96 0.245 24.984 ;
     RECT  0.156 24.984 0.245 25.152 ;
     RECT  0.192 25.152 0.245 25.176 ;
     RECT  0.156 25.176 0.245 25.296 ;
     RECT  0.192 25.296 0.245 25.32 ;
     RECT  0.156 25.32 0.245 25.488 ;
     RECT  0.192 25.488 0.245 25.512 ;
     RECT  0.156 25.512 0.245 25.68 ;
     RECT  0.192 25.68 0.245 25.704 ;
     RECT  0.156 25.704 0.245 25.824 ;
     RECT  0.192 25.824 0.245 25.848 ;
     RECT  0.156 25.848 0.245 26.016 ;
     RECT  0.192 26.016 0.245 26.04 ;
     RECT  0.156 26.04 0.245 26.16 ;
     RECT  0.192 26.16 0.245 26.184 ;
     RECT  0.156 26.184 0.245 26.352 ;
     RECT  0.192 26.352 0.245 26.376 ;
     RECT  0.156 26.376 0.245 26.496 ;
     RECT  0.192 26.496 0.245 26.52 ;
     RECT  0.156 26.52 0.245 26.688 ;
     RECT  0.192 26.688 0.245 26.712 ;
     RECT  0.156 26.712 0.245 26.88 ;
     RECT  0.192 26.88 0.245 26.904 ;
     RECT  0.156 26.904 0.245 27.024 ;
     RECT  0.192 27.024 0.245 27.048 ;
     RECT  0.156 27.048 0.245 27.216 ;
     RECT  0.192 27.216 0.245 27.24 ;
     RECT  0.156 27.24 0.245 27.36 ;
     RECT  0.192 27.36 0.245 27.384 ;
     RECT  0.156 27.384 0.245 27.552 ;
     RECT  0.192 27.552 0.245 27.576 ;
     RECT  0.156 27.576 0.245 27.744 ;
     RECT  0.192 27.744 0.245 27.768 ;
     RECT  0.156 27.768 0.245 27.888 ;
     RECT  0.192 27.888 0.245 27.912 ;
     RECT  0.156 27.912 0.245 28.272 ;
     RECT  0.192 28.272 0.245 28.296 ;
     RECT  0.156 28.296 0.245 28.464 ;
     RECT  0.192 28.464 0.245 28.488 ;
     RECT  0.156 28.488 0.245 28.656 ;
     RECT  0.192 28.656 0.245 28.68 ;
     RECT  0.156 28.68 0.245 28.8 ;
     RECT  0.192 28.8 0.245 28.824 ;
     RECT  0.156 28.824 0.245 28.992 ;
     RECT  0.192 28.992 0.245 29.016 ;
     RECT  0.156 29.016 0.245 29.136 ;
     RECT  0.192 29.136 0.245 29.16 ;
     RECT  0.156 29.16 0.245 29.328 ;
     RECT  0.192 29.328 0.245 29.352 ;
     RECT  0.156 29.352 0.245 29.472 ;
     RECT  0.192 29.472 0.245 29.496 ;
     RECT  0.156 29.496 0.245 29.664 ;
     RECT  0.192 29.664 0.245 29.688 ;
     RECT  0.156 29.688 0.245 29.856 ;
     RECT  0.192 29.856 0.245 29.88 ;
     RECT  0.156 29.88 0.245 30 ;
     RECT  0.192 30 0.245 30.024 ;
     RECT  0.156 30.024 0.245 30.192 ;
     RECT  0.192 30.192 0.245 30.216 ;
     RECT  0.156 30.216 0.245 30.336 ;
     RECT  0.192 30.336 0.245 30.36 ;
     RECT  0.156 30.36 0.245 30.528 ;
     RECT  0.192 30.528 0.245 30.552 ;
     RECT  0.156 30.552 0.245 30.72 ;
     RECT  0.192 30.72 0.245 30.744 ;
     RECT  0.156 30.744 0.245 30.864 ;
     RECT  0.192 30.864 0.245 30.888 ;
     RECT  0.156 30.888 0.245 31.056 ;
     RECT  0.192 31.056 0.245 31.08 ;
     RECT  0.156 31.08 0.245 31.2 ;
     RECT  0.192 31.2 0.245 31.224 ;
     RECT  0.156 31.224 0.245 31.392 ;
     RECT  0.192 31.392 0.245 31.416 ;
     RECT  0.156 31.416 0.245 31.536 ;
     RECT  0.192 31.536 0.245 31.56 ;
     RECT  0.156 31.56 0.245 31.728 ;
     RECT  0.192 31.728 0.245 31.752 ;
     RECT  0.156 31.752 0.245 31.92 ;
     RECT  0.192 31.92 0.245 31.944 ;
     RECT  0.156 31.944 0.245 32.064 ;
     RECT  0.192 32.064 0.245 32.088 ;
     RECT  0.156 32.088 0.245 32.256 ;
     RECT  0.192 32.256 0.245 32.28 ;
     RECT  0.156 32.28 0.245 32.4 ;
     RECT  0.192 32.4 0.245 32.424 ;
     RECT  0.156 32.424 0.245 32.592 ;
     RECT  0.192 32.592 0.245 32.616 ;
     RECT  0.156 32.616 0.245 32.736 ;
     RECT  0.192 32.736 0.245 32.76 ;
     RECT  0.156 32.76 0.245 32.928 ;
     RECT  0.192 32.928 0.245 32.952 ;
     RECT  0.156 32.952 0.245 33.12 ;
     RECT  0.192 33.12 0.245 33.144 ;
     RECT  0.156 33.144 0.245 33.264 ;
     RECT  0.192 33.264 0.245 33.288 ;
     RECT  0.156 33.288 0.245 33.456 ;
     RECT  0.192 33.456 0.245 33.48 ;
     RECT  0.156 33.48 0.245 33.6 ;
     RECT  0.192 33.6 0.245 33.624 ;
     RECT  0.156 33.624 0.245 33.792 ;
     RECT  0.192 33.792 0.245 33.816 ;
     RECT  0.156 33.816 0.245 33.984 ;
     RECT  0.192 33.984 0.245 34.008 ;
     RECT  0.156 34.008 0.245 34.128 ;
     RECT  0.192 34.128 0.245 34.152 ;
     RECT  0.156 34.152 0.245 34.32 ;
     RECT  0.192 34.32 0.245 34.344 ;
     RECT  0.156 34.344 0.245 34.464 ;
     RECT  0.192 34.464 0.245 34.488 ;
     RECT  0.156 34.488 0.245 34.656 ;
     RECT  0.192 34.656 0.245 34.68 ;
     RECT  0.156 34.68 0.245 34.8 ;
     RECT  0.192 34.8 0.245 34.824 ;
     RECT  0.156 34.824 0.245 34.992 ;
     RECT  0.192 34.992 0.245 35.016 ;
     RECT  0.156 35.016 0.245 35.184 ;
     RECT  0.192 35.184 0.245 35.208 ;
     RECT  0.156 35.208 0.245 35.328 ;
     RECT  0.192 35.328 0.245 35.352 ;
     RECT  0.156 35.352 0.245 35.52 ;
     RECT  0.192 35.52 0.245 35.544 ;
     RECT  0.156 35.544 0.245 35.664 ;
     RECT  0.192 35.664 0.245 35.688 ;
     RECT  0.156 35.688 0.245 35.856 ;
     RECT  0.192 35.856 0.245 35.88 ;
     RECT  0.156 35.88 0.245 36 ;
     RECT  0.192 36 0.245 36.024 ;
     RECT  0.156 36.024 0.245 36.192 ;
     RECT  0.192 36.192 0.245 36.216 ;
     RECT  0.156 36.216 0.245 36.384 ;
     RECT  0.192 36.384 0.245 36.408 ;
     RECT  0.156 36.408 0.245 36.528 ;
     RECT  0.192 36.528 0.245 36.552 ;
     RECT  0.156 36.552 0.245 36.72 ;
     RECT  0.192 36.72 0.245 36.744 ;
     RECT  0.156 36.744 0.245 36.864 ;
     RECT  0.192 36.864 0.245 36.888 ;
     RECT  0.156 36.888 0.245 37.056 ;
     RECT  0.192 37.056 0.245 37.08 ;
     RECT  0.156 37.08 0.245 37.2 ;
     RECT  0.192 37.2 0.245 37.224 ;
     RECT  0.156 37.224 0.245 37.392 ;
     RECT  0.192 37.392 0.245 37.416 ;
     RECT  0.156 37.416 0.245 37.584 ;
     RECT  0.192 37.584 0.245 37.608 ;
     RECT  0.156 37.608 0.245 37.728 ;
     RECT  0.192 37.728 0.245 37.752 ;
     RECT  0.156 37.752 0.245 37.92 ;
     RECT  0.192 37.92 0.245 37.944 ;
     RECT  0.156 37.944 0.245 38.064 ;
     RECT  0.192 38.064 0.245 38.088 ;
     RECT  0.156 38.088 0.245 38.256 ;
     RECT  0.192 38.256 0.245 38.28 ;
     RECT  0.156 38.28 0.245 38.448 ;
     RECT  0.192 38.448 0.245 38.472 ;
     RECT  0.156 38.472 0.245 38.592 ;
     RECT  0.192 38.592 0.245 38.616 ;
     RECT  0.156 38.616 0.245 38.784 ;
     RECT  0.192 38.784 0.245 38.808 ;
     RECT  0.156 38.808 0.245 38.928 ;
     RECT  0.192 38.928 0.245 38.952 ;
     RECT  0.156 38.952 0.245 39.12 ;
     RECT  0.192 39.12 0.245 39.144 ;
     RECT  0.156 39.144 0.245 39.264 ;
     RECT  0.192 39.264 0.245 39.288 ;
     RECT  0.156 39.288 0.245 39.456 ;
     RECT  0.192 39.456 0.245 39.48 ;
     RECT  0.156 39.48 0.245 39.648 ;
     RECT  0.192 39.648 0.245 39.672 ;
     RECT  0.156 39.672 0.245 39.792 ;
     RECT  0.192 39.792 0.245 39.816 ;
     RECT  0.156 39.816 0.245 39.984 ;
     RECT  0.192 39.984 0.245 40.008 ;
     RECT  0.156 40.008 0.245 40.128 ;
     RECT  0.192 40.128 0.245 40.152 ;
     RECT  0.156 40.152 0.245 40.32 ;
     RECT  0.192 40.32 0.245 40.344 ;
     RECT  0.156 40.344 0.245 40.464 ;
     RECT  0.192 40.464 0.245 40.488 ;
     RECT  0.156 40.488 0.245 40.656 ;
     RECT  0.192 40.656 0.245 40.68 ;
     RECT  0.156 40.68 0.245 40.848 ;
     RECT  0.192 40.848 0.245 40.872 ;
     RECT  0.156 40.872 0.245 40.992 ;
     RECT  0.192 40.992 0.245 41.016 ;
     RECT  0.156 41.016 0.245 41.184 ;
     RECT  0.192 41.184 0.245 41.208 ;
     RECT  0.156 41.208 0.245 41.328 ;
     RECT  0.192 41.328 0.245 41.352 ;
     RECT  0.156 41.352 0.245 41.52 ;
     RECT  0.192 41.52 0.245 41.544 ;
     RECT  0.156 41.544 0.245 41.712 ;
     RECT  0.192 41.712 0.245 41.736 ;
     RECT  0.156 41.736 0.245 41.856 ;
     RECT  0.192 41.856 0.245 41.88 ;
     RECT  0.156 41.88 0.245 42.048 ;
     RECT  0.192 42.048 0.245 42.072 ;
     RECT  0.156 42.072 0.245 42.192 ;
     RECT  0.192 42.192 0.245 42.216 ;
     RECT  0.156 42.216 0.245 42.384 ;
     RECT  0.192 42.384 0.245 42.408 ;
     RECT  0.156 42.408 0.245 42.528 ;
     RECT  0.192 42.528 0.245 42.552 ;
     RECT  0.156 42.552 0.245 42.72 ;
     RECT  0.192 42.72 0.245 42.744 ;
     RECT  0.156 42.744 0.245 42.912 ;
     RECT  0.192 42.912 0.245 42.936 ;
     RECT  0.156 42.936 0.245 43.056 ;
     RECT  0.192 43.056 0.245 43.08 ;
     RECT  0.156 43.08 0.245 43.248 ;
     RECT  0.192 43.248 0.245 43.272 ;
     RECT  0.156 43.272 0.245 43.392 ;
     RECT  0.192 43.392 0.245 43.416 ;
     RECT  0.156 43.416 0.245 43.584 ;
     RECT  0.192 43.584 0.245 43.608 ;
     RECT  0.156 43.608 0.245 43.728 ;
     RECT  0.192 43.728 0.245 43.752 ;
     RECT  0.156 43.752 0.245 43.92 ;
     RECT  0.192 43.92 0.245 43.944 ;
     RECT  0.156 43.944 0.245 44.112 ;
     RECT  0.192 44.112 0.245 44.136 ;
     RECT  0.156 44.136 0.245 44.256 ;
     RECT  0.192 44.256 0.245 44.28 ;
     RECT  0.156 44.28 0.245 44.448 ;
     RECT  0.192 44.448 0.245 44.472 ;
     RECT  0.156 44.472 0.245 44.592 ;
     RECT  0.192 44.592 0.245 44.616 ;
     RECT  0.156 44.616 0.245 44.784 ;
     RECT  0.192 44.784 0.245 44.808 ;
     RECT  0.156 44.808 0.245 44.976 ;
     RECT  0.192 44.976 0.245 45 ;
     RECT  0.156 45 0.245 45.12 ;
     RECT  0.192 45.12 0.245 45.144 ;
     RECT  0.156 45.144 0.245 45.312 ;
     RECT  0.192 45.312 0.245 45.336 ;
     RECT  0.156 45.336 0.245 45.456 ;
     RECT  0.192 45.456 0.245 45.48 ;
     RECT  0.156 45.48 0.245 45.648 ;
     RECT  0.192 45.648 0.245 45.672 ;
     RECT  0.156 45.672 0.245 45.792 ;
     RECT  0.192 45.792 0.245 45.816 ;
     RECT  0.156 45.816 0.245 45.984 ;
     RECT  0.192 45.984 0.245 46.008 ;
     RECT  0.156 46.008 0.245 46.176 ;
     RECT  0.192 46.176 0.245 46.2 ;
     RECT  0.156 46.2 0.245 46.32 ;
     RECT  0.192 46.32 0.245 46.344 ;
     RECT  0.156 46.344 0.245 46.512 ;
     RECT  0.192 46.512 0.245 46.536 ;
     RECT  0.156 46.536 0.245 46.656 ;
     RECT  0.192 46.656 0.245 46.68 ;
     RECT  0.156 46.68 0.245 46.848 ;
     RECT  0.192 46.848 0.245 46.872 ;
     RECT  0.156 46.872 0.245 46.992 ;
     RECT  0.192 46.992 0.245 47.016 ;
     RECT  0.156 47.016 0.245 47.184 ;
     RECT  0.192 47.184 0.245 47.208 ;
     RECT  0.156 47.208 0.245 47.376 ;
     RECT  0.192 47.376 0.245 47.4 ;
     RECT  0.156 47.4 0.245 47.52 ;
     RECT  0.192 47.52 0.245 47.544 ;
     RECT  0.156 47.544 0.245 47.712 ;
     RECT  0.192 47.712 0.245 47.736 ;
     RECT  0.156 47.736 0.245 47.856 ;
     RECT  0.192 47.856 0.245 47.88 ;
     RECT  0.156 47.88 0.245 48.048 ;
     RECT  0.192 48.048 0.245 48.072 ;
     RECT  0.156 48.072 0.245 48.24 ;
     RECT  0.192 48.24 0.245 48.264 ;
     RECT  0.156 48.264 0.245 48.384 ;
     RECT  0.192 48.384 0.245 48.408 ;
     RECT  0.156 48.408 0.245 48.576 ;
     RECT  0.192 48.576 0.245 48.6 ;
     RECT  0.156 48.6 0.245 48.72 ;
     RECT  0.192 48.72 0.245 48.744 ;
     RECT  0.156 48.744 0.245 48.912 ;
     RECT  0.192 48.912 0.245 48.936 ;
     RECT  0.156 48.936 0.245 49.056 ;
     RECT  0.192 49.056 0.245 49.08 ;
     RECT  0.156 49.08 0.245 49.248 ;
     RECT  0.192 49.248 0.245 49.272 ;
     RECT  0.156 49.272 0.245 49.44 ;
     RECT  0.192 49.44 0.245 49.464 ;
     RECT  0.156 49.464 0.245 49.584 ;
     RECT  0.192 49.584 0.245 49.608 ;
     RECT  0.156 49.608 0.245 49.776 ;
     RECT  0.192 49.776 0.245 49.8 ;
     RECT  0.156 49.8 0.245 49.92 ;
     RECT  0.192 49.92 0.245 49.944 ;
     RECT  0.156 49.944 0.245 50.112 ;
     RECT  0.192 50.112 0.245 50.136 ;
     RECT  0.156 50.136 0.245 50.256 ;
     RECT  0.192 50.256 0.245 50.28 ;
     RECT  0.156 50.28 0.245 50.448 ;
     RECT  0.192 50.448 0.245 50.472 ;
     RECT  0.156 50.472 0.245 50.64 ;
     RECT  0.192 50.64 0.245 50.664 ;
     RECT  0.156 50.664 0.245 50.784 ;
     RECT  0.192 50.784 0.245 50.808 ;
     RECT  0.156 50.808 0.245 50.976 ;
     RECT  0.192 50.976 0.245 51 ;
     RECT  0.156 51 0.245 51.12 ;
     RECT  0.192 51.12 0.245 51.144 ;
     RECT  0.156 51.144 0.245 51.312 ;
     RECT  0.192 51.312 0.245 51.336 ;
     RECT  0.156 51.336 0.245 51.504 ;
     RECT  0.192 51.504 0.245 51.528 ;
     RECT  0.156 51.528 0.245 51.648 ;
     RECT  0.192 51.648 0.245 51.672 ;
     RECT  0.245 4.704 0.281 51.672 ;
     RECT  0.281 4.896 2.408 51.672 ;
     RECT  2.408 2.148 2.512 54.012 ;
     RECT  2.512 2.418 2.704 53.742 ;
     RECT  2.704 16.368 2.765 21.144 ;
     RECT  2.704 23.088 2.801 51.672 ;
     RECT  2.765 16.368 2.819 19.896 ;
     RECT  2.801 23.088 2.867 51.384 ;
     RECT  2.867 23.088 2.873 39.48 ;
     RECT  2.704 11.136 2.909 12.648 ;
     RECT  2.704 14.112 2.909 15.288 ;
     RECT  2.704 6 3.017 8.232 ;
     RECT  2.704 9.36 3.017 10.152 ;
     RECT  2.819 16.512 3.197 19.896 ;
     RECT  3.197 18.192 3.251 19.896 ;
     RECT  2.909 11.232 3.269 12.648 ;
     RECT  3.251 18.192 3.269 19.848 ;
     RECT  3.269 11.232 3.305 12.552 ;
     RECT  2.909 15.264 3.305 15.288 ;
     RECT  2.873 23.088 3.305 26.232 ;
     RECT  3.017 6.672 3.413 8.232 ;
     RECT  3.305 11.712 3.413 12.552 ;
     RECT  3.413 11.808 3.449 12.552 ;
     RECT  3.305 24.768 3.491 26.232 ;
     RECT  3.413 6.72 3.521 8.232 ;
     RECT  2.765 20.928 3.769 21.144 ;
     RECT  3.017 9.36 3.917 9.816 ;
     RECT  3.305 23.088 3.985 23.112 ;
     RECT  3.805 14.016 4.021 14.04 ;
     RECT  2.873 27.36 4.025 39.48 ;
     RECT  3.769 20.928 4.061 21.48 ;
     RECT  3.491 26.208 4.117 26.232 ;
     RECT  4.025 27.36 4.117 30.936 ;
     RECT  4.453 5.088 4.501 5.112 ;
     RECT  3.449 11.952 4.525 11.976 ;
     RECT  3.521 6.768 4.549 7.416 ;
     RECT  3.925 8.688 4.549 8.808 ;
     RECT  3.197 16.512 4.561 16.536 ;
     RECT  3.269 18.192 4.597 18.216 ;
     RECT  4.061 21.456 4.597 21.48 ;
     RECT  3.985 22.656 4.597 23.112 ;
     RECT  4.501 4.848 4.633 5.112 ;
     RECT  3.491 24.768 4.645 24.792 ;
     RECT  4.117 26.208 4.645 30.936 ;
     RECT  4.597 17.808 4.669 18.216 ;
     RECT  3.269 19.392 4.669 19.848 ;
     RECT  4.645 24.768 4.693 30.936 ;
     RECT  4.669 17.808 4.7 19.848 ;
     RECT  4.525 11.232 4.705 11.976 ;
     RECT  4.693 24.528 4.885 30.936 ;
     RECT  4.633 4.656 5.108 5.112 ;
     RECT  4.549 6.768 5.108 8.808 ;
     RECT  4.057 9.84 5.108 9.864 ;
     RECT  4.705 11.232 5.108 12.408 ;
     RECT  4.021 14.016 5.108 14.856 ;
     RECT  4.561 15.984 5.108 16.536 ;
     RECT  4.7 17.808 5.108 20.232 ;
     RECT  4.597 21.456 5.108 23.112 ;
     RECT  4.885 24.384 5.108 30.936 ;
     RECT  4.025 31.92 5.108 33.144 ;
     RECT  4.025 34.128 5.108 39.48 ;
     RECT  2.867 40.656 5.108 51.384 ;
     RECT  5.108 2.148 5.212 54.012 ;
     RECT  5.212 2.418 5.404 53.742 ;
     RECT  5.404 45.216 5.645 46.776 ;
     RECT  5.404 50.64 5.681 50.664 ;
     RECT  5.404 34.656 5.717 38.28 ;
     RECT  5.404 40.656 5.753 43.608 ;
     RECT  5.404 10.8 5.969 10.872 ;
     RECT  5.753 40.656 6.157 43.368 ;
     RECT  5.404 11.952 6.227 12.504 ;
     RECT  6.227 11.952 6.268 12.36 ;
     RECT  5.404 33.408 6.275 33.432 ;
     RECT  5.404 18.192 6.293 21.48 ;
     RECT  5.969 10.8 6.301 10.824 ;
     RECT  6.293 18.192 6.371 19.368 ;
     RECT  5.404 4.656 6.397 5.112 ;
     RECT  6.373 6.096 6.397 6.12 ;
     RECT  6.397 4.656 6.401 6.12 ;
     RECT  5.404 14.112 6.408 14.136 ;
     RECT  6.401 5.088 6.46 6.12 ;
     RECT  5.404 8.496 6.469 8.808 ;
     RECT  6.268 11.952 6.515 11.976 ;
     RECT  5.404 22.992 6.515 25.608 ;
     RECT  5.404 47.856 6.515 47.976 ;
     RECT  6.515 22.992 6.517 24.6 ;
     RECT  6.408 13.632 6.541 14.136 ;
     RECT  5.404 15.552 6.541 17.064 ;
     RECT  5.404 30.624 6.577 30.888 ;
     RECT  6.157 40.656 6.617 43.128 ;
     RECT  5.404 28.416 6.649 29.352 ;
     RECT  6.469 8.496 6.653 9.576 ;
     RECT  5.645 46.752 6.653 46.776 ;
     RECT  6.515 47.856 6.689 47.88 ;
     RECT  6.577 30.624 6.725 31.176 ;
     RECT  6.293 20.448 6.755 21.48 ;
     RECT  5.404 26.592 6.793 27.192 ;
     RECT  6.541 13.632 6.797 17.064 ;
     RECT  6.515 25.584 6.829 25.608 ;
     RECT  6.793 26.592 6.829 27.336 ;
     RECT  6.46 5.088 6.833 5.928 ;
     RECT  6.649 28.32 6.833 29.352 ;
     RECT  6.517 22.848 6.973 24.6 ;
     RECT  5.717 35.328 7.141 38.28 ;
     RECT  6.725 30.624 7.217 30.888 ;
     RECT  6.829 25.584 7.225 27.336 ;
     RECT  7.141 34.56 7.285 38.28 ;
     RECT  6.829 17.376 7.333 17.4 ;
     RECT  7.285 34.56 7.333 39 ;
     RECT  6.617 40.656 7.333 41.208 ;
     RECT  6.833 29.328 7.381 29.352 ;
     RECT  7.217 30.48 7.381 30.888 ;
     RECT  6.973 22.8 7.441 24.6 ;
     RECT  7.441 22.752 7.477 24.6 ;
     RECT  7.225 25.584 7.477 28.296 ;
     RECT  6.617 42.384 7.541 43.128 ;
     RECT  6.973 7.152 7.585 7.176 ;
     RECT  6.755 20.496 7.621 21.48 ;
     RECT  5.645 45.216 7.621 45.24 ;
     RECT  7.525 46.8 7.649 46.824 ;
     RECT  7.585 7.152 7.765 7.656 ;
     RECT  6.653 8.784 7.765 9.576 ;
     RECT  6.797 13.632 7.801 16.344 ;
     RECT  7.333 17.376 7.801 17.688 ;
     RECT  6.833 5.088 7.808 5.112 ;
     RECT  7.765 7.152 7.808 10.2 ;
     RECT  7.141 11.232 7.808 11.256 ;
     RECT  7.801 13.632 7.808 17.688 ;
     RECT  6.371 18.816 7.808 19.368 ;
     RECT  7.621 20.496 7.808 21.528 ;
     RECT  7.477 22.752 7.808 28.296 ;
     RECT  7.381 29.328 7.808 30.888 ;
     RECT  7.189 31.968 7.808 31.992 ;
     RECT  7.333 34.56 7.808 41.208 ;
     RECT  7.541 42.384 7.808 43.368 ;
     RECT  7.621 44.832 7.808 45.24 ;
     RECT  7.649 46.752 7.808 46.824 ;
     RECT  5.404 49.296 7.808 49.32 ;
     RECT  7.808 2.148 7.912 54.012 ;
     RECT  7.912 2.418 8.104 53.742 ;
     RECT  8.104 22.704 8.129 23.4 ;
     RECT  8.104 14.64 8.165 17.64 ;
     RECT  8.104 18.72 8.165 18.84 ;
     RECT  8.104 7.632 8.237 7.992 ;
     RECT  8.104 25.536 8.243 28.44 ;
     RECT  8.104 9.36 8.309 10.2 ;
     RECT  8.104 20.688 8.381 20.712 ;
     RECT  8.104 36.288 8.525 36.312 ;
     RECT  8.243 26.352 8.921 28.296 ;
     RECT  8.165 14.64 8.993 17.208 ;
     RECT  8.309 10.176 9.029 10.2 ;
     RECT  8.993 14.64 9.029 16.344 ;
     RECT  8.165 18.816 9.065 18.84 ;
     RECT  8.104 30.864 9.137 30.888 ;
     RECT  8.129 22.704 9.424 22.728 ;
     RECT  8.921 26.352 9.491 27.336 ;
     RECT  9.424 22.704 9.493 22.776 ;
     RECT  9.493 22.656 9.539 22.776 ;
     RECT  10.429 1.728 10.508 1.752 ;
     RECT  8.237 7.968 10.508 7.992 ;
     RECT  9.029 14.64 10.508 14.664 ;
     RECT  9.029 15.984 10.508 16.344 ;
     RECT  9.539 22.656 10.508 22.728 ;
     RECT  10.465 25.44 10.508 25.464 ;
     RECT  9.491 26.64 10.508 27.336 ;
     RECT  8.104 40.656 10.508 40.68 ;
     RECT  10.508 1.728 10.612 54.012 ;
     RECT  10.612 1.728 10.804 53.742 ;
     RECT  10.804 1.728 10.835 1.752 ;
     RECT  10.804 14.64 13.208 14.664 ;
     RECT  10.804 15.984 13.208 16.344 ;
     RECT  10.804 26.64 13.208 27.336 ;
     RECT  10.804 40.656 13.208 40.68 ;
     RECT  13.208 2.148 13.312 54.012 ;
     RECT  13.312 2.418 13.504 53.742 ;
     RECT  13.504 26.64 14.861 27.336 ;
     RECT  15.217 7.968 15.908 7.992 ;
     RECT  15.289 11.52 15.908 11.544 ;
     RECT  13.504 14.64 15.908 14.664 ;
     RECT  13.504 15.984 15.908 16.344 ;
     RECT  15.289 19.824 15.908 19.848 ;
     RECT  15.361 21.696 15.908 21.72 ;
     RECT  15.217 24.48 15.908 24.504 ;
     RECT  14.861 26.64 15.908 27.192 ;
     RECT  15.325 33.888 15.908 33.912 ;
     RECT  13.504 40.656 15.908 40.68 ;
     RECT  15.865 42.72 15.908 42.744 ;
     RECT  15.908 2.148 16.012 54.012 ;
     RECT  16.012 2.418 16.204 53.742 ;
     RECT  16.204 7.968 18.608 7.992 ;
     RECT  16.204 11.52 18.608 11.544 ;
     RECT  16.204 14.64 18.608 14.664 ;
     RECT  16.204 16.32 18.608 16.344 ;
     RECT  16.204 19.824 18.608 19.848 ;
     RECT  16.204 21.696 18.608 21.72 ;
     RECT  16.204 24.48 18.608 24.504 ;
     RECT  16.204 26.64 18.608 27.192 ;
     RECT  16.204 33.888 18.608 33.912 ;
     RECT  16.204 40.656 18.608 40.68 ;
     RECT  18.608 2.148 18.712 54.012 ;
     RECT  18.712 2.418 18.904 53.742 ;
     RECT  18.904 10.704 19.897 12.12 ;
     RECT  18.904 4.512 19.933 7.992 ;
     RECT  19.897 10.56 19.933 12.12 ;
     RECT  18.904 13.44 19.933 17.448 ;
     RECT  18.904 19.488 19.933 22.776 ;
     RECT  18.904 23.952 19.933 25.32 ;
     RECT  18.904 29.136 19.933 29.16 ;
     RECT  18.904 30.192 19.933 31.416 ;
     RECT  18.904 33.12 19.933 35.88 ;
     RECT  18.904 37.584 19.933 37.944 ;
     RECT  18.904 38.928 19.933 41.736 ;
     RECT  18.904 42.72 19.933 45.336 ;
     RECT  18.904 46.512 19.933 46.872 ;
     RECT  18.904 49.056 19.933 50.808 ;
     RECT  19.933 32.928 19.969 47.736 ;
     RECT  19.933 48.72 19.969 51.672 ;
     RECT  18.904 26.496 20.113 26.904 ;
     RECT  19.933 4.512 20.437 8.52 ;
     RECT  19.933 9.696 20.437 25.32 ;
     RECT  20.437 4.512 20.473 25.32 ;
     RECT  20.113 26.352 20.473 26.904 ;
     RECT  20.473 4.512 20.509 27.576 ;
     RECT  19.933 28.8 20.509 31.416 ;
     RECT  19.969 32.928 20.509 51.672 ;
     RECT  20.509 4.512 21.408 4.536 ;
     RECT  20.509 4.536 21.42 4.704 ;
     RECT  20.509 4.704 21.408 4.728 ;
     RECT  20.509 4.728 21.42 4.896 ;
     RECT  20.509 4.896 21.408 4.92 ;
     RECT  20.509 4.92 21.42 5.04 ;
     RECT  20.509 5.04 21.408 5.064 ;
     RECT  20.509 5.064 21.42 5.232 ;
     RECT  20.509 5.232 21.408 5.256 ;
     RECT  20.509 5.256 21.42 5.376 ;
     RECT  20.509 5.376 21.408 5.4 ;
     RECT  20.509 5.4 21.42 5.568 ;
     RECT  20.509 5.568 21.408 5.592 ;
     RECT  20.509 5.592 21.42 5.712 ;
     RECT  20.509 5.712 21.408 5.736 ;
     RECT  20.509 5.736 21.42 5.904 ;
     RECT  20.509 5.904 21.408 5.928 ;
     RECT  20.509 5.928 21.42 6.096 ;
     RECT  20.509 6.096 21.408 6.12 ;
     RECT  20.509 6.12 21.42 6.24 ;
     RECT  20.509 6.24 21.408 6.264 ;
     RECT  20.509 6.264 21.42 6.432 ;
     RECT  20.509 6.432 21.408 6.456 ;
     RECT  20.509 6.456 21.42 6.576 ;
     RECT  20.509 6.576 21.408 6.6 ;
     RECT  20.509 6.6 21.42 6.768 ;
     RECT  20.509 6.768 21.408 6.792 ;
     RECT  20.509 6.792 21.42 6.96 ;
     RECT  20.509 6.96 21.408 6.984 ;
     RECT  20.509 6.984 21.42 7.104 ;
     RECT  20.509 7.104 21.408 7.128 ;
     RECT  20.509 7.128 21.42 7.296 ;
     RECT  20.509 7.296 21.408 7.32 ;
     RECT  20.509 7.32 21.42 7.44 ;
     RECT  20.509 7.44 21.408 7.464 ;
     RECT  20.509 7.464 21.42 7.632 ;
     RECT  20.509 7.632 21.408 7.656 ;
     RECT  20.509 7.656 21.42 7.776 ;
     RECT  20.509 7.776 21.408 7.8 ;
     RECT  20.509 7.8 21.42 7.968 ;
     RECT  20.509 7.968 21.408 7.992 ;
     RECT  20.509 7.992 21.42 8.16 ;
     RECT  20.509 8.16 21.408 8.184 ;
     RECT  20.509 8.184 21.42 8.304 ;
     RECT  20.509 8.304 21.408 8.328 ;
     RECT  20.509 8.328 21.42 8.496 ;
     RECT  20.509 8.496 21.408 8.52 ;
     RECT  20.509 8.52 21.42 8.64 ;
     RECT  20.509 8.64 21.408 8.664 ;
     RECT  20.509 8.664 21.42 8.832 ;
     RECT  20.509 8.832 21.408 8.856 ;
     RECT  20.509 8.856 21.42 8.976 ;
     RECT  20.509 8.976 21.408 9 ;
     RECT  20.509 9 21.42 9.168 ;
     RECT  20.509 9.168 21.408 9.192 ;
     RECT  20.509 9.192 21.42 9.36 ;
     RECT  20.509 9.36 21.408 9.384 ;
     RECT  20.509 9.384 21.42 9.504 ;
     RECT  20.509 9.504 21.408 9.528 ;
     RECT  20.509 9.528 21.42 9.696 ;
     RECT  20.509 9.696 21.408 9.72 ;
     RECT  20.509 9.72 21.42 9.84 ;
     RECT  20.509 9.84 21.408 9.864 ;
     RECT  20.509 9.864 21.42 10.032 ;
     RECT  20.509 10.032 21.408 10.056 ;
     RECT  20.509 10.056 21.42 10.224 ;
     RECT  20.509 10.224 21.408 10.248 ;
     RECT  20.509 10.248 21.42 10.368 ;
     RECT  20.509 10.368 21.408 10.392 ;
     RECT  20.509 10.392 21.42 10.56 ;
     RECT  20.509 10.56 21.408 10.584 ;
     RECT  20.509 10.584 21.42 10.704 ;
     RECT  20.509 10.704 21.408 10.728 ;
     RECT  20.509 10.728 21.42 10.896 ;
     RECT  20.509 10.896 21.408 10.92 ;
     RECT  20.509 10.92 21.42 11.04 ;
     RECT  20.509 11.04 21.408 11.064 ;
     RECT  20.509 11.064 21.42 11.232 ;
     RECT  20.509 11.232 21.408 11.256 ;
     RECT  20.509 11.256 21.42 11.424 ;
     RECT  20.509 11.424 21.408 11.448 ;
     RECT  20.509 11.448 21.42 11.568 ;
     RECT  20.509 11.568 21.408 11.592 ;
     RECT  20.509 11.592 21.42 11.76 ;
     RECT  20.509 11.76 21.408 11.784 ;
     RECT  20.509 11.784 21.42 11.904 ;
     RECT  20.509 11.904 21.408 11.928 ;
     RECT  20.509 11.928 21.42 12.096 ;
     RECT  20.509 12.096 21.408 12.12 ;
     RECT  20.509 12.12 21.42 12.24 ;
     RECT  20.509 12.24 21.408 12.264 ;
     RECT  20.509 12.264 21.42 12.432 ;
     RECT  20.509 12.432 21.408 12.456 ;
     RECT  20.509 12.456 21.42 12.624 ;
     RECT  20.509 12.624 21.408 12.648 ;
     RECT  20.509 12.648 21.42 12.768 ;
     RECT  20.509 12.768 21.408 12.792 ;
     RECT  20.509 12.792 21.42 12.96 ;
     RECT  20.509 12.96 21.408 12.984 ;
     RECT  20.509 12.984 21.42 13.104 ;
     RECT  20.509 13.104 21.408 13.128 ;
     RECT  20.509 13.128 21.42 13.296 ;
     RECT  20.509 13.296 21.408 13.32 ;
     RECT  20.509 13.32 21.42 13.44 ;
     RECT  20.509 13.44 21.408 13.464 ;
     RECT  20.509 13.464 21.42 13.632 ;
     RECT  20.509 13.632 21.408 13.656 ;
     RECT  20.509 13.656 21.42 13.824 ;
     RECT  20.509 13.824 21.408 13.848 ;
     RECT  20.509 13.848 21.42 13.968 ;
     RECT  20.509 13.968 21.408 13.992 ;
     RECT  20.509 13.992 21.42 14.16 ;
     RECT  20.509 14.16 21.408 14.184 ;
     RECT  20.509 14.184 21.42 14.304 ;
     RECT  20.509 14.304 21.408 14.328 ;
     RECT  20.509 14.328 21.42 14.496 ;
     RECT  20.509 14.496 21.408 14.52 ;
     RECT  20.509 14.52 21.42 14.688 ;
     RECT  20.509 14.688 21.408 14.712 ;
     RECT  20.509 14.712 21.42 14.832 ;
     RECT  20.509 14.832 21.408 14.856 ;
     RECT  20.509 14.856 21.42 15.024 ;
     RECT  20.509 15.024 21.408 15.048 ;
     RECT  20.509 15.048 21.42 15.168 ;
     RECT  20.509 15.168 21.408 15.192 ;
     RECT  20.509 15.192 21.42 15.36 ;
     RECT  20.509 15.36 21.408 15.384 ;
     RECT  20.509 15.384 21.42 15.504 ;
     RECT  20.509 15.504 21.408 15.528 ;
     RECT  20.509 15.528 21.42 15.696 ;
     RECT  20.509 15.696 21.408 15.72 ;
     RECT  20.509 15.72 21.42 15.888 ;
     RECT  20.509 15.888 21.408 15.912 ;
     RECT  20.509 15.912 21.42 16.032 ;
     RECT  20.509 16.032 21.408 16.056 ;
     RECT  20.509 16.056 21.42 16.224 ;
     RECT  20.509 16.224 21.408 16.248 ;
     RECT  20.509 16.248 21.42 16.368 ;
     RECT  20.509 16.368 21.408 16.392 ;
     RECT  20.509 16.392 21.42 16.56 ;
     RECT  20.509 16.56 21.408 16.584 ;
     RECT  20.509 16.584 21.42 16.704 ;
     RECT  20.509 16.704 21.408 16.728 ;
     RECT  20.509 16.728 21.42 16.896 ;
     RECT  20.509 16.896 21.408 16.92 ;
     RECT  20.509 16.92 21.42 17.088 ;
     RECT  20.509 17.088 21.408 17.112 ;
     RECT  20.509 17.112 21.42 17.232 ;
     RECT  20.509 17.232 21.408 17.256 ;
     RECT  20.509 17.256 21.42 17.424 ;
     RECT  20.509 17.424 21.408 17.448 ;
     RECT  20.509 17.448 21.42 17.568 ;
     RECT  20.509 17.568 21.408 17.592 ;
     RECT  20.509 17.592 21.42 17.76 ;
     RECT  20.509 17.76 21.408 17.784 ;
     RECT  20.509 17.784 21.42 17.952 ;
     RECT  20.509 17.952 21.408 17.976 ;
     RECT  20.509 17.976 21.42 18.096 ;
     RECT  20.509 18.096 21.408 18.12 ;
     RECT  20.509 18.12 21.42 18.288 ;
     RECT  20.509 18.288 21.408 18.312 ;
     RECT  20.509 18.312 21.42 18.432 ;
     RECT  20.509 18.432 21.408 18.456 ;
     RECT  20.509 18.456 21.42 18.624 ;
     RECT  20.509 18.624 21.408 18.648 ;
     RECT  20.509 18.648 21.42 18.768 ;
     RECT  20.509 18.768 21.408 18.792 ;
     RECT  20.509 18.792 21.42 18.96 ;
     RECT  20.509 18.96 21.408 18.984 ;
     RECT  20.509 18.984 21.42 19.152 ;
     RECT  20.509 19.152 21.408 19.176 ;
     RECT  20.509 19.176 21.42 19.296 ;
     RECT  20.509 19.296 21.408 19.32 ;
     RECT  20.509 19.32 21.42 19.488 ;
     RECT  20.509 19.488 21.408 19.512 ;
     RECT  20.509 19.512 21.42 19.632 ;
     RECT  20.509 19.632 21.408 19.656 ;
     RECT  20.509 19.656 21.42 19.824 ;
     RECT  20.509 19.824 21.408 19.848 ;
     RECT  20.509 19.848 21.42 19.968 ;
     RECT  20.509 19.968 21.408 19.992 ;
     RECT  20.509 19.992 21.42 20.16 ;
     RECT  20.509 20.16 21.408 20.184 ;
     RECT  20.509 20.184 21.42 20.352 ;
     RECT  20.509 20.352 21.408 20.376 ;
     RECT  20.509 20.376 21.42 20.496 ;
     RECT  20.509 20.496 21.408 20.52 ;
     RECT  20.509 20.52 21.42 20.688 ;
     RECT  20.509 20.688 21.408 20.712 ;
     RECT  20.509 20.712 21.42 20.832 ;
     RECT  20.509 20.832 21.408 20.856 ;
     RECT  20.509 20.856 21.42 21.024 ;
     RECT  20.509 21.024 21.408 21.048 ;
     RECT  20.509 21.048 21.42 21.216 ;
     RECT  20.509 21.216 21.408 21.24 ;
     RECT  20.509 21.24 21.42 21.36 ;
     RECT  20.509 21.36 21.408 21.384 ;
     RECT  20.509 21.384 21.42 21.552 ;
     RECT  20.509 21.552 21.408 21.576 ;
     RECT  20.509 21.576 21.42 21.696 ;
     RECT  20.509 21.696 21.408 21.72 ;
     RECT  20.509 21.72 21.42 21.888 ;
     RECT  20.509 21.888 21.408 21.912 ;
     RECT  20.509 21.912 21.42 22.032 ;
     RECT  20.509 22.032 21.408 22.056 ;
     RECT  20.509 22.056 21.42 22.224 ;
     RECT  20.509 22.224 21.408 22.248 ;
     RECT  20.509 22.248 21.42 22.416 ;
     RECT  20.509 22.416 21.408 22.44 ;
     RECT  20.509 22.44 21.42 22.56 ;
     RECT  20.509 22.56 21.408 22.584 ;
     RECT  20.509 22.584 21.42 22.752 ;
     RECT  20.509 22.752 21.408 22.776 ;
     RECT  20.509 22.776 21.42 22.896 ;
     RECT  20.509 22.896 21.408 22.92 ;
     RECT  20.509 22.92 21.42 23.088 ;
     RECT  20.509 23.088 21.408 23.112 ;
     RECT  20.509 23.112 21.42 23.232 ;
     RECT  20.509 23.232 21.408 23.256 ;
     RECT  20.509 23.256 21.42 23.424 ;
     RECT  20.509 23.424 21.408 23.448 ;
     RECT  20.509 23.448 21.42 23.616 ;
     RECT  20.509 23.616 21.408 23.64 ;
     RECT  20.509 23.64 21.42 23.76 ;
     RECT  20.509 23.76 21.408 23.784 ;
     RECT  20.509 23.784 21.42 23.952 ;
     RECT  20.509 23.952 21.408 23.976 ;
     RECT  20.509 23.976 21.42 24.096 ;
     RECT  20.509 24.096 21.408 24.12 ;
     RECT  20.509 24.12 21.42 24.288 ;
     RECT  20.509 24.288 21.408 24.312 ;
     RECT  20.509 24.312 21.42 24.48 ;
     RECT  20.509 24.48 21.408 24.504 ;
     RECT  20.509 24.504 21.42 24.624 ;
     RECT  20.509 24.624 21.408 24.648 ;
     RECT  20.509 24.648 21.42 24.816 ;
     RECT  20.509 24.816 21.408 24.84 ;
     RECT  20.509 24.84 21.42 24.96 ;
     RECT  20.509 24.96 21.408 24.984 ;
     RECT  20.509 24.984 21.42 25.152 ;
     RECT  20.509 25.152 21.408 25.176 ;
     RECT  20.509 25.176 21.42 25.296 ;
     RECT  20.509 25.296 21.408 25.32 ;
     RECT  20.509 25.32 21.42 25.488 ;
     RECT  20.509 25.488 21.408 25.512 ;
     RECT  20.509 25.512 21.42 25.68 ;
     RECT  20.509 25.68 21.408 25.704 ;
     RECT  20.509 25.704 21.42 25.824 ;
     RECT  20.509 25.824 21.408 25.848 ;
     RECT  20.509 25.848 21.42 26.016 ;
     RECT  20.509 26.016 21.408 26.04 ;
     RECT  20.509 26.04 21.42 26.16 ;
     RECT  20.509 26.16 21.408 26.184 ;
     RECT  20.509 26.184 21.42 26.352 ;
     RECT  20.509 26.352 21.408 26.376 ;
     RECT  20.509 26.376 21.42 26.496 ;
     RECT  20.509 26.496 21.408 26.52 ;
     RECT  20.509 26.52 21.42 26.688 ;
     RECT  20.509 26.688 21.408 26.712 ;
     RECT  20.509 26.712 21.42 26.88 ;
     RECT  20.509 26.88 21.408 26.904 ;
     RECT  20.509 26.904 21.42 27.024 ;
     RECT  20.509 27.024 21.408 27.048 ;
     RECT  20.509 27.048 21.42 27.216 ;
     RECT  20.509 27.216 21.408 27.24 ;
     RECT  20.509 27.24 21.42 27.36 ;
     RECT  20.509 27.36 21.408 27.384 ;
     RECT  20.509 27.384 21.42 27.552 ;
     RECT  20.509 27.552 21.408 27.576 ;
     RECT  20.509 27.576 21.42 27.744 ;
     RECT  20.509 27.744 21.408 27.768 ;
     RECT  20.509 27.768 21.42 27.888 ;
     RECT  20.509 27.888 21.408 27.912 ;
     RECT  20.509 27.912 21.42 28.272 ;
     RECT  20.509 28.272 21.408 28.296 ;
     RECT  20.509 28.296 21.42 28.464 ;
     RECT  20.509 28.464 21.408 28.488 ;
     RECT  20.509 28.488 21.42 28.656 ;
     RECT  20.509 28.656 21.408 28.68 ;
     RECT  20.509 28.68 21.42 28.8 ;
     RECT  20.509 28.8 21.408 28.824 ;
     RECT  20.509 28.824 21.42 28.992 ;
     RECT  20.509 28.992 21.408 29.016 ;
     RECT  20.509 29.016 21.42 29.136 ;
     RECT  20.509 29.136 21.408 29.16 ;
     RECT  20.509 29.16 21.42 29.328 ;
     RECT  20.509 29.328 21.408 29.352 ;
     RECT  20.509 29.352 21.42 29.472 ;
     RECT  20.509 29.472 21.408 29.496 ;
     RECT  20.509 29.496 21.42 29.664 ;
     RECT  20.509 29.664 21.408 29.688 ;
     RECT  20.509 29.688 21.42 29.856 ;
     RECT  20.509 29.856 21.408 29.88 ;
     RECT  20.509 29.88 21.42 30 ;
     RECT  20.509 30 21.408 30.024 ;
     RECT  20.509 30.024 21.42 30.192 ;
     RECT  20.509 30.192 21.408 30.216 ;
     RECT  20.509 30.216 21.42 30.336 ;
     RECT  20.509 30.336 21.408 30.36 ;
     RECT  20.509 30.36 21.42 30.528 ;
     RECT  20.509 30.528 21.408 30.552 ;
     RECT  20.509 30.552 21.42 30.72 ;
     RECT  20.509 30.72 21.408 30.744 ;
     RECT  20.509 30.744 21.42 30.864 ;
     RECT  20.509 30.864 21.408 30.888 ;
     RECT  20.509 30.888 21.42 31.056 ;
     RECT  20.509 31.056 21.408 31.08 ;
     RECT  20.509 31.08 21.42 31.2 ;
     RECT  20.509 31.2 21.408 31.224 ;
     RECT  20.509 31.224 21.42 31.392 ;
     RECT  20.509 31.392 21.408 31.416 ;
     RECT  20.509 31.416 21.42 31.536 ;
     RECT  20.509 31.536 21.408 31.56 ;
     RECT  20.509 31.56 21.42 31.728 ;
     RECT  20.509 31.728 21.408 31.752 ;
     RECT  20.509 31.752 21.42 31.92 ;
     RECT  20.509 31.92 21.408 31.944 ;
     RECT  20.509 31.944 21.42 32.064 ;
     RECT  20.509 32.064 21.408 32.088 ;
     RECT  20.509 32.088 21.42 32.256 ;
     RECT  20.509 32.256 21.408 32.28 ;
     RECT  20.509 32.28 21.42 32.4 ;
     RECT  20.509 32.4 21.408 32.424 ;
     RECT  20.509 32.424 21.42 32.592 ;
     RECT  20.509 32.592 21.408 32.616 ;
     RECT  20.509 32.616 21.42 32.736 ;
     RECT  20.509 32.736 21.408 32.76 ;
     RECT  20.509 32.76 21.42 32.928 ;
     RECT  20.509 32.928 21.408 32.952 ;
     RECT  20.509 32.952 21.42 33.12 ;
     RECT  20.509 33.12 21.408 33.144 ;
     RECT  20.509 33.144 21.42 33.264 ;
     RECT  20.509 33.264 21.408 33.288 ;
     RECT  20.509 33.288 21.42 33.456 ;
     RECT  20.509 33.456 21.408 33.48 ;
     RECT  20.509 33.48 21.42 33.6 ;
     RECT  20.509 33.6 21.408 33.624 ;
     RECT  20.509 33.624 21.42 33.792 ;
     RECT  20.509 33.792 21.408 33.816 ;
     RECT  20.509 33.816 21.42 33.984 ;
     RECT  20.509 33.984 21.408 34.008 ;
     RECT  20.509 34.008 21.42 34.128 ;
     RECT  20.509 34.128 21.408 34.152 ;
     RECT  20.509 34.152 21.42 34.32 ;
     RECT  20.509 34.32 21.408 34.344 ;
     RECT  20.509 34.344 21.42 34.464 ;
     RECT  20.509 34.464 21.408 34.488 ;
     RECT  20.509 34.488 21.42 34.656 ;
     RECT  20.509 34.656 21.408 34.68 ;
     RECT  20.509 34.68 21.42 34.8 ;
     RECT  20.509 34.8 21.408 34.824 ;
     RECT  20.509 34.824 21.42 34.992 ;
     RECT  20.509 34.992 21.408 35.016 ;
     RECT  20.509 35.016 21.42 35.184 ;
     RECT  20.509 35.184 21.408 35.208 ;
     RECT  20.509 35.208 21.42 35.328 ;
     RECT  20.509 35.328 21.408 35.352 ;
     RECT  20.509 35.352 21.42 35.52 ;
     RECT  20.509 35.52 21.408 35.544 ;
     RECT  20.509 35.544 21.42 35.664 ;
     RECT  20.509 35.664 21.408 35.688 ;
     RECT  20.509 35.688 21.42 35.856 ;
     RECT  20.509 35.856 21.408 35.88 ;
     RECT  20.509 35.88 21.42 36 ;
     RECT  20.509 36 21.408 36.024 ;
     RECT  20.509 36.024 21.42 36.192 ;
     RECT  20.509 36.192 21.408 36.216 ;
     RECT  20.509 36.216 21.42 36.384 ;
     RECT  20.509 36.384 21.408 36.408 ;
     RECT  20.509 36.408 21.42 36.528 ;
     RECT  20.509 36.528 21.408 36.552 ;
     RECT  20.509 36.552 21.42 36.72 ;
     RECT  20.509 36.72 21.408 36.744 ;
     RECT  20.509 36.744 21.42 36.864 ;
     RECT  20.509 36.864 21.408 36.888 ;
     RECT  20.509 36.888 21.42 37.056 ;
     RECT  20.509 37.056 21.408 37.08 ;
     RECT  20.509 37.08 21.42 37.2 ;
     RECT  20.509 37.2 21.408 37.224 ;
     RECT  20.509 37.224 21.42 37.392 ;
     RECT  20.509 37.392 21.408 37.416 ;
     RECT  20.509 37.416 21.42 37.584 ;
     RECT  20.509 37.584 21.408 37.608 ;
     RECT  20.509 37.608 21.42 37.728 ;
     RECT  20.509 37.728 21.408 37.752 ;
     RECT  20.509 37.752 21.42 37.92 ;
     RECT  20.509 37.92 21.408 37.944 ;
     RECT  20.509 37.944 21.42 38.064 ;
     RECT  20.509 38.064 21.408 38.088 ;
     RECT  20.509 38.088 21.42 38.256 ;
     RECT  20.509 38.256 21.408 38.28 ;
     RECT  20.509 38.28 21.42 38.448 ;
     RECT  20.509 38.448 21.408 38.472 ;
     RECT  20.509 38.472 21.42 38.592 ;
     RECT  20.509 38.592 21.408 38.616 ;
     RECT  20.509 38.616 21.42 38.784 ;
     RECT  20.509 38.784 21.408 38.808 ;
     RECT  20.509 38.808 21.42 38.928 ;
     RECT  20.509 38.928 21.408 38.952 ;
     RECT  20.509 38.952 21.42 39.12 ;
     RECT  20.509 39.12 21.408 39.144 ;
     RECT  20.509 39.144 21.42 39.264 ;
     RECT  20.509 39.264 21.408 39.288 ;
     RECT  20.509 39.288 21.42 39.456 ;
     RECT  20.509 39.456 21.408 39.48 ;
     RECT  20.509 39.48 21.42 39.648 ;
     RECT  20.509 39.648 21.408 39.672 ;
     RECT  20.509 39.672 21.42 39.792 ;
     RECT  20.509 39.792 21.408 39.816 ;
     RECT  20.509 39.816 21.42 39.984 ;
     RECT  20.509 39.984 21.408 40.008 ;
     RECT  20.509 40.008 21.42 40.128 ;
     RECT  20.509 40.128 21.408 40.152 ;
     RECT  20.509 40.152 21.42 40.32 ;
     RECT  20.509 40.32 21.408 40.344 ;
     RECT  20.509 40.344 21.42 40.464 ;
     RECT  20.509 40.464 21.408 40.488 ;
     RECT  20.509 40.488 21.42 40.656 ;
     RECT  20.509 40.656 21.408 40.68 ;
     RECT  20.509 40.68 21.42 40.848 ;
     RECT  20.509 40.848 21.408 40.872 ;
     RECT  20.509 40.872 21.42 40.992 ;
     RECT  20.509 40.992 21.408 41.016 ;
     RECT  20.509 41.016 21.42 41.184 ;
     RECT  20.509 41.184 21.408 41.208 ;
     RECT  20.509 41.208 21.42 41.328 ;
     RECT  20.509 41.328 21.408 41.352 ;
     RECT  20.509 41.352 21.42 41.52 ;
     RECT  20.509 41.52 21.408 41.544 ;
     RECT  20.509 41.544 21.42 41.712 ;
     RECT  20.509 41.712 21.408 41.736 ;
     RECT  20.509 41.736 21.42 41.856 ;
     RECT  20.509 41.856 21.408 41.88 ;
     RECT  20.509 41.88 21.42 42.048 ;
     RECT  20.509 42.048 21.408 42.072 ;
     RECT  20.509 42.072 21.42 42.192 ;
     RECT  20.509 42.192 21.408 42.216 ;
     RECT  20.509 42.216 21.42 42.384 ;
     RECT  20.509 42.384 21.408 42.408 ;
     RECT  20.509 42.408 21.42 42.528 ;
     RECT  20.509 42.528 21.408 42.552 ;
     RECT  20.509 42.552 21.42 42.72 ;
     RECT  20.509 42.72 21.408 42.744 ;
     RECT  20.509 42.744 21.42 42.912 ;
     RECT  20.509 42.912 21.408 42.936 ;
     RECT  20.509 42.936 21.42 43.056 ;
     RECT  20.509 43.056 21.408 43.08 ;
     RECT  20.509 43.08 21.42 43.248 ;
     RECT  20.509 43.248 21.408 43.272 ;
     RECT  20.509 43.272 21.42 43.392 ;
     RECT  20.509 43.392 21.408 43.416 ;
     RECT  20.509 43.416 21.42 43.584 ;
     RECT  20.509 43.584 21.408 43.608 ;
     RECT  20.509 43.608 21.42 43.728 ;
     RECT  20.509 43.728 21.408 43.752 ;
     RECT  20.509 43.752 21.42 43.92 ;
     RECT  20.509 43.92 21.408 43.944 ;
     RECT  20.509 43.944 21.42 44.112 ;
     RECT  20.509 44.112 21.408 44.136 ;
     RECT  20.509 44.136 21.42 44.256 ;
     RECT  20.509 44.256 21.408 44.28 ;
     RECT  20.509 44.28 21.42 44.448 ;
     RECT  20.509 44.448 21.408 44.472 ;
     RECT  20.509 44.472 21.42 44.592 ;
     RECT  20.509 44.592 21.408 44.616 ;
     RECT  20.509 44.616 21.42 44.784 ;
     RECT  20.509 44.784 21.408 44.808 ;
     RECT  20.509 44.808 21.42 44.976 ;
     RECT  20.509 44.976 21.408 45 ;
     RECT  20.509 45 21.42 45.12 ;
     RECT  20.509 45.12 21.408 45.144 ;
     RECT  20.509 45.144 21.42 45.312 ;
     RECT  20.509 45.312 21.408 45.336 ;
     RECT  20.509 45.336 21.42 45.456 ;
     RECT  20.509 45.456 21.408 45.48 ;
     RECT  20.509 45.48 21.42 45.648 ;
     RECT  20.509 45.648 21.408 45.672 ;
     RECT  20.509 45.672 21.42 45.792 ;
     RECT  20.509 45.792 21.408 45.816 ;
     RECT  20.509 45.816 21.42 45.984 ;
     RECT  20.509 45.984 21.408 46.008 ;
     RECT  20.509 46.008 21.42 46.176 ;
     RECT  20.509 46.176 21.408 46.2 ;
     RECT  20.509 46.2 21.42 46.32 ;
     RECT  20.509 46.32 21.408 46.344 ;
     RECT  20.509 46.344 21.42 46.512 ;
     RECT  20.509 46.512 21.408 46.536 ;
     RECT  20.509 46.536 21.42 46.656 ;
     RECT  20.509 46.656 21.408 46.68 ;
     RECT  20.509 46.68 21.42 46.848 ;
     RECT  20.509 46.848 21.408 46.872 ;
     RECT  20.509 46.872 21.42 46.992 ;
     RECT  20.509 46.992 21.408 47.016 ;
     RECT  20.509 47.016 21.42 47.184 ;
     RECT  20.509 47.184 21.408 47.208 ;
     RECT  20.509 47.208 21.42 47.376 ;
     RECT  20.509 47.376 21.408 47.4 ;
     RECT  20.509 47.4 21.42 47.52 ;
     RECT  20.509 47.52 21.408 47.544 ;
     RECT  20.509 47.544 21.42 47.712 ;
     RECT  20.509 47.712 21.408 47.736 ;
     RECT  20.509 47.736 21.42 47.856 ;
     RECT  20.509 47.856 21.408 47.88 ;
     RECT  20.509 47.88 21.42 48.048 ;
     RECT  20.509 48.048 21.408 48.072 ;
     RECT  20.509 48.072 21.42 48.24 ;
     RECT  20.509 48.24 21.408 48.264 ;
     RECT  20.509 48.264 21.42 48.384 ;
     RECT  20.509 48.384 21.408 48.408 ;
     RECT  20.509 48.408 21.42 48.576 ;
     RECT  20.509 48.576 21.408 48.6 ;
     RECT  20.509 48.6 21.42 48.72 ;
     RECT  20.509 48.72 21.408 48.744 ;
     RECT  20.509 48.744 21.42 48.912 ;
     RECT  20.509 48.912 21.408 48.936 ;
     RECT  20.509 48.936 21.42 49.056 ;
     RECT  20.509 49.056 21.408 49.08 ;
     RECT  20.509 49.08 21.42 49.248 ;
     RECT  20.509 49.248 21.408 49.272 ;
     RECT  20.509 49.272 21.42 49.44 ;
     RECT  20.509 49.44 21.408 49.464 ;
     RECT  20.509 49.464 21.42 49.584 ;
     RECT  20.509 49.584 21.408 49.608 ;
     RECT  20.509 49.608 21.42 49.776 ;
     RECT  20.509 49.776 21.408 49.8 ;
     RECT  20.509 49.8 21.42 49.92 ;
     RECT  20.509 49.92 21.408 49.944 ;
     RECT  20.509 49.944 21.42 50.112 ;
     RECT  20.509 50.112 21.408 50.136 ;
     RECT  20.509 50.136 21.42 50.256 ;
     RECT  20.509 50.256 21.408 50.28 ;
     RECT  20.509 50.28 21.42 50.448 ;
     RECT  20.509 50.448 21.408 50.472 ;
     RECT  20.509 50.472 21.42 50.64 ;
     RECT  20.509 50.64 21.408 50.664 ;
     RECT  20.509 50.664 21.42 50.784 ;
     RECT  20.509 50.784 21.408 50.808 ;
     RECT  20.509 50.808 21.42 50.976 ;
     RECT  20.509 50.976 21.408 51 ;
     RECT  20.509 51 21.42 51.12 ;
     RECT  20.509 51.12 21.408 51.144 ;
     RECT  20.509 51.144 21.42 51.312 ;
     RECT  20.509 51.312 21.408 51.336 ;
     RECT  20.509 51.336 21.42 51.504 ;
     RECT  20.509 51.504 21.408 51.528 ;
     RECT  20.509 51.528 21.42 51.648 ;
     RECT  20.509 51.648 21.408 51.672 ;
    LAYER M5 ;
     RECT  10.8 1.763 10.812 2.137 ;
     RECT  2.4 2.137 2.52 2.151 ;
     RECT  5.1 2.137 5.22 2.151 ;
     RECT  7.8 2.137 7.92 2.151 ;
     RECT  13.2 2.137 13.32 2.151 ;
     RECT  15.9 2.137 16.02 2.151 ;
     RECT  18.6 2.137 18.72 2.151 ;
     RECT  5.1 2.151 5.412 4.837 ;
     RECT  4.512 4.837 5.412 5.077 ;
     RECT  7.8 2.151 8.112 5.077 ;
     RECT  0.288 5.029 0.312 5.315 ;
     RECT  6.384 5.077 8.112 6.131 ;
     RECT  0.288 6.373 0.312 6.661 ;
     RECT  2.4 2.151 2.712 6.805 ;
     RECT  0.192 6.661 0.312 7.331 ;
     RECT  4.464 5.077 5.412 7.381 ;
     RECT  2.304 6.805 2.712 8.003 ;
     RECT  0.192 7.331 0.216 8.195 ;
     RECT  0.288 8.485 0.312 8.627 ;
     RECT  3.936 7.381 5.412 8.723 ;
     RECT  6.672 6.131 8.112 9.541 ;
     RECT  2.4 8.003 2.712 9.637 ;
     RECT  4.464 8.723 5.412 10.789 ;
     RECT  6.48 9.541 8.112 10.789 ;
     RECT  0.192 9.493 0.216 11.317 ;
     RECT  0.192 11.317 0.264 11.603 ;
     RECT  0.192 11.603 0.216 12.563 ;
     RECT  2.4 9.637 2.904 12.659 ;
     RECT  0.192 13.621 0.216 14.435 ;
     RECT  0.288 15.013 0.312 15.877 ;
     RECT  2.4 12.659 2.712 16.213 ;
     RECT  2.304 16.213 2.712 16.357 ;
     RECT  2.304 16.357 2.808 16.403 ;
     RECT  0.192 15.877 0.312 16.643 ;
     RECT  0.192 16.643 0.216 16.835 ;
     RECT  2.4 16.403 2.808 16.981 ;
     RECT  2.4 16.981 2.952 17.123 ;
     RECT  2.4 17.123 2.856 18.661 ;
     RECT  0.24 19.045 0.264 19.141 ;
     RECT  0.24 19.141 0.312 19.475 ;
     RECT  2.4 18.661 3.096 19.861 ;
     RECT  0.24 19.475 0.264 20.485 ;
     RECT  0.192 20.485 0.264 20.627 ;
     RECT  0.24 20.627 0.264 20.867 ;
     RECT  2.4 19.861 3.24 21.155 ;
     RECT  0.288 21.637 0.312 22.259 ;
     RECT  9.504 22.645 9.528 22.787 ;
     RECT  0.192 22.885 0.216 23.555 ;
     RECT  4.464 10.789 8.112 25.525 ;
     RECT  2.4 21.155 2.856 25.621 ;
     RECT  0.288 24.277 0.312 25.669 ;
     RECT  2.4 25.621 3.48 26.243 ;
     RECT  0.192 25.669 0.312 26.485 ;
     RECT  9.456 26.341 9.48 26.675 ;
     RECT  2.4 26.243 2.856 27.157 ;
     RECT  4.464 25.525 8.232 27.157 ;
     RECT  4.128 27.157 8.232 27.395 ;
     RECT  0.192 26.485 0.408 27.683 ;
     RECT  0.24 27.683 0.408 27.733 ;
     RECT  4.272 27.395 8.232 28.451 ;
     RECT  4.272 28.451 8.112 28.643 ;
     RECT  2.304 27.157 2.856 28.739 ;
     RECT  0.24 27.733 0.552 29.267 ;
     RECT  0.432 29.267 0.552 29.315 ;
     RECT  0.528 29.315 0.552 29.363 ;
     RECT  2.4 28.739 2.856 29.893 ;
     RECT  2.304 29.893 2.856 30.083 ;
     RECT  4.56 28.643 8.112 30.709 ;
     RECT  4.32 30.709 8.112 30.947 ;
     RECT  18.6 2.151 18.912 39.973 ;
     RECT  18.6 39.973 19.368 40.499 ;
     RECT  2.4 30.083 2.856 40.691 ;
     RECT  2.4 40.691 2.712 40.885 ;
     RECT  2.304 40.885 2.712 41.027 ;
     RECT  4.608 30.947 8.112 41.075 ;
     RECT  4.848 41.075 8.112 42.419 ;
     RECT  4.848 42.419 6.552 46.787 ;
     RECT  7.536 42.419 8.112 46.835 ;
     RECT  6.48 46.787 6.504 47.987 ;
     RECT  4.848 46.787 5.412 50.003 ;
     RECT  0.24 51.205 0.264 51.395 ;
     RECT  2.4 41.027 2.712 54.009 ;
     RECT  5.1 50.003 5.412 54.009 ;
     RECT  7.8 46.835 8.112 54.009 ;
     RECT  10.5 2.137 10.812 54.009 ;
     RECT  13.2 2.151 13.512 54.009 ;
     RECT  15.9 2.151 16.212 54.009 ;
     RECT  18.6 40.499 18.912 54.009 ;
     RECT  2.4 54.009 2.52 54.023 ;
     RECT  5.1 54.009 5.22 54.023 ;
     RECT  7.8 54.009 7.92 54.023 ;
     RECT  10.5 54.009 10.62 54.023 ;
     RECT  13.2 54.009 13.32 54.023 ;
     RECT  15.9 54.009 16.02 54.023 ;
     RECT  18.6 54.009 18.72 54.023 ;
     RECT  5.412 5.077 6.384 6.131 ;
     RECT  0.288 5.315 0.312 6.373 ;
     RECT  5.412 6.131 6.672 9.541 ;
     RECT  0.24 7.331 0.312 7.368 ;
     RECT  0.216 7.368 0.312 7.392 ;
     RECT  2.712 7.381 3.936 8.723 ;
     RECT  0.24 7.392 0.312 7.512 ;
     RECT  0.216 7.512 0.312 7.584 ;
     RECT  0.24 7.584 0.312 7.704 ;
     RECT  0.216 7.704 0.312 7.728 ;
     RECT  0.24 7.728 0.312 7.848 ;
     RECT  0.216 7.848 0.312 7.92 ;
     RECT  0.24 7.92 0.312 8.04 ;
     RECT  0.216 8.04 0.312 8.112 ;
     RECT  0.24 8.112 0.312 8.232 ;
     RECT  0.192 8.232 0.312 8.256 ;
     RECT  0.24 8.256 0.312 8.376 ;
     RECT  0.192 8.376 0.312 8.448 ;
     RECT  0.24 8.448 0.312 8.485 ;
     RECT  0.24 8.485 0.288 8.568 ;
     RECT  0.192 8.568 0.288 8.592 ;
     RECT  0.192 8.712 0.216 8.784 ;
     RECT  2.712 8.723 2.904 9.637 ;
     RECT  0.192 8.904 0.216 8.928 ;
     RECT  0.192 9.048 0.216 9.12 ;
     RECT  0.192 9.24 0.216 9.312 ;
     RECT  0.192 9.432 0.216 9.456 ;
     RECT  5.412 9.541 6.48 10.789 ;
     RECT  0.192 12.563 0.216 12.576 ;
     RECT  0.192 12.696 0.216 12.72 ;
     RECT  0.192 12.84 0.216 12.912 ;
     RECT  0.192 13.032 0.216 13.056 ;
     RECT  0.192 13.176 0.216 13.248 ;
     RECT  0.192 13.368 0.216 13.392 ;
     RECT  0.192 13.512 0.216 13.584 ;
     RECT  0.192 14.435 0.216 14.448 ;
     RECT  0.192 14.568 0.216 14.64 ;
     RECT  0.192 14.76 0.216 14.784 ;
     RECT  0.192 14.904 0.216 14.976 ;
     RECT  0.192 15.096 0.288 15.12 ;
     RECT  0.24 15.12 0.288 15.24 ;
     RECT  0.192 15.24 0.288 15.312 ;
     RECT  0.24 15.312 0.288 15.432 ;
     RECT  0.192 15.432 0.288 15.456 ;
     RECT  0.24 15.456 0.288 15.576 ;
     RECT  0.192 15.576 0.288 15.648 ;
     RECT  0.24 15.648 0.288 15.768 ;
     RECT  0.192 15.768 0.288 15.84 ;
     RECT  0.24 15.84 0.288 15.877 ;
     RECT  2.952 16.981 4.464 17.123 ;
     RECT  3.096 18.661 4.464 19.861 ;
     RECT  3.24 19.861 4.464 21.155 ;
     RECT  8.112 22.645 9.504 22.787 ;
     RECT  9.528 22.645 10.5 22.787 ;
     RECT  3.48 25.621 4.464 26.243 ;
     RECT  2.856 26.243 4.464 27.157 ;
     RECT  8.232 26.341 9.456 26.675 ;
     RECT  9.48 26.341 10.5 26.675 ;
     RECT  2.856 27.157 4.128 27.395 ;
     RECT  2.856 27.395 4.272 28.643 ;
     RECT  2.304 28.739 2.4 29.893 ;
     RECT  2.856 30.709 4.32 30.947 ;
     RECT  6.552 42.419 7.536 46.787 ;
     RECT  5.412 46.787 6.48 47.987 ;
     RECT  6.504 46.787 7.536 46.835 ;
     RECT  6.504 46.835 7.8 47.987 ;
  END
END hbfd_rly_136_WE_fc_f3
END LIBRARY
